VERSION 5.8 ;
BUSBITCHARS "[]" ;
DIVIDERCHAR "/" ;
UNITS
    DATABASE MICRONS 1000 ;
END UNITS

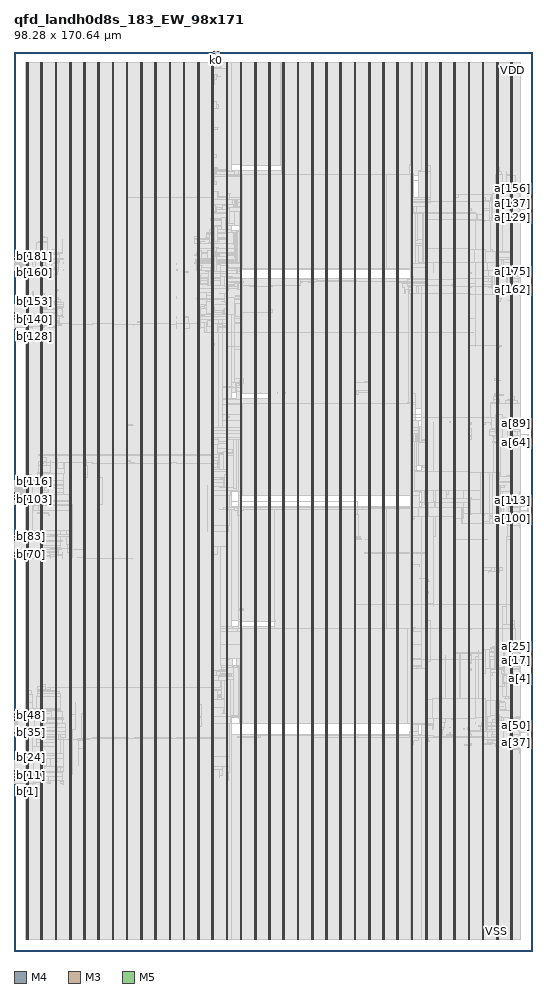
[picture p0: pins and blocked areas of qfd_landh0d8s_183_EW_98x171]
MACRO qfd_landh0d8s_183_EW_98x171
  FOREIGN qfd_landh0d8s_183_EW_98x171 0 0 ;
  CLASS BLOCK ;
  SIZE 98.28 BY 170.64 ;
  PIN a[0]
    DIRECTION INPUT ;
    USE SIGNAL ;
    PORT
      LAYER M4 ;
        RECT  98.196 52.56 98.28 52.584 ;
    END
  END a[0]
  PIN a[100]
    DIRECTION INPUT ;
    USE SIGNAL ;
    PORT
      LAYER M4 ;
        RECT  98.196 81.936 98.28 81.96 ;
    END
  END a[100]
  PIN a[101]
    DIRECTION INPUT ;
    USE SIGNAL ;
    PORT
      LAYER M4 ;
        RECT  98.196 82.08 98.28 82.104 ;
    END
  END a[101]
  PIN a[102]
    DIRECTION INPUT ;
    USE SIGNAL ;
    PORT
      LAYER M4 ;
        RECT  98.196 82.224 98.28 82.248 ;
    END
  END a[102]
  PIN a[103]
    DIRECTION INPUT ;
    USE SIGNAL ;
    PORT
      LAYER M4 ;
        RECT  98.196 82.368 98.28 82.392 ;
    END
  END a[103]
  PIN a[104]
    DIRECTION INPUT ;
    USE SIGNAL ;
    PORT
      LAYER M4 ;
        RECT  98.196 82.512 98.28 82.536 ;
    END
  END a[104]
  PIN a[105]
    DIRECTION INPUT ;
    USE SIGNAL ;
    PORT
      LAYER M4 ;
        RECT  98.196 82.656 98.28 82.68 ;
    END
  END a[105]
  PIN a[106]
    DIRECTION INPUT ;
    USE SIGNAL ;
    PORT
      LAYER M4 ;
        RECT  98.196 82.8 98.28 82.824 ;
    END
  END a[106]
  PIN a[107]
    DIRECTION INPUT ;
    USE SIGNAL ;
    PORT
      LAYER M4 ;
        RECT  98.196 82.944 98.28 82.968 ;
    END
  END a[107]
  PIN a[108]
    DIRECTION INPUT ;
    USE SIGNAL ;
    PORT
      LAYER M4 ;
        RECT  98.196 83.088 98.28 83.112 ;
    END
  END a[108]
  PIN a[109]
    DIRECTION INPUT ;
    USE SIGNAL ;
    PORT
      LAYER M4 ;
        RECT  98.196 83.232 98.28 83.256 ;
    END
  END a[109]
  PIN a[10]
    DIRECTION INPUT ;
    USE SIGNAL ;
    PORT
      LAYER M4 ;
        RECT  98.196 54 98.28 54.024 ;
    END
  END a[10]
  PIN a[110]
    DIRECTION INPUT ;
    USE SIGNAL ;
    PORT
      LAYER M4 ;
        RECT  98.196 83.376 98.28 83.4 ;
    END
  END a[110]
  PIN a[111]
    DIRECTION INPUT ;
    USE SIGNAL ;
    PORT
      LAYER M4 ;
        RECT  98.196 83.52 98.28 83.544 ;
    END
  END a[111]
  PIN a[112]
    DIRECTION INPUT ;
    USE SIGNAL ;
    PORT
      LAYER M4 ;
        RECT  98.196 83.664 98.28 83.688 ;
    END
  END a[112]
  PIN a[113]
    DIRECTION INPUT ;
    USE SIGNAL ;
    PORT
      LAYER M4 ;
        RECT  98.196 83.808 98.28 83.832 ;
    END
  END a[113]
  PIN a[114]
    DIRECTION INPUT ;
    USE SIGNAL ;
    PORT
      LAYER M4 ;
        RECT  98.196 83.952 98.28 83.976 ;
    END
  END a[114]
  PIN a[115]
    DIRECTION INPUT ;
    USE SIGNAL ;
    PORT
      LAYER M4 ;
        RECT  98.196 84.096 98.28 84.12 ;
    END
  END a[115]
  PIN a[116]
    DIRECTION INPUT ;
    USE SIGNAL ;
    PORT
      LAYER M4 ;
        RECT  98.196 84.24 98.28 84.264 ;
    END
  END a[116]
  PIN a[117]
    DIRECTION INPUT ;
    USE SIGNAL ;
    PORT
      LAYER M4 ;
        RECT  98.196 84.384 98.28 84.408 ;
    END
  END a[117]
  PIN a[118]
    DIRECTION INPUT ;
    USE SIGNAL ;
    PORT
      LAYER M4 ;
        RECT  98.196 84.528 98.28 84.552 ;
    END
  END a[118]
  PIN a[119]
    DIRECTION INPUT ;
    USE SIGNAL ;
    PORT
      LAYER M4 ;
        RECT  98.196 84.672 98.28 84.696 ;
    END
  END a[119]
  PIN a[11]
    DIRECTION INPUT ;
    USE SIGNAL ;
    PORT
      LAYER M4 ;
        RECT  98.196 54.144 98.28 54.168 ;
    END
  END a[11]
  PIN a[120]
    DIRECTION INPUT ;
    USE SIGNAL ;
    PORT
      LAYER M4 ;
        RECT  98.196 84.816 98.28 84.84 ;
    END
  END a[120]
  PIN a[121]
    DIRECTION INPUT ;
    USE SIGNAL ;
    PORT
      LAYER M4 ;
        RECT  98.196 84.96 98.28 84.984 ;
    END
  END a[121]
  PIN a[122]
    DIRECTION INPUT ;
    USE SIGNAL ;
    PORT
      LAYER M4 ;
        RECT  98.196 85.104 98.28 85.128 ;
    END
  END a[122]
  PIN a[123]
    DIRECTION INPUT ;
    USE SIGNAL ;
    PORT
      LAYER M4 ;
        RECT  98.196 85.248 98.28 85.272 ;
    END
  END a[123]
  PIN a[124]
    DIRECTION INPUT ;
    USE SIGNAL ;
    PORT
      LAYER M4 ;
        RECT  98.196 85.392 98.28 85.416 ;
    END
  END a[124]
  PIN a[125]
    DIRECTION INPUT ;
    USE SIGNAL ;
    PORT
      LAYER M4 ;
        RECT  98.196 85.536 98.28 85.56 ;
    END
  END a[125]
  PIN a[126]
    DIRECTION INPUT ;
    USE SIGNAL ;
    PORT
      LAYER M4 ;
        RECT  98.196 85.68 98.28 85.704 ;
    END
  END a[126]
  PIN a[127]
    DIRECTION INPUT ;
    USE SIGNAL ;
    PORT
      LAYER M4 ;
        RECT  98.196 85.824 98.28 85.848 ;
    END
  END a[127]
  PIN a[128]
    DIRECTION INPUT ;
    USE SIGNAL ;
    PORT
      LAYER M4 ;
        RECT  98.196 138.96 98.28 138.984 ;
    END
  END a[128]
  PIN a[129]
    DIRECTION INPUT ;
    USE SIGNAL ;
    PORT
      LAYER M4 ;
        RECT  98.196 139.104 98.28 139.128 ;
    END
  END a[129]
  PIN a[12]
    DIRECTION INPUT ;
    USE SIGNAL ;
    PORT
      LAYER M4 ;
        RECT  98.196 54.288 98.28 54.312 ;
    END
  END a[12]
  PIN a[130]
    DIRECTION INPUT ;
    USE SIGNAL ;
    PORT
      LAYER M4 ;
        RECT  98.196 139.248 98.28 139.272 ;
    END
  END a[130]
  PIN a[131]
    DIRECTION INPUT ;
    USE SIGNAL ;
    PORT
      LAYER M4 ;
        RECT  98.196 139.392 98.28 139.416 ;
    END
  END a[131]
  PIN a[132]
    DIRECTION INPUT ;
    USE SIGNAL ;
    PORT
      LAYER M4 ;
        RECT  98.196 139.536 98.28 139.56 ;
    END
  END a[132]
  PIN a[133]
    DIRECTION INPUT ;
    USE SIGNAL ;
    PORT
      LAYER M4 ;
        RECT  98.196 139.68 98.28 139.704 ;
    END
  END a[133]
  PIN a[134]
    DIRECTION INPUT ;
    USE SIGNAL ;
    PORT
      LAYER M4 ;
        RECT  98.196 139.824 98.28 139.848 ;
    END
  END a[134]
  PIN a[135]
    DIRECTION INPUT ;
    USE SIGNAL ;
    PORT
      LAYER M4 ;
        RECT  98.196 139.968 98.28 139.992 ;
    END
  END a[135]
  PIN a[136]
    DIRECTION INPUT ;
    USE SIGNAL ;
    PORT
      LAYER M4 ;
        RECT  98.196 140.112 98.28 140.136 ;
    END
  END a[136]
  PIN a[137]
    DIRECTION INPUT ;
    USE SIGNAL ;
    PORT
      LAYER M4 ;
        RECT  98.196 140.256 98.28 140.28 ;
    END
  END a[137]
  PIN a[138]
    DIRECTION INPUT ;
    USE SIGNAL ;
    PORT
      LAYER M4 ;
        RECT  98.196 140.4 98.28 140.424 ;
    END
  END a[138]
  PIN a[139]
    DIRECTION INPUT ;
    USE SIGNAL ;
    PORT
      LAYER M4 ;
        RECT  98.196 140.544 98.28 140.568 ;
    END
  END a[139]
  PIN a[13]
    DIRECTION INPUT ;
    USE SIGNAL ;
    PORT
      LAYER M4 ;
        RECT  98.196 54.432 98.28 54.456 ;
    END
  END a[13]
  PIN a[140]
    DIRECTION INPUT ;
    USE SIGNAL ;
    PORT
      LAYER M4 ;
        RECT  98.196 140.688 98.28 140.712 ;
    END
  END a[140]
  PIN a[141]
    DIRECTION INPUT ;
    USE SIGNAL ;
    PORT
      LAYER M4 ;
        RECT  98.196 140.832 98.28 140.856 ;
    END
  END a[141]
  PIN a[142]
    DIRECTION INPUT ;
    USE SIGNAL ;
    PORT
      LAYER M4 ;
        RECT  98.196 140.976 98.28 141 ;
    END
  END a[142]
  PIN a[143]
    DIRECTION INPUT ;
    USE SIGNAL ;
    PORT
      LAYER M4 ;
        RECT  98.196 141.12 98.28 141.144 ;
    END
  END a[143]
  PIN a[144]
    DIRECTION INPUT ;
    USE SIGNAL ;
    PORT
      LAYER M4 ;
        RECT  98.196 141.264 98.28 141.288 ;
    END
  END a[144]
  PIN a[145]
    DIRECTION INPUT ;
    USE SIGNAL ;
    PORT
      LAYER M4 ;
        RECT  98.196 141.408 98.28 141.432 ;
    END
  END a[145]
  PIN a[146]
    DIRECTION INPUT ;
    USE SIGNAL ;
    PORT
      LAYER M4 ;
        RECT  98.196 141.552 98.28 141.576 ;
    END
  END a[146]
  PIN a[147]
    DIRECTION INPUT ;
    USE SIGNAL ;
    PORT
      LAYER M4 ;
        RECT  98.196 141.696 98.28 141.72 ;
    END
  END a[147]
  PIN a[148]
    DIRECTION INPUT ;
    USE SIGNAL ;
    PORT
      LAYER M4 ;
        RECT  98.196 141.84 98.28 141.864 ;
    END
  END a[148]
  PIN a[149]
    DIRECTION INPUT ;
    USE SIGNAL ;
    PORT
      LAYER M4 ;
        RECT  98.196 141.984 98.28 142.008 ;
    END
  END a[149]
  PIN a[14]
    DIRECTION INPUT ;
    USE SIGNAL ;
    PORT
      LAYER M4 ;
        RECT  98.196 54.576 98.28 54.6 ;
    END
  END a[14]
  PIN a[150]
    DIRECTION INPUT ;
    USE SIGNAL ;
    PORT
      LAYER M4 ;
        RECT  98.196 142.128 98.28 142.152 ;
    END
  END a[150]
  PIN a[151]
    DIRECTION INPUT ;
    USE SIGNAL ;
    PORT
      LAYER M4 ;
        RECT  98.196 142.272 98.28 142.296 ;
    END
  END a[151]
  PIN a[152]
    DIRECTION INPUT ;
    USE SIGNAL ;
    PORT
      LAYER M4 ;
        RECT  98.196 142.416 98.28 142.44 ;
    END
  END a[152]
  PIN a[153]
    DIRECTION INPUT ;
    USE SIGNAL ;
    PORT
      LAYER M4 ;
        RECT  98.196 142.56 98.28 142.584 ;
    END
  END a[153]
  PIN a[154]
    DIRECTION INPUT ;
    USE SIGNAL ;
    PORT
      LAYER M4 ;
        RECT  98.196 142.704 98.28 142.728 ;
    END
  END a[154]
  PIN a[155]
    DIRECTION INPUT ;
    USE SIGNAL ;
    PORT
      LAYER M4 ;
        RECT  98.196 142.848 98.28 142.872 ;
    END
  END a[155]
  PIN a[156]
    DIRECTION INPUT ;
    USE SIGNAL ;
    PORT
      LAYER M4 ;
        RECT  98.196 142.992 98.28 143.016 ;
    END
  END a[156]
  PIN a[157]
    DIRECTION INPUT ;
    USE SIGNAL ;
    PORT
      LAYER M4 ;
        RECT  98.196 143.136 98.28 143.16 ;
    END
  END a[157]
  PIN a[158]
    DIRECTION INPUT ;
    USE SIGNAL ;
    PORT
      LAYER M4 ;
        RECT  98.196 143.28 98.28 143.304 ;
    END
  END a[158]
  PIN a[159]
    DIRECTION INPUT ;
    USE SIGNAL ;
    PORT
      LAYER M4 ;
        RECT  98.196 143.424 98.28 143.448 ;
    END
  END a[159]
  PIN a[15]
    DIRECTION INPUT ;
    USE SIGNAL ;
    PORT
      LAYER M4 ;
        RECT  98.196 54.72 98.28 54.744 ;
    END
  END a[15]
  PIN a[160]
    DIRECTION INPUT ;
    USE SIGNAL ;
    PORT
      LAYER M4 ;
        RECT  98.196 125.136 98.28 125.16 ;
    END
  END a[160]
  PIN a[161]
    DIRECTION INPUT ;
    USE SIGNAL ;
    PORT
      LAYER M4 ;
        RECT  98.196 125.28 98.28 125.304 ;
    END
  END a[161]
  PIN a[162]
    DIRECTION INPUT ;
    USE SIGNAL ;
    PORT
      LAYER M4 ;
        RECT  98.196 125.424 98.28 125.448 ;
    END
  END a[162]
  PIN a[163]
    DIRECTION INPUT ;
    USE SIGNAL ;
    PORT
      LAYER M4 ;
        RECT  98.196 125.568 98.28 125.592 ;
    END
  END a[163]
  PIN a[164]
    DIRECTION INPUT ;
    USE SIGNAL ;
    PORT
      LAYER M4 ;
        RECT  98.196 125.712 98.28 125.736 ;
    END
  END a[164]
  PIN a[165]
    DIRECTION INPUT ;
    USE SIGNAL ;
    PORT
      LAYER M4 ;
        RECT  98.196 125.856 98.28 125.88 ;
    END
  END a[165]
  PIN a[166]
    DIRECTION INPUT ;
    USE SIGNAL ;
    PORT
      LAYER M4 ;
        RECT  98.196 126 98.28 126.024 ;
    END
  END a[166]
  PIN a[167]
    DIRECTION INPUT ;
    USE SIGNAL ;
    PORT
      LAYER M4 ;
        RECT  98.196 126.144 98.28 126.168 ;
    END
  END a[167]
  PIN a[168]
    DIRECTION INPUT ;
    USE SIGNAL ;
    PORT
      LAYER M4 ;
        RECT  98.196 126.288 98.28 126.312 ;
    END
  END a[168]
  PIN a[169]
    DIRECTION INPUT ;
    USE SIGNAL ;
    PORT
      LAYER M4 ;
        RECT  98.196 126.432 98.28 126.456 ;
    END
  END a[169]
  PIN a[16]
    DIRECTION INPUT ;
    USE SIGNAL ;
    PORT
      LAYER M4 ;
        RECT  98.196 54.864 98.28 54.888 ;
    END
  END a[16]
  PIN a[170]
    DIRECTION INPUT ;
    USE SIGNAL ;
    PORT
      LAYER M4 ;
        RECT  98.196 126.576 98.28 126.6 ;
    END
  END a[170]
  PIN a[171]
    DIRECTION INPUT ;
    USE SIGNAL ;
    PORT
      LAYER M4 ;
        RECT  98.196 126.72 98.28 126.744 ;
    END
  END a[171]
  PIN a[172]
    DIRECTION INPUT ;
    USE SIGNAL ;
    PORT
      LAYER M4 ;
        RECT  98.196 126.864 98.28 126.888 ;
    END
  END a[172]
  PIN a[173]
    DIRECTION INPUT ;
    USE SIGNAL ;
    PORT
      LAYER M4 ;
        RECT  98.196 127.008 98.28 127.032 ;
    END
  END a[173]
  PIN a[174]
    DIRECTION INPUT ;
    USE SIGNAL ;
    PORT
      LAYER M4 ;
        RECT  98.196 127.152 98.28 127.176 ;
    END
  END a[174]
  PIN a[175]
    DIRECTION INPUT ;
    USE SIGNAL ;
    PORT
      LAYER M4 ;
        RECT  98.196 127.296 98.28 127.32 ;
    END
  END a[175]
  PIN a[176]
    DIRECTION INPUT ;
    USE SIGNAL ;
    PORT
      LAYER M4 ;
        RECT  98.196 127.44 98.28 127.464 ;
    END
  END a[176]
  PIN a[177]
    DIRECTION INPUT ;
    USE SIGNAL ;
    PORT
      LAYER M4 ;
        RECT  98.196 127.584 98.28 127.608 ;
    END
  END a[177]
  PIN a[178]
    DIRECTION INPUT ;
    USE SIGNAL ;
    PORT
      LAYER M4 ;
        RECT  98.196 127.728 98.28 127.752 ;
    END
  END a[178]
  PIN a[179]
    DIRECTION INPUT ;
    USE SIGNAL ;
    PORT
      LAYER M4 ;
        RECT  98.196 127.872 98.28 127.896 ;
    END
  END a[179]
  PIN a[17]
    DIRECTION INPUT ;
    USE SIGNAL ;
    PORT
      LAYER M4 ;
        RECT  98.196 55.008 98.28 55.032 ;
    END
  END a[17]
  PIN a[180]
    DIRECTION INPUT ;
    USE SIGNAL ;
    PORT
      LAYER M4 ;
        RECT  98.196 128.016 98.28 128.04 ;
    END
  END a[180]
  PIN a[181]
    DIRECTION INPUT ;
    USE SIGNAL ;
    PORT
      LAYER M4 ;
        RECT  98.196 128.16 98.28 128.184 ;
    END
  END a[181]
  PIN a[182]
    DIRECTION INPUT ;
    USE SIGNAL ;
    PORT
      LAYER M4 ;
        RECT  98.196 128.304 98.28 128.328 ;
    END
  END a[182]
  PIN a[18]
    DIRECTION INPUT ;
    USE SIGNAL ;
    PORT
      LAYER M4 ;
        RECT  98.196 55.152 98.28 55.176 ;
    END
  END a[18]
  PIN a[19]
    DIRECTION INPUT ;
    USE SIGNAL ;
    PORT
      LAYER M4 ;
        RECT  98.196 55.296 98.28 55.32 ;
    END
  END a[19]
  PIN a[1]
    DIRECTION INPUT ;
    USE SIGNAL ;
    PORT
      LAYER M4 ;
        RECT  98.196 52.704 98.28 52.728 ;
    END
  END a[1]
  PIN a[20]
    DIRECTION INPUT ;
    USE SIGNAL ;
    PORT
      LAYER M4 ;
        RECT  98.196 55.44 98.28 55.464 ;
    END
  END a[20]
  PIN a[21]
    DIRECTION INPUT ;
    USE SIGNAL ;
    PORT
      LAYER M4 ;
        RECT  98.196 55.584 98.28 55.608 ;
    END
  END a[21]
  PIN a[22]
    DIRECTION INPUT ;
    USE SIGNAL ;
    PORT
      LAYER M4 ;
        RECT  98.196 55.728 98.28 55.752 ;
    END
  END a[22]
  PIN a[23]
    DIRECTION INPUT ;
    USE SIGNAL ;
    PORT
      LAYER M4 ;
        RECT  98.196 55.872 98.28 55.896 ;
    END
  END a[23]
  PIN a[24]
    DIRECTION INPUT ;
    USE SIGNAL ;
    PORT
      LAYER M4 ;
        RECT  98.196 56.016 98.28 56.04 ;
    END
  END a[24]
  PIN a[25]
    DIRECTION INPUT ;
    USE SIGNAL ;
    PORT
      LAYER M4 ;
        RECT  98.196 56.16 98.28 56.184 ;
    END
  END a[25]
  PIN a[26]
    DIRECTION INPUT ;
    USE SIGNAL ;
    PORT
      LAYER M4 ;
        RECT  98.196 56.304 98.28 56.328 ;
    END
  END a[26]
  PIN a[27]
    DIRECTION INPUT ;
    USE SIGNAL ;
    PORT
      LAYER M4 ;
        RECT  98.196 56.448 98.28 56.472 ;
    END
  END a[27]
  PIN a[28]
    DIRECTION INPUT ;
    USE SIGNAL ;
    PORT
      LAYER M4 ;
        RECT  98.196 56.592 98.28 56.616 ;
    END
  END a[28]
  PIN a[29]
    DIRECTION INPUT ;
    USE SIGNAL ;
    PORT
      LAYER M4 ;
        RECT  98.196 56.736 98.28 56.76 ;
    END
  END a[29]
  PIN a[2]
    DIRECTION INPUT ;
    USE SIGNAL ;
    PORT
      LAYER M4 ;
        RECT  98.196 52.848 98.28 52.872 ;
    END
  END a[2]
  PIN a[30]
    DIRECTION INPUT ;
    USE SIGNAL ;
    PORT
      LAYER M4 ;
        RECT  98.196 56.88 98.28 56.904 ;
    END
  END a[30]
  PIN a[31]
    DIRECTION INPUT ;
    USE SIGNAL ;
    PORT
      LAYER M4 ;
        RECT  98.196 57.024 98.28 57.048 ;
    END
  END a[31]
  PIN a[32]
    DIRECTION INPUT ;
    USE SIGNAL ;
    PORT
      LAYER M4 ;
        RECT  98.196 38.736 98.28 38.76 ;
    END
  END a[32]
  PIN a[33]
    DIRECTION INPUT ;
    USE SIGNAL ;
    PORT
      LAYER M4 ;
        RECT  98.196 38.88 98.28 38.904 ;
    END
  END a[33]
  PIN a[34]
    DIRECTION INPUT ;
    USE SIGNAL ;
    PORT
      LAYER M4 ;
        RECT  98.196 39.024 98.28 39.048 ;
    END
  END a[34]
  PIN a[35]
    DIRECTION INPUT ;
    USE SIGNAL ;
    PORT
      LAYER M4 ;
        RECT  98.196 39.168 98.28 39.192 ;
    END
  END a[35]
  PIN a[36]
    DIRECTION INPUT ;
    USE SIGNAL ;
    PORT
      LAYER M4 ;
        RECT  98.196 39.312 98.28 39.336 ;
    END
  END a[36]
  PIN a[37]
    DIRECTION INPUT ;
    USE SIGNAL ;
    PORT
      LAYER M4 ;
        RECT  98.196 39.456 98.28 39.48 ;
    END
  END a[37]
  PIN a[38]
    DIRECTION INPUT ;
    USE SIGNAL ;
    PORT
      LAYER M4 ;
        RECT  98.196 39.6 98.28 39.624 ;
    END
  END a[38]
  PIN a[39]
    DIRECTION INPUT ;
    USE SIGNAL ;
    PORT
      LAYER M4 ;
        RECT  98.196 39.744 98.28 39.768 ;
    END
  END a[39]
  PIN a[3]
    DIRECTION INPUT ;
    USE SIGNAL ;
    PORT
      LAYER M4 ;
        RECT  98.196 52.992 98.28 53.016 ;
    END
  END a[3]
  PIN a[40]
    DIRECTION INPUT ;
    USE SIGNAL ;
    PORT
      LAYER M4 ;
        RECT  98.196 39.888 98.28 39.912 ;
    END
  END a[40]
  PIN a[41]
    DIRECTION INPUT ;
    USE SIGNAL ;
    PORT
      LAYER M4 ;
        RECT  98.196 40.032 98.28 40.056 ;
    END
  END a[41]
  PIN a[42]
    DIRECTION INPUT ;
    USE SIGNAL ;
    PORT
      LAYER M4 ;
        RECT  98.196 40.176 98.28 40.2 ;
    END
  END a[42]
  PIN a[43]
    DIRECTION INPUT ;
    USE SIGNAL ;
    PORT
      LAYER M4 ;
        RECT  98.196 40.32 98.28 40.344 ;
    END
  END a[43]
  PIN a[44]
    DIRECTION INPUT ;
    USE SIGNAL ;
    PORT
      LAYER M4 ;
        RECT  98.196 40.464 98.28 40.488 ;
    END
  END a[44]
  PIN a[45]
    DIRECTION INPUT ;
    USE SIGNAL ;
    PORT
      LAYER M4 ;
        RECT  98.196 40.608 98.28 40.632 ;
    END
  END a[45]
  PIN a[46]
    DIRECTION INPUT ;
    USE SIGNAL ;
    PORT
      LAYER M4 ;
        RECT  98.196 40.752 98.28 40.776 ;
    END
  END a[46]
  PIN a[47]
    DIRECTION INPUT ;
    USE SIGNAL ;
    PORT
      LAYER M4 ;
        RECT  98.196 40.896 98.28 40.92 ;
    END
  END a[47]
  PIN a[48]
    DIRECTION INPUT ;
    USE SIGNAL ;
    PORT
      LAYER M4 ;
        RECT  98.196 41.04 98.28 41.064 ;
    END
  END a[48]
  PIN a[49]
    DIRECTION INPUT ;
    USE SIGNAL ;
    PORT
      LAYER M4 ;
        RECT  98.196 41.184 98.28 41.208 ;
    END
  END a[49]
  PIN a[4]
    DIRECTION INPUT ;
    USE SIGNAL ;
    PORT
      LAYER M4 ;
        RECT  98.196 53.136 98.28 53.16 ;
    END
  END a[4]
  PIN a[50]
    DIRECTION INPUT ;
    USE SIGNAL ;
    PORT
      LAYER M4 ;
        RECT  98.196 41.328 98.28 41.352 ;
    END
  END a[50]
  PIN a[51]
    DIRECTION INPUT ;
    USE SIGNAL ;
    PORT
      LAYER M4 ;
        RECT  98.196 41.472 98.28 41.496 ;
    END
  END a[51]
  PIN a[52]
    DIRECTION INPUT ;
    USE SIGNAL ;
    PORT
      LAYER M4 ;
        RECT  98.196 41.616 98.28 41.64 ;
    END
  END a[52]
  PIN a[53]
    DIRECTION INPUT ;
    USE SIGNAL ;
    PORT
      LAYER M4 ;
        RECT  98.196 41.76 98.28 41.784 ;
    END
  END a[53]
  PIN a[54]
    DIRECTION INPUT ;
    USE SIGNAL ;
    PORT
      LAYER M4 ;
        RECT  98.196 41.904 98.28 41.928 ;
    END
  END a[54]
  PIN a[55]
    DIRECTION INPUT ;
    USE SIGNAL ;
    PORT
      LAYER M4 ;
        RECT  98.196 42.048 98.28 42.072 ;
    END
  END a[55]
  PIN a[56]
    DIRECTION INPUT ;
    USE SIGNAL ;
    PORT
      LAYER M4 ;
        RECT  98.196 42.192 98.28 42.216 ;
    END
  END a[56]
  PIN a[57]
    DIRECTION INPUT ;
    USE SIGNAL ;
    PORT
      LAYER M4 ;
        RECT  98.196 42.336 98.28 42.36 ;
    END
  END a[57]
  PIN a[58]
    DIRECTION INPUT ;
    USE SIGNAL ;
    PORT
      LAYER M4 ;
        RECT  98.196 42.48 98.28 42.504 ;
    END
  END a[58]
  PIN a[59]
    DIRECTION INPUT ;
    USE SIGNAL ;
    PORT
      LAYER M4 ;
        RECT  98.196 42.624 98.28 42.648 ;
    END
  END a[59]
  PIN a[5]
    DIRECTION INPUT ;
    USE SIGNAL ;
    PORT
      LAYER M4 ;
        RECT  98.196 53.28 98.28 53.304 ;
    END
  END a[5]
  PIN a[60]
    DIRECTION INPUT ;
    USE SIGNAL ;
    PORT
      LAYER M4 ;
        RECT  98.196 42.768 98.28 42.792 ;
    END
  END a[60]
  PIN a[61]
    DIRECTION INPUT ;
    USE SIGNAL ;
    PORT
      LAYER M4 ;
        RECT  98.196 42.912 98.28 42.936 ;
    END
  END a[61]
  PIN a[62]
    DIRECTION INPUT ;
    USE SIGNAL ;
    PORT
      LAYER M4 ;
        RECT  98.196 43.056 98.28 43.08 ;
    END
  END a[62]
  PIN a[63]
    DIRECTION INPUT ;
    USE SIGNAL ;
    PORT
      LAYER M4 ;
        RECT  98.196 43.2 98.28 43.224 ;
    END
  END a[63]
  PIN a[64]
    DIRECTION INPUT ;
    USE SIGNAL ;
    PORT
      LAYER M4 ;
        RECT  98.196 96.336 98.28 96.36 ;
    END
  END a[64]
  PIN a[65]
    DIRECTION INPUT ;
    USE SIGNAL ;
    PORT
      LAYER M4 ;
        RECT  98.196 96.48 98.28 96.504 ;
    END
  END a[65]
  PIN a[66]
    DIRECTION INPUT ;
    USE SIGNAL ;
    PORT
      LAYER M4 ;
        RECT  98.196 96.624 98.28 96.648 ;
    END
  END a[66]
  PIN a[67]
    DIRECTION INPUT ;
    USE SIGNAL ;
    PORT
      LAYER M4 ;
        RECT  98.196 96.768 98.28 96.792 ;
    END
  END a[67]
  PIN a[68]
    DIRECTION INPUT ;
    USE SIGNAL ;
    PORT
      LAYER M4 ;
        RECT  98.196 96.912 98.28 96.936 ;
    END
  END a[68]
  PIN a[69]
    DIRECTION INPUT ;
    USE SIGNAL ;
    PORT
      LAYER M4 ;
        RECT  98.196 97.056 98.28 97.08 ;
    END
  END a[69]
  PIN a[6]
    DIRECTION INPUT ;
    USE SIGNAL ;
    PORT
      LAYER M4 ;
        RECT  98.196 53.424 98.28 53.448 ;
    END
  END a[6]
  PIN a[70]
    DIRECTION INPUT ;
    USE SIGNAL ;
    PORT
      LAYER M4 ;
        RECT  98.196 97.2 98.28 97.224 ;
    END
  END a[70]
  PIN a[71]
    DIRECTION INPUT ;
    USE SIGNAL ;
    PORT
      LAYER M4 ;
        RECT  98.196 97.344 98.28 97.368 ;
    END
  END a[71]
  PIN a[72]
    DIRECTION INPUT ;
    USE SIGNAL ;
    PORT
      LAYER M4 ;
        RECT  98.196 97.488 98.28 97.512 ;
    END
  END a[72]
  PIN a[73]
    DIRECTION INPUT ;
    USE SIGNAL ;
    PORT
      LAYER M4 ;
        RECT  98.196 97.632 98.28 97.656 ;
    END
  END a[73]
  PIN a[74]
    DIRECTION INPUT ;
    USE SIGNAL ;
    PORT
      LAYER M4 ;
        RECT  98.196 97.776 98.28 97.8 ;
    END
  END a[74]
  PIN a[75]
    DIRECTION INPUT ;
    USE SIGNAL ;
    PORT
      LAYER M4 ;
        RECT  98.196 97.92 98.28 97.944 ;
    END
  END a[75]
  PIN a[76]
    DIRECTION INPUT ;
    USE SIGNAL ;
    PORT
      LAYER M4 ;
        RECT  98.196 98.064 98.28 98.088 ;
    END
  END a[76]
  PIN a[77]
    DIRECTION INPUT ;
    USE SIGNAL ;
    PORT
      LAYER M4 ;
        RECT  98.196 98.208 98.28 98.232 ;
    END
  END a[77]
  PIN a[78]
    DIRECTION INPUT ;
    USE SIGNAL ;
    PORT
      LAYER M4 ;
        RECT  98.196 98.352 98.28 98.376 ;
    END
  END a[78]
  PIN a[79]
    DIRECTION INPUT ;
    USE SIGNAL ;
    PORT
      LAYER M4 ;
        RECT  98.196 98.496 98.28 98.52 ;
    END
  END a[79]
  PIN a[7]
    DIRECTION INPUT ;
    USE SIGNAL ;
    PORT
      LAYER M4 ;
        RECT  98.196 53.568 98.28 53.592 ;
    END
  END a[7]
  PIN a[80]
    DIRECTION INPUT ;
    USE SIGNAL ;
    PORT
      LAYER M4 ;
        RECT  98.196 98.64 98.28 98.664 ;
    END
  END a[80]
  PIN a[81]
    DIRECTION INPUT ;
    USE SIGNAL ;
    PORT
      LAYER M4 ;
        RECT  98.196 98.784 98.28 98.808 ;
    END
  END a[81]
  PIN a[82]
    DIRECTION INPUT ;
    USE SIGNAL ;
    PORT
      LAYER M4 ;
        RECT  98.196 98.928 98.28 98.952 ;
    END
  END a[82]
  PIN a[83]
    DIRECTION INPUT ;
    USE SIGNAL ;
    PORT
      LAYER M4 ;
        RECT  98.196 99.072 98.28 99.096 ;
    END
  END a[83]
  PIN a[84]
    DIRECTION INPUT ;
    USE SIGNAL ;
    PORT
      LAYER M4 ;
        RECT  98.196 99.216 98.28 99.24 ;
    END
  END a[84]
  PIN a[85]
    DIRECTION INPUT ;
    USE SIGNAL ;
    PORT
      LAYER M4 ;
        RECT  98.196 99.36 98.28 99.384 ;
    END
  END a[85]
  PIN a[86]
    DIRECTION INPUT ;
    USE SIGNAL ;
    PORT
      LAYER M4 ;
        RECT  98.196 99.504 98.28 99.528 ;
    END
  END a[86]
  PIN a[87]
    DIRECTION INPUT ;
    USE SIGNAL ;
    PORT
      LAYER M4 ;
        RECT  98.196 99.648 98.28 99.672 ;
    END
  END a[87]
  PIN a[88]
    DIRECTION INPUT ;
    USE SIGNAL ;
    PORT
      LAYER M4 ;
        RECT  98.196 99.792 98.28 99.816 ;
    END
  END a[88]
  PIN a[89]
    DIRECTION INPUT ;
    USE SIGNAL ;
    PORT
      LAYER M4 ;
        RECT  98.196 99.936 98.28 99.96 ;
    END
  END a[89]
  PIN a[8]
    DIRECTION INPUT ;
    USE SIGNAL ;
    PORT
      LAYER M4 ;
        RECT  98.196 53.712 98.28 53.736 ;
    END
  END a[8]
  PIN a[90]
    DIRECTION INPUT ;
    USE SIGNAL ;
    PORT
      LAYER M4 ;
        RECT  98.196 100.08 98.28 100.104 ;
    END
  END a[90]
  PIN a[91]
    DIRECTION INPUT ;
    USE SIGNAL ;
    PORT
      LAYER M4 ;
        RECT  98.196 100.224 98.28 100.248 ;
    END
  END a[91]
  PIN a[92]
    DIRECTION INPUT ;
    USE SIGNAL ;
    PORT
      LAYER M4 ;
        RECT  98.196 100.368 98.28 100.392 ;
    END
  END a[92]
  PIN a[93]
    DIRECTION INPUT ;
    USE SIGNAL ;
    PORT
      LAYER M4 ;
        RECT  98.196 100.512 98.28 100.536 ;
    END
  END a[93]
  PIN a[94]
    DIRECTION INPUT ;
    USE SIGNAL ;
    PORT
      LAYER M4 ;
        RECT  98.196 100.656 98.28 100.68 ;
    END
  END a[94]
  PIN a[95]
    DIRECTION INPUT ;
    USE SIGNAL ;
    PORT
      LAYER M4 ;
        RECT  98.196 100.8 98.28 100.824 ;
    END
  END a[95]
  PIN a[96]
    DIRECTION INPUT ;
    USE SIGNAL ;
    PORT
      LAYER M4 ;
        RECT  98.196 81.36 98.28 81.384 ;
    END
  END a[96]
  PIN a[97]
    DIRECTION INPUT ;
    USE SIGNAL ;
    PORT
      LAYER M4 ;
        RECT  98.196 81.504 98.28 81.528 ;
    END
  END a[97]
  PIN a[98]
    DIRECTION INPUT ;
    USE SIGNAL ;
    PORT
      LAYER M4 ;
        RECT  98.196 81.648 98.28 81.672 ;
    END
  END a[98]
  PIN a[99]
    DIRECTION INPUT ;
    USE SIGNAL ;
    PORT
      LAYER M4 ;
        RECT  98.196 81.792 98.28 81.816 ;
    END
  END a[99]
  PIN a[9]
    DIRECTION INPUT ;
    USE SIGNAL ;
    PORT
      LAYER M4 ;
        RECT  98.196 53.856 98.28 53.88 ;
    END
  END a[9]
  PIN b[0]
    DIRECTION OUTPUT ;
    USE SIGNAL ;
    PORT
      LAYER M4 ;
        RECT  0 31.68 0.084 31.704 ;
    END
  END b[0]
  PIN b[100]
    DIRECTION OUTPUT ;
    USE SIGNAL ;
    PORT
      LAYER M4 ;
        RECT  0 85.248 0.084 85.272 ;
    END
  END b[100]
  PIN b[101]
    DIRECTION OUTPUT ;
    USE SIGNAL ;
    PORT
      LAYER M4 ;
        RECT  0 85.392 0.084 85.416 ;
    END
  END b[101]
  PIN b[102]
    DIRECTION OUTPUT ;
    USE SIGNAL ;
    PORT
      LAYER M4 ;
        RECT  0 85.536 0.084 85.56 ;
    END
  END b[102]
  PIN b[103]
    DIRECTION OUTPUT ;
    USE SIGNAL ;
    PORT
      LAYER M4 ;
        RECT  0 85.68 0.084 85.704 ;
    END
  END b[103]
  PIN b[104]
    DIRECTION OUTPUT ;
    USE SIGNAL ;
    PORT
      LAYER M4 ;
        RECT  0 85.824 0.084 85.848 ;
    END
  END b[104]
  PIN b[105]
    DIRECTION OUTPUT ;
    USE SIGNAL ;
    PORT
      LAYER M4 ;
        RECT  0 85.968 0.084 85.992 ;
    END
  END b[105]
  PIN b[106]
    DIRECTION OUTPUT ;
    USE SIGNAL ;
    PORT
      LAYER M4 ;
        RECT  0 86.112 0.084 86.136 ;
    END
  END b[106]
  PIN b[107]
    DIRECTION OUTPUT ;
    USE SIGNAL ;
    PORT
      LAYER M4 ;
        RECT  0 86.256 0.084 86.28 ;
    END
  END b[107]
  PIN b[108]
    DIRECTION OUTPUT ;
    USE SIGNAL ;
    PORT
      LAYER M4 ;
        RECT  0 86.4 0.084 86.424 ;
    END
  END b[108]
  PIN b[109]
    DIRECTION OUTPUT ;
    USE SIGNAL ;
    PORT
      LAYER M4 ;
        RECT  0 86.544 0.084 86.568 ;
    END
  END b[109]
  PIN b[10]
    DIRECTION OUTPUT ;
    USE SIGNAL ;
    PORT
      LAYER M4 ;
        RECT  0 33.12 0.084 33.144 ;
    END
  END b[10]
  PIN b[110]
    DIRECTION OUTPUT ;
    USE SIGNAL ;
    PORT
      LAYER M4 ;
        RECT  0 86.688 0.084 86.712 ;
    END
  END b[110]
  PIN b[111]
    DIRECTION OUTPUT ;
    USE SIGNAL ;
    PORT
      LAYER M4 ;
        RECT  0 86.832 0.084 86.856 ;
    END
  END b[111]
  PIN b[112]
    DIRECTION OUTPUT ;
    USE SIGNAL ;
    PORT
      LAYER M4 ;
        RECT  0 86.976 0.084 87 ;
    END
  END b[112]
  PIN b[113]
    DIRECTION OUTPUT ;
    USE SIGNAL ;
    PORT
      LAYER M4 ;
        RECT  0 87.12 0.084 87.144 ;
    END
  END b[113]
  PIN b[114]
    DIRECTION OUTPUT ;
    USE SIGNAL ;
    PORT
      LAYER M4 ;
        RECT  0 87.264 0.084 87.288 ;
    END
  END b[114]
  PIN b[115]
    DIRECTION OUTPUT ;
    USE SIGNAL ;
    PORT
      LAYER M4 ;
        RECT  0 87.408 0.084 87.432 ;
    END
  END b[115]
  PIN b[116]
    DIRECTION OUTPUT ;
    USE SIGNAL ;
    PORT
      LAYER M4 ;
        RECT  0 87.552 0.084 87.576 ;
    END
  END b[116]
  PIN b[117]
    DIRECTION OUTPUT ;
    USE SIGNAL ;
    PORT
      LAYER M4 ;
        RECT  0 87.696 0.084 87.72 ;
    END
  END b[117]
  PIN b[118]
    DIRECTION OUTPUT ;
    USE SIGNAL ;
    PORT
      LAYER M4 ;
        RECT  0 87.84 0.084 87.864 ;
    END
  END b[118]
  PIN b[119]
    DIRECTION OUTPUT ;
    USE SIGNAL ;
    PORT
      LAYER M4 ;
        RECT  0 87.984 0.084 88.008 ;
    END
  END b[119]
  PIN b[11]
    DIRECTION OUTPUT ;
    USE SIGNAL ;
    PORT
      LAYER M4 ;
        RECT  0 33.264 0.084 33.288 ;
    END
  END b[11]
  PIN b[120]
    DIRECTION OUTPUT ;
    USE SIGNAL ;
    PORT
      LAYER M4 ;
        RECT  0 88.128 0.084 88.152 ;
    END
  END b[120]
  PIN b[121]
    DIRECTION OUTPUT ;
    USE SIGNAL ;
    PORT
      LAYER M4 ;
        RECT  0 88.272 0.084 88.296 ;
    END
  END b[121]
  PIN b[122]
    DIRECTION OUTPUT ;
    USE SIGNAL ;
    PORT
      LAYER M4 ;
        RECT  0 88.416 0.084 88.44 ;
    END
  END b[122]
  PIN b[123]
    DIRECTION OUTPUT ;
    USE SIGNAL ;
    PORT
      LAYER M4 ;
        RECT  0 88.56 0.084 88.584 ;
    END
  END b[123]
  PIN b[124]
    DIRECTION OUTPUT ;
    USE SIGNAL ;
    PORT
      LAYER M4 ;
        RECT  0 88.704 0.084 88.728 ;
    END
  END b[124]
  PIN b[125]
    DIRECTION OUTPUT ;
    USE SIGNAL ;
    PORT
      LAYER M4 ;
        RECT  0 88.848 0.084 88.872 ;
    END
  END b[125]
  PIN b[126]
    DIRECTION OUTPUT ;
    USE SIGNAL ;
    PORT
      LAYER M4 ;
        RECT  0 88.992 0.084 89.016 ;
    END
  END b[126]
  PIN b[127]
    DIRECTION OUTPUT ;
    USE SIGNAL ;
    PORT
      LAYER M4 ;
        RECT  0 89.136 0.084 89.16 ;
    END
  END b[127]
  PIN b[128]
    DIRECTION OUTPUT ;
    USE SIGNAL ;
    PORT
      LAYER M4 ;
        RECT  0 118.08 0.084 118.104 ;
    END
  END b[128]
  PIN b[129]
    DIRECTION OUTPUT ;
    USE SIGNAL ;
    PORT
      LAYER M4 ;
        RECT  0 118.224 0.084 118.248 ;
    END
  END b[129]
  PIN b[12]
    DIRECTION OUTPUT ;
    USE SIGNAL ;
    PORT
      LAYER M4 ;
        RECT  0 33.408 0.084 33.432 ;
    END
  END b[12]
  PIN b[130]
    DIRECTION OUTPUT ;
    USE SIGNAL ;
    PORT
      LAYER M4 ;
        RECT  0 118.368 0.084 118.392 ;
    END
  END b[130]
  PIN b[131]
    DIRECTION OUTPUT ;
    USE SIGNAL ;
    PORT
      LAYER M4 ;
        RECT  0 118.512 0.084 118.536 ;
    END
  END b[131]
  PIN b[132]
    DIRECTION OUTPUT ;
    USE SIGNAL ;
    PORT
      LAYER M4 ;
        RECT  0 118.656 0.084 118.68 ;
    END
  END b[132]
  PIN b[133]
    DIRECTION OUTPUT ;
    USE SIGNAL ;
    PORT
      LAYER M4 ;
        RECT  0 118.8 0.084 118.824 ;
    END
  END b[133]
  PIN b[134]
    DIRECTION OUTPUT ;
    USE SIGNAL ;
    PORT
      LAYER M4 ;
        RECT  0 118.944 0.084 118.968 ;
    END
  END b[134]
  PIN b[135]
    DIRECTION OUTPUT ;
    USE SIGNAL ;
    PORT
      LAYER M4 ;
        RECT  0 119.088 0.084 119.112 ;
    END
  END b[135]
  PIN b[136]
    DIRECTION OUTPUT ;
    USE SIGNAL ;
    PORT
      LAYER M4 ;
        RECT  0 119.232 0.084 119.256 ;
    END
  END b[136]
  PIN b[137]
    DIRECTION OUTPUT ;
    USE SIGNAL ;
    PORT
      LAYER M4 ;
        RECT  0 119.376 0.084 119.4 ;
    END
  END b[137]
  PIN b[138]
    DIRECTION OUTPUT ;
    USE SIGNAL ;
    PORT
      LAYER M4 ;
        RECT  0 119.52 0.084 119.544 ;
    END
  END b[138]
  PIN b[139]
    DIRECTION OUTPUT ;
    USE SIGNAL ;
    PORT
      LAYER M4 ;
        RECT  0 119.664 0.084 119.688 ;
    END
  END b[139]
  PIN b[13]
    DIRECTION OUTPUT ;
    USE SIGNAL ;
    PORT
      LAYER M4 ;
        RECT  0 33.552 0.084 33.576 ;
    END
  END b[13]
  PIN b[140]
    DIRECTION OUTPUT ;
    USE SIGNAL ;
    PORT
      LAYER M4 ;
        RECT  0 119.808 0.084 119.832 ;
    END
  END b[140]
  PIN b[141]
    DIRECTION OUTPUT ;
    USE SIGNAL ;
    PORT
      LAYER M4 ;
        RECT  0 119.952 0.084 119.976 ;
    END
  END b[141]
  PIN b[142]
    DIRECTION OUTPUT ;
    USE SIGNAL ;
    PORT
      LAYER M4 ;
        RECT  0 120.096 0.084 120.12 ;
    END
  END b[142]
  PIN b[143]
    DIRECTION OUTPUT ;
    USE SIGNAL ;
    PORT
      LAYER M4 ;
        RECT  0 120.24 0.084 120.264 ;
    END
  END b[143]
  PIN b[144]
    DIRECTION OUTPUT ;
    USE SIGNAL ;
    PORT
      LAYER M4 ;
        RECT  0 120.384 0.084 120.408 ;
    END
  END b[144]
  PIN b[145]
    DIRECTION OUTPUT ;
    USE SIGNAL ;
    PORT
      LAYER M4 ;
        RECT  0 120.528 0.084 120.552 ;
    END
  END b[145]
  PIN b[146]
    DIRECTION OUTPUT ;
    USE SIGNAL ;
    PORT
      LAYER M4 ;
        RECT  0 120.672 0.084 120.696 ;
    END
  END b[146]
  PIN b[147]
    DIRECTION OUTPUT ;
    USE SIGNAL ;
    PORT
      LAYER M4 ;
        RECT  0 120.816 0.084 120.84 ;
    END
  END b[147]
  PIN b[148]
    DIRECTION OUTPUT ;
    USE SIGNAL ;
    PORT
      LAYER M4 ;
        RECT  0 120.96 0.084 120.984 ;
    END
  END b[148]
  PIN b[149]
    DIRECTION OUTPUT ;
    USE SIGNAL ;
    PORT
      LAYER M4 ;
        RECT  0 121.104 0.084 121.128 ;
    END
  END b[149]
  PIN b[14]
    DIRECTION OUTPUT ;
    USE SIGNAL ;
    PORT
      LAYER M4 ;
        RECT  0 33.696 0.084 33.72 ;
    END
  END b[14]
  PIN b[150]
    DIRECTION OUTPUT ;
    USE SIGNAL ;
    PORT
      LAYER M4 ;
        RECT  0 121.248 0.084 121.272 ;
    END
  END b[150]
  PIN b[151]
    DIRECTION OUTPUT ;
    USE SIGNAL ;
    PORT
      LAYER M4 ;
        RECT  0 121.392 0.084 121.416 ;
    END
  END b[151]
  PIN b[152]
    DIRECTION OUTPUT ;
    USE SIGNAL ;
    PORT
      LAYER M4 ;
        RECT  0 121.536 0.084 121.56 ;
    END
  END b[152]
  PIN b[153]
    DIRECTION OUTPUT ;
    USE SIGNAL ;
    PORT
      LAYER M4 ;
        RECT  0 121.68 0.084 121.704 ;
    END
  END b[153]
  PIN b[154]
    DIRECTION OUTPUT ;
    USE SIGNAL ;
    PORT
      LAYER M4 ;
        RECT  0 121.824 0.084 121.848 ;
    END
  END b[154]
  PIN b[155]
    DIRECTION OUTPUT ;
    USE SIGNAL ;
    PORT
      LAYER M4 ;
        RECT  0 121.968 0.084 121.992 ;
    END
  END b[155]
  PIN b[156]
    DIRECTION OUTPUT ;
    USE SIGNAL ;
    PORT
      LAYER M4 ;
        RECT  0 122.112 0.084 122.136 ;
    END
  END b[156]
  PIN b[157]
    DIRECTION OUTPUT ;
    USE SIGNAL ;
    PORT
      LAYER M4 ;
        RECT  0 122.256 0.084 122.28 ;
    END
  END b[157]
  PIN b[158]
    DIRECTION OUTPUT ;
    USE SIGNAL ;
    PORT
      LAYER M4 ;
        RECT  0 122.4 0.084 122.424 ;
    END
  END b[158]
  PIN b[159]
    DIRECTION OUTPUT ;
    USE SIGNAL ;
    PORT
      LAYER M4 ;
        RECT  0 122.544 0.084 122.568 ;
    END
  END b[159]
  PIN b[15]
    DIRECTION OUTPUT ;
    USE SIGNAL ;
    PORT
      LAYER M4 ;
        RECT  0 33.84 0.084 33.864 ;
    END
  END b[15]
  PIN b[160]
    DIRECTION OUTPUT ;
    USE SIGNAL ;
    PORT
      LAYER M4 ;
        RECT  0 128.592 0.084 128.616 ;
    END
  END b[160]
  PIN b[161]
    DIRECTION OUTPUT ;
    USE SIGNAL ;
    PORT
      LAYER M4 ;
        RECT  0 128.736 0.084 128.76 ;
    END
  END b[161]
  PIN b[162]
    DIRECTION OUTPUT ;
    USE SIGNAL ;
    PORT
      LAYER M4 ;
        RECT  0 128.88 0.084 128.904 ;
    END
  END b[162]
  PIN b[163]
    DIRECTION OUTPUT ;
    USE SIGNAL ;
    PORT
      LAYER M4 ;
        RECT  0 129.024 0.084 129.048 ;
    END
  END b[163]
  PIN b[164]
    DIRECTION OUTPUT ;
    USE SIGNAL ;
    PORT
      LAYER M4 ;
        RECT  0 129.168 0.084 129.192 ;
    END
  END b[164]
  PIN b[165]
    DIRECTION OUTPUT ;
    USE SIGNAL ;
    PORT
      LAYER M4 ;
        RECT  0 129.312 0.084 129.336 ;
    END
  END b[165]
  PIN b[166]
    DIRECTION OUTPUT ;
    USE SIGNAL ;
    PORT
      LAYER M4 ;
        RECT  0 129.456 0.084 129.48 ;
    END
  END b[166]
  PIN b[167]
    DIRECTION OUTPUT ;
    USE SIGNAL ;
    PORT
      LAYER M4 ;
        RECT  0 129.6 0.084 129.624 ;
    END
  END b[167]
  PIN b[168]
    DIRECTION OUTPUT ;
    USE SIGNAL ;
    PORT
      LAYER M4 ;
        RECT  0 129.744 0.084 129.768 ;
    END
  END b[168]
  PIN b[169]
    DIRECTION OUTPUT ;
    USE SIGNAL ;
    PORT
      LAYER M4 ;
        RECT  0 129.888 0.084 129.912 ;
    END
  END b[169]
  PIN b[16]
    DIRECTION OUTPUT ;
    USE SIGNAL ;
    PORT
      LAYER M4 ;
        RECT  0 33.984 0.084 34.008 ;
    END
  END b[16]
  PIN b[170]
    DIRECTION OUTPUT ;
    USE SIGNAL ;
    PORT
      LAYER M4 ;
        RECT  0 130.032 0.084 130.056 ;
    END
  END b[170]
  PIN b[171]
    DIRECTION OUTPUT ;
    USE SIGNAL ;
    PORT
      LAYER M4 ;
        RECT  0 130.176 0.084 130.2 ;
    END
  END b[171]
  PIN b[172]
    DIRECTION OUTPUT ;
    USE SIGNAL ;
    PORT
      LAYER M4 ;
        RECT  0 130.32 0.084 130.344 ;
    END
  END b[172]
  PIN b[173]
    DIRECTION OUTPUT ;
    USE SIGNAL ;
    PORT
      LAYER M4 ;
        RECT  0 130.464 0.084 130.488 ;
    END
  END b[173]
  PIN b[174]
    DIRECTION OUTPUT ;
    USE SIGNAL ;
    PORT
      LAYER M4 ;
        RECT  0 130.608 0.084 130.632 ;
    END
  END b[174]
  PIN b[175]
    DIRECTION OUTPUT ;
    USE SIGNAL ;
    PORT
      LAYER M4 ;
        RECT  0 130.752 0.084 130.776 ;
    END
  END b[175]
  PIN b[176]
    DIRECTION OUTPUT ;
    USE SIGNAL ;
    PORT
      LAYER M4 ;
        RECT  0 130.896 0.084 130.92 ;
    END
  END b[176]
  PIN b[177]
    DIRECTION OUTPUT ;
    USE SIGNAL ;
    PORT
      LAYER M4 ;
        RECT  0 131.04 0.084 131.064 ;
    END
  END b[177]
  PIN b[178]
    DIRECTION OUTPUT ;
    USE SIGNAL ;
    PORT
      LAYER M4 ;
        RECT  0 131.184 0.084 131.208 ;
    END
  END b[178]
  PIN b[179]
    DIRECTION OUTPUT ;
    USE SIGNAL ;
    PORT
      LAYER M4 ;
        RECT  0 131.328 0.084 131.352 ;
    END
  END b[179]
  PIN b[17]
    DIRECTION OUTPUT ;
    USE SIGNAL ;
    PORT
      LAYER M4 ;
        RECT  0 34.128 0.084 34.152 ;
    END
  END b[17]
  PIN b[180]
    DIRECTION OUTPUT ;
    USE SIGNAL ;
    PORT
      LAYER M4 ;
        RECT  0 131.472 0.084 131.496 ;
    END
  END b[180]
  PIN b[181]
    DIRECTION OUTPUT ;
    USE SIGNAL ;
    PORT
      LAYER M4 ;
        RECT  0 131.616 0.084 131.64 ;
    END
  END b[181]
  PIN b[182]
    DIRECTION OUTPUT ;
    USE SIGNAL ;
    PORT
      LAYER M4 ;
        RECT  0 131.76 0.084 131.784 ;
    END
  END b[182]
  PIN b[18]
    DIRECTION OUTPUT ;
    USE SIGNAL ;
    PORT
      LAYER M4 ;
        RECT  0 34.272 0.084 34.296 ;
    END
  END b[18]
  PIN b[19]
    DIRECTION OUTPUT ;
    USE SIGNAL ;
    PORT
      LAYER M4 ;
        RECT  0 34.416 0.084 34.44 ;
    END
  END b[19]
  PIN b[1]
    DIRECTION OUTPUT ;
    USE SIGNAL ;
    PORT
      LAYER M4 ;
        RECT  0 31.824 0.084 31.848 ;
    END
  END b[1]
  PIN b[20]
    DIRECTION OUTPUT ;
    USE SIGNAL ;
    PORT
      LAYER M4 ;
        RECT  0 34.56 0.084 34.584 ;
    END
  END b[20]
  PIN b[21]
    DIRECTION OUTPUT ;
    USE SIGNAL ;
    PORT
      LAYER M4 ;
        RECT  0 34.704 0.084 34.728 ;
    END
  END b[21]
  PIN b[22]
    DIRECTION OUTPUT ;
    USE SIGNAL ;
    PORT
      LAYER M4 ;
        RECT  0 34.848 0.084 34.872 ;
    END
  END b[22]
  PIN b[23]
    DIRECTION OUTPUT ;
    USE SIGNAL ;
    PORT
      LAYER M4 ;
        RECT  0 34.992 0.084 35.016 ;
    END
  END b[23]
  PIN b[24]
    DIRECTION OUTPUT ;
    USE SIGNAL ;
    PORT
      LAYER M4 ;
        RECT  0 35.136 0.084 35.16 ;
    END
  END b[24]
  PIN b[25]
    DIRECTION OUTPUT ;
    USE SIGNAL ;
    PORT
      LAYER M4 ;
        RECT  0 35.28 0.084 35.304 ;
    END
  END b[25]
  PIN b[26]
    DIRECTION OUTPUT ;
    USE SIGNAL ;
    PORT
      LAYER M4 ;
        RECT  0 35.424 0.084 35.448 ;
    END
  END b[26]
  PIN b[27]
    DIRECTION OUTPUT ;
    USE SIGNAL ;
    PORT
      LAYER M4 ;
        RECT  0 35.568 0.084 35.592 ;
    END
  END b[27]
  PIN b[28]
    DIRECTION OUTPUT ;
    USE SIGNAL ;
    PORT
      LAYER M4 ;
        RECT  0 35.712 0.084 35.736 ;
    END
  END b[28]
  PIN b[29]
    DIRECTION OUTPUT ;
    USE SIGNAL ;
    PORT
      LAYER M4 ;
        RECT  0 35.856 0.084 35.88 ;
    END
  END b[29]
  PIN b[2]
    DIRECTION OUTPUT ;
    USE SIGNAL ;
    PORT
      LAYER M4 ;
        RECT  0 31.968 0.084 31.992 ;
    END
  END b[2]
  PIN b[30]
    DIRECTION OUTPUT ;
    USE SIGNAL ;
    PORT
      LAYER M4 ;
        RECT  0 36 0.084 36.024 ;
    END
  END b[30]
  PIN b[31]
    DIRECTION OUTPUT ;
    USE SIGNAL ;
    PORT
      LAYER M4 ;
        RECT  0 36.144 0.084 36.168 ;
    END
  END b[31]
  PIN b[32]
    DIRECTION OUTPUT ;
    USE SIGNAL ;
    PORT
      LAYER M4 ;
        RECT  0 40.896 0.084 40.92 ;
    END
  END b[32]
  PIN b[33]
    DIRECTION OUTPUT ;
    USE SIGNAL ;
    PORT
      LAYER M4 ;
        RECT  0 41.04 0.084 41.064 ;
    END
  END b[33]
  PIN b[34]
    DIRECTION OUTPUT ;
    USE SIGNAL ;
    PORT
      LAYER M4 ;
        RECT  0 41.184 0.084 41.208 ;
    END
  END b[34]
  PIN b[35]
    DIRECTION OUTPUT ;
    USE SIGNAL ;
    PORT
      LAYER M4 ;
        RECT  0 41.328 0.084 41.352 ;
    END
  END b[35]
  PIN b[36]
    DIRECTION OUTPUT ;
    USE SIGNAL ;
    PORT
      LAYER M4 ;
        RECT  0 41.472 0.084 41.496 ;
    END
  END b[36]
  PIN b[37]
    DIRECTION OUTPUT ;
    USE SIGNAL ;
    PORT
      LAYER M4 ;
        RECT  0 41.616 0.084 41.64 ;
    END
  END b[37]
  PIN b[38]
    DIRECTION OUTPUT ;
    USE SIGNAL ;
    PORT
      LAYER M4 ;
        RECT  0 41.76 0.084 41.784 ;
    END
  END b[38]
  PIN b[39]
    DIRECTION OUTPUT ;
    USE SIGNAL ;
    PORT
      LAYER M4 ;
        RECT  0 41.904 0.084 41.928 ;
    END
  END b[39]
  PIN b[3]
    DIRECTION OUTPUT ;
    USE SIGNAL ;
    PORT
      LAYER M4 ;
        RECT  0 32.112 0.084 32.136 ;
    END
  END b[3]
  PIN b[40]
    DIRECTION OUTPUT ;
    USE SIGNAL ;
    PORT
      LAYER M4 ;
        RECT  0 42.048 0.084 42.072 ;
    END
  END b[40]
  PIN b[41]
    DIRECTION OUTPUT ;
    USE SIGNAL ;
    PORT
      LAYER M4 ;
        RECT  0 42.192 0.084 42.216 ;
    END
  END b[41]
  PIN b[42]
    DIRECTION OUTPUT ;
    USE SIGNAL ;
    PORT
      LAYER M4 ;
        RECT  0 42.336 0.084 42.36 ;
    END
  END b[42]
  PIN b[43]
    DIRECTION OUTPUT ;
    USE SIGNAL ;
    PORT
      LAYER M4 ;
        RECT  0 42.48 0.084 42.504 ;
    END
  END b[43]
  PIN b[44]
    DIRECTION OUTPUT ;
    USE SIGNAL ;
    PORT
      LAYER M4 ;
        RECT  0 42.624 0.084 42.648 ;
    END
  END b[44]
  PIN b[45]
    DIRECTION OUTPUT ;
    USE SIGNAL ;
    PORT
      LAYER M4 ;
        RECT  0 42.768 0.084 42.792 ;
    END
  END b[45]
  PIN b[46]
    DIRECTION OUTPUT ;
    USE SIGNAL ;
    PORT
      LAYER M4 ;
        RECT  0 42.912 0.084 42.936 ;
    END
  END b[46]
  PIN b[47]
    DIRECTION OUTPUT ;
    USE SIGNAL ;
    PORT
      LAYER M4 ;
        RECT  0 43.056 0.084 43.08 ;
    END
  END b[47]
  PIN b[48]
    DIRECTION OUTPUT ;
    USE SIGNAL ;
    PORT
      LAYER M4 ;
        RECT  0 43.2 0.084 43.224 ;
    END
  END b[48]
  PIN b[49]
    DIRECTION OUTPUT ;
    USE SIGNAL ;
    PORT
      LAYER M4 ;
        RECT  0 43.344 0.084 43.368 ;
    END
  END b[49]
  PIN b[4]
    DIRECTION OUTPUT ;
    USE SIGNAL ;
    PORT
      LAYER M4 ;
        RECT  0 32.256 0.084 32.28 ;
    END
  END b[4]
  PIN b[50]
    DIRECTION OUTPUT ;
    USE SIGNAL ;
    PORT
      LAYER M4 ;
        RECT  0 43.488 0.084 43.512 ;
    END
  END b[50]
  PIN b[51]
    DIRECTION OUTPUT ;
    USE SIGNAL ;
    PORT
      LAYER M4 ;
        RECT  0 43.632 0.084 43.656 ;
    END
  END b[51]
  PIN b[52]
    DIRECTION OUTPUT ;
    USE SIGNAL ;
    PORT
      LAYER M4 ;
        RECT  0 43.776 0.084 43.8 ;
    END
  END b[52]
  PIN b[53]
    DIRECTION OUTPUT ;
    USE SIGNAL ;
    PORT
      LAYER M4 ;
        RECT  0 43.92 0.084 43.944 ;
    END
  END b[53]
  PIN b[54]
    DIRECTION OUTPUT ;
    USE SIGNAL ;
    PORT
      LAYER M4 ;
        RECT  0 44.064 0.084 44.088 ;
    END
  END b[54]
  PIN b[55]
    DIRECTION OUTPUT ;
    USE SIGNAL ;
    PORT
      LAYER M4 ;
        RECT  0 44.208 0.084 44.232 ;
    END
  END b[55]
  PIN b[56]
    DIRECTION OUTPUT ;
    USE SIGNAL ;
    PORT
      LAYER M4 ;
        RECT  0 44.352 0.084 44.376 ;
    END
  END b[56]
  PIN b[57]
    DIRECTION OUTPUT ;
    USE SIGNAL ;
    PORT
      LAYER M4 ;
        RECT  0 44.496 0.084 44.52 ;
    END
  END b[57]
  PIN b[58]
    DIRECTION OUTPUT ;
    USE SIGNAL ;
    PORT
      LAYER M4 ;
        RECT  0 44.64 0.084 44.664 ;
    END
  END b[58]
  PIN b[59]
    DIRECTION OUTPUT ;
    USE SIGNAL ;
    PORT
      LAYER M4 ;
        RECT  0 44.784 0.084 44.808 ;
    END
  END b[59]
  PIN b[5]
    DIRECTION OUTPUT ;
    USE SIGNAL ;
    PORT
      LAYER M4 ;
        RECT  0 32.4 0.084 32.424 ;
    END
  END b[5]
  PIN b[60]
    DIRECTION OUTPUT ;
    USE SIGNAL ;
    PORT
      LAYER M4 ;
        RECT  0 44.928 0.084 44.952 ;
    END
  END b[60]
  PIN b[61]
    DIRECTION OUTPUT ;
    USE SIGNAL ;
    PORT
      LAYER M4 ;
        RECT  0 45.072 0.084 45.096 ;
    END
  END b[61]
  PIN b[62]
    DIRECTION OUTPUT ;
    USE SIGNAL ;
    PORT
      LAYER M4 ;
        RECT  0 45.216 0.084 45.24 ;
    END
  END b[62]
  PIN b[63]
    DIRECTION OUTPUT ;
    USE SIGNAL ;
    PORT
      LAYER M4 ;
        RECT  0 45.36 0.084 45.384 ;
    END
  END b[63]
  PIN b[64]
    DIRECTION OUTPUT ;
    USE SIGNAL ;
    PORT
      LAYER M4 ;
        RECT  0 74.304 0.084 74.328 ;
    END
  END b[64]
  PIN b[65]
    DIRECTION OUTPUT ;
    USE SIGNAL ;
    PORT
      LAYER M4 ;
        RECT  0 74.448 0.084 74.472 ;
    END
  END b[65]
  PIN b[66]
    DIRECTION OUTPUT ;
    USE SIGNAL ;
    PORT
      LAYER M4 ;
        RECT  0 74.592 0.084 74.616 ;
    END
  END b[66]
  PIN b[67]
    DIRECTION OUTPUT ;
    USE SIGNAL ;
    PORT
      LAYER M4 ;
        RECT  0 74.736 0.084 74.76 ;
    END
  END b[67]
  PIN b[68]
    DIRECTION OUTPUT ;
    USE SIGNAL ;
    PORT
      LAYER M4 ;
        RECT  0 74.88 0.084 74.904 ;
    END
  END b[68]
  PIN b[69]
    DIRECTION OUTPUT ;
    USE SIGNAL ;
    PORT
      LAYER M4 ;
        RECT  0 75.024 0.084 75.048 ;
    END
  END b[69]
  PIN b[6]
    DIRECTION OUTPUT ;
    USE SIGNAL ;
    PORT
      LAYER M4 ;
        RECT  0 32.544 0.084 32.568 ;
    END
  END b[6]
  PIN b[70]
    DIRECTION OUTPUT ;
    USE SIGNAL ;
    PORT
      LAYER M4 ;
        RECT  0 75.168 0.084 75.192 ;
    END
  END b[70]
  PIN b[71]
    DIRECTION OUTPUT ;
    USE SIGNAL ;
    PORT
      LAYER M4 ;
        RECT  0 75.312 0.084 75.336 ;
    END
  END b[71]
  PIN b[72]
    DIRECTION OUTPUT ;
    USE SIGNAL ;
    PORT
      LAYER M4 ;
        RECT  0 75.456 0.084 75.48 ;
    END
  END b[72]
  PIN b[73]
    DIRECTION OUTPUT ;
    USE SIGNAL ;
    PORT
      LAYER M4 ;
        RECT  0 75.6 0.084 75.624 ;
    END
  END b[73]
  PIN b[74]
    DIRECTION OUTPUT ;
    USE SIGNAL ;
    PORT
      LAYER M4 ;
        RECT  0 75.744 0.084 75.768 ;
    END
  END b[74]
  PIN b[75]
    DIRECTION OUTPUT ;
    USE SIGNAL ;
    PORT
      LAYER M4 ;
        RECT  0 75.888 0.084 75.912 ;
    END
  END b[75]
  PIN b[76]
    DIRECTION OUTPUT ;
    USE SIGNAL ;
    PORT
      LAYER M4 ;
        RECT  0 76.032 0.084 76.056 ;
    END
  END b[76]
  PIN b[77]
    DIRECTION OUTPUT ;
    USE SIGNAL ;
    PORT
      LAYER M4 ;
        RECT  0 76.176 0.084 76.2 ;
    END
  END b[77]
  PIN b[78]
    DIRECTION OUTPUT ;
    USE SIGNAL ;
    PORT
      LAYER M4 ;
        RECT  0 76.32 0.084 76.344 ;
    END
  END b[78]
  PIN b[79]
    DIRECTION OUTPUT ;
    USE SIGNAL ;
    PORT
      LAYER M4 ;
        RECT  0 76.464 0.084 76.488 ;
    END
  END b[79]
  PIN b[7]
    DIRECTION OUTPUT ;
    USE SIGNAL ;
    PORT
      LAYER M4 ;
        RECT  0 32.688 0.084 32.712 ;
    END
  END b[7]
  PIN b[80]
    DIRECTION OUTPUT ;
    USE SIGNAL ;
    PORT
      LAYER M4 ;
        RECT  0 76.608 0.084 76.632 ;
    END
  END b[80]
  PIN b[81]
    DIRECTION OUTPUT ;
    USE SIGNAL ;
    PORT
      LAYER M4 ;
        RECT  0 76.752 0.084 76.776 ;
    END
  END b[81]
  PIN b[82]
    DIRECTION OUTPUT ;
    USE SIGNAL ;
    PORT
      LAYER M4 ;
        RECT  0 76.896 0.084 76.92 ;
    END
  END b[82]
  PIN b[83]
    DIRECTION OUTPUT ;
    USE SIGNAL ;
    PORT
      LAYER M4 ;
        RECT  0 77.04 0.084 77.064 ;
    END
  END b[83]
  PIN b[84]
    DIRECTION OUTPUT ;
    USE SIGNAL ;
    PORT
      LAYER M4 ;
        RECT  0 77.184 0.084 77.208 ;
    END
  END b[84]
  PIN b[85]
    DIRECTION OUTPUT ;
    USE SIGNAL ;
    PORT
      LAYER M4 ;
        RECT  0 77.328 0.084 77.352 ;
    END
  END b[85]
  PIN b[86]
    DIRECTION OUTPUT ;
    USE SIGNAL ;
    PORT
      LAYER M4 ;
        RECT  0 77.472 0.084 77.496 ;
    END
  END b[86]
  PIN b[87]
    DIRECTION OUTPUT ;
    USE SIGNAL ;
    PORT
      LAYER M4 ;
        RECT  0 77.616 0.084 77.64 ;
    END
  END b[87]
  PIN b[88]
    DIRECTION OUTPUT ;
    USE SIGNAL ;
    PORT
      LAYER M4 ;
        RECT  0 77.76 0.084 77.784 ;
    END
  END b[88]
  PIN b[89]
    DIRECTION OUTPUT ;
    USE SIGNAL ;
    PORT
      LAYER M4 ;
        RECT  0 77.904 0.084 77.928 ;
    END
  END b[89]
  PIN b[8]
    DIRECTION OUTPUT ;
    USE SIGNAL ;
    PORT
      LAYER M4 ;
        RECT  0 32.832 0.084 32.856 ;
    END
  END b[8]
  PIN b[90]
    DIRECTION OUTPUT ;
    USE SIGNAL ;
    PORT
      LAYER M4 ;
        RECT  0 78.048 0.084 78.072 ;
    END
  END b[90]
  PIN b[91]
    DIRECTION OUTPUT ;
    USE SIGNAL ;
    PORT
      LAYER M4 ;
        RECT  0 78.192 0.084 78.216 ;
    END
  END b[91]
  PIN b[92]
    DIRECTION OUTPUT ;
    USE SIGNAL ;
    PORT
      LAYER M4 ;
        RECT  0 78.336 0.084 78.36 ;
    END
  END b[92]
  PIN b[93]
    DIRECTION OUTPUT ;
    USE SIGNAL ;
    PORT
      LAYER M4 ;
        RECT  0 78.48 0.084 78.504 ;
    END
  END b[93]
  PIN b[94]
    DIRECTION OUTPUT ;
    USE SIGNAL ;
    PORT
      LAYER M4 ;
        RECT  0 78.624 0.084 78.648 ;
    END
  END b[94]
  PIN b[95]
    DIRECTION OUTPUT ;
    USE SIGNAL ;
    PORT
      LAYER M4 ;
        RECT  0 78.768 0.084 78.792 ;
    END
  END b[95]
  PIN b[96]
    DIRECTION OUTPUT ;
    USE SIGNAL ;
    PORT
      LAYER M4 ;
        RECT  0 84.672 0.084 84.696 ;
    END
  END b[96]
  PIN b[97]
    DIRECTION OUTPUT ;
    USE SIGNAL ;
    PORT
      LAYER M4 ;
        RECT  0 84.816 0.084 84.84 ;
    END
  END b[97]
  PIN b[98]
    DIRECTION OUTPUT ;
    USE SIGNAL ;
    PORT
      LAYER M4 ;
        RECT  0 84.96 0.084 84.984 ;
    END
  END b[98]
  PIN b[99]
    DIRECTION OUTPUT ;
    USE SIGNAL ;
    PORT
      LAYER M4 ;
        RECT  0 85.104 0.084 85.128 ;
    END
  END b[99]
  PIN b[9]
    DIRECTION OUTPUT ;
    USE SIGNAL ;
    PORT
      LAYER M4 ;
        RECT  0 32.976 0.084 33 ;
    END
  END b[9]
  PIN ck
    DIRECTION INPUT ;
    USE SIGNAL ;
    PORT
      LAYER M3 ;
        RECT  37.908 170.603 37.926 170.64 ;
    END
  END ck
  PIN ck_s
    DIRECTION INPUT ;
    USE SIGNAL ;
    PORT
      LAYER M3 ;
        RECT  38.016 170.603 38.034 170.64 ;
    END
  END ck_s
  PIN en
    DIRECTION INPUT ;
    USE SIGNAL ;
    PORT
      LAYER M3 ;
        RECT  38.124 170.603 38.142 170.64 ;
    END
  END en
  PIN fault
    DIRECTION OUTPUT ;
    USE SIGNAL ;
    PORT
      LAYER M3 ;
        RECT  38.232 170.603 38.25 170.64 ;
    END
  END fault
  PIN k0
    DIRECTION INPUT ;
    USE SIGNAL ;
    PORT
      LAYER M3 ;
        RECT  38.34 170.603 38.358 170.64 ;
    END
  END k0
  PIN k1
    DIRECTION INPUT ;
    USE SIGNAL ;
    PORT
      LAYER M3 ;
        RECT  38.448 170.603 38.466 170.64 ;
    END
  END k1
  PIN k2
    DIRECTION INPUT ;
    USE SIGNAL ;
    PORT
      LAYER M3 ;
        RECT  38.556 170.603 38.574 170.64 ;
    END
  END k2
  PIN k3
    DIRECTION INPUT ;
    USE SIGNAL ;
    PORT
      LAYER M3 ;
        RECT  38.664 170.603 38.682 170.64 ;
    END
  END k3
  PIN rs
    DIRECTION INPUT ;
    USE SIGNAL ;
    PORT
      LAYER M3 ;
        RECT  38.772 170.603 38.79 170.64 ;
    END
  END rs
  PIN tie_hi
    DIRECTION OUTPUT ;
    USE SIGNAL ;
    PORT
      LAYER M3 ;
        RECT  38.88 170.603 38.898 170.64 ;
    END
  END tie_hi
  PIN tie_lo
    DIRECTION OUTPUT ;
    USE SIGNAL ;
    PORT
      LAYER M3 ;
        RECT  38.988 170.603 39.006 170.64 ;
    END
  END tie_lo
  PIN VDD
    DIRECTION INOUT ;
    USE POWER ;
    PORT
      LAYER M5 ;
        RECT  94.392 2.151 94.512 168.489 ;
        RECT  91.692 2.151 91.812 168.489 ;
        RECT  88.992 2.151 89.112 168.489 ;
        RECT  86.292 2.151 86.412 168.489 ;
        RECT  83.592 2.151 83.712 168.489 ;
        RECT  80.892 2.151 81.012 168.489 ;
        RECT  78.192 2.151 78.312 168.489 ;
        RECT  75.492 2.151 75.612 168.489 ;
        RECT  72.792 2.151 72.912 168.489 ;
        RECT  70.092 2.151 70.212 168.489 ;
        RECT  67.392 2.151 67.512 168.489 ;
        RECT  64.692 2.151 64.812 168.489 ;
        RECT  61.992 2.151 62.112 168.489 ;
        RECT  59.292 2.151 59.412 168.489 ;
        RECT  56.592 2.151 56.712 168.489 ;
        RECT  53.892 2.151 54.012 168.489 ;
        RECT  51.192 2.151 51.312 168.489 ;
        RECT  48.492 2.151 48.612 168.489 ;
        RECT  45.792 2.151 45.912 168.489 ;
        RECT  43.092 2.151 43.212 168.489 ;
        RECT  40.392 2.151 40.512 168.489 ;
        RECT  37.692 2.151 37.812 168.489 ;
        RECT  34.992 2.151 35.112 168.489 ;
        RECT  32.292 2.151 32.412 168.489 ;
        RECT  29.592 2.151 29.712 168.489 ;
        RECT  26.892 2.151 27.012 168.489 ;
        RECT  24.192 2.151 24.312 168.489 ;
        RECT  21.492 2.151 21.612 168.489 ;
        RECT  18.792 2.151 18.912 168.489 ;
        RECT  16.092 2.151 16.212 168.489 ;
        RECT  13.392 2.151 13.512 168.489 ;
        RECT  10.692 2.151 10.812 168.489 ;
        RECT  7.992 2.151 8.112 168.489 ;
        RECT  5.292 2.151 5.412 168.489 ;
        RECT  2.592 2.151 2.712 168.489 ;
    END
  END VDD
  PIN VSS
    DIRECTION INOUT ;
    USE GROUND ;
    PORT
      LAYER M5 ;
        RECT  94.2 2.137 94.32 168.503 ;
        RECT  91.5 2.137 91.62 168.503 ;
        RECT  88.8 2.137 88.92 168.503 ;
        RECT  86.1 2.137 86.22 168.503 ;
        RECT  83.4 2.137 83.52 168.503 ;
        RECT  80.7 2.137 80.82 168.503 ;
        RECT  78 2.137 78.12 168.503 ;
        RECT  75.3 2.137 75.42 168.503 ;
        RECT  72.6 2.137 72.72 168.503 ;
        RECT  69.9 2.137 70.02 168.503 ;
        RECT  67.2 2.137 67.32 168.503 ;
        RECT  64.5 2.137 64.62 168.503 ;
        RECT  61.8 2.137 61.92 168.503 ;
        RECT  59.1 2.137 59.22 168.503 ;
        RECT  56.4 2.137 56.52 168.503 ;
        RECT  53.7 2.137 53.82 168.503 ;
        RECT  51 2.137 51.12 168.503 ;
        RECT  48.3 2.137 48.42 168.503 ;
        RECT  45.6 2.137 45.72 168.503 ;
        RECT  42.9 2.137 43.02 168.503 ;
        RECT  40.2 2.137 40.32 168.503 ;
        RECT  37.5 2.137 37.62 168.503 ;
        RECT  34.8 2.137 34.92 168.503 ;
        RECT  32.1 2.137 32.22 168.503 ;
        RECT  29.4 2.137 29.52 168.503 ;
        RECT  26.7 2.137 26.82 168.503 ;
        RECT  24 2.137 24.12 168.503 ;
        RECT  21.3 2.137 21.42 168.503 ;
        RECT  18.6 2.137 18.72 168.503 ;
        RECT  15.9 2.137 16.02 168.503 ;
        RECT  13.2 2.137 13.32 168.503 ;
        RECT  10.5 2.137 10.62 168.503 ;
        RECT  7.8 2.137 7.92 168.503 ;
        RECT  5.1 2.137 5.22 168.503 ;
        RECT  2.4 2.137 2.52 168.503 ;
    END
  END VSS
  # OT_OBS_CLOSED layer=M5 d_um=1.536 added=163
  OBS
    LAYER RVTN ;
     RECT  2.16 2.16 96.12 2.295 ;
     RECT  2.16 2.565 96.12 2.835 ;
     RECT  2.16 3.105 96.12 3.375 ;
     RECT  2.16 3.645 96.12 3.915 ;
     RECT  2.16 4.185 96.12 4.455 ;
     RECT  2.16 4.725 96.12 4.995 ;
     RECT  2.16 5.265 96.12 5.535 ;
     RECT  2.16 5.805 96.12 6.075 ;
     RECT  2.16 6.345 96.12 6.615 ;
     RECT  2.16 6.885 96.12 7.155 ;
     RECT  2.16 7.425 96.12 7.695 ;
     RECT  2.16 7.965 96.12 8.235 ;
     RECT  2.16 8.505 96.12 8.775 ;
     RECT  2.16 9.045 96.12 9.315 ;
     RECT  2.16 9.585 96.12 9.855 ;
     RECT  2.16 10.125 96.12 10.395 ;
     RECT  2.16 10.665 96.12 10.935 ;
     RECT  2.16 11.205 96.12 11.475 ;
     RECT  2.16 11.745 96.12 12.015 ;
     RECT  2.16 12.285 96.12 12.555 ;
     RECT  2.16 12.825 96.12 13.095 ;
     RECT  2.16 13.365 96.12 13.635 ;
     RECT  2.16 13.905 96.12 14.175 ;
     RECT  2.16 14.445 96.12 14.715 ;
     RECT  2.16 14.985 96.12 15.255 ;
     RECT  2.16 15.525 96.12 15.795 ;
     RECT  2.16 16.065 96.12 16.335 ;
     RECT  2.16 16.605 96.12 16.875 ;
     RECT  2.16 17.145 96.12 17.415 ;
     RECT  2.16 17.685 96.12 17.955 ;
     RECT  2.16 18.225 96.12 18.495 ;
     RECT  2.16 18.765 96.12 19.035 ;
     RECT  2.16 19.305 96.12 19.575 ;
     RECT  2.16 19.845 96.12 20.115 ;
     RECT  2.16 20.385 96.12 20.655 ;
     RECT  2.16 20.925 96.12 21.195 ;
     RECT  2.16 21.465 96.12 21.735 ;
     RECT  2.16 22.005 96.12 22.275 ;
     RECT  2.16 22.545 96.12 22.815 ;
     RECT  2.16 23.085 96.12 23.355 ;
     RECT  2.16 23.625 96.12 23.895 ;
     RECT  2.16 24.165 96.12 24.435 ;
     RECT  2.16 24.705 96.12 24.975 ;
     RECT  2.16 25.245 96.12 25.515 ;
     RECT  2.16 25.785 96.12 26.055 ;
     RECT  2.16 26.325 96.12 26.595 ;
     RECT  2.16 26.865 96.12 27.135 ;
     RECT  2.16 27.405 96.12 27.675 ;
     RECT  2.16 27.945 96.12 28.215 ;
     RECT  2.16 28.485 96.12 28.755 ;
     RECT  2.16 29.025 96.12 29.295 ;
     RECT  2.16 29.565 96.12 29.835 ;
     RECT  2.16 30.105 96.12 30.375 ;
     RECT  2.16 30.645 96.12 30.915 ;
     RECT  2.16 31.185 96.12 31.455 ;
     RECT  2.16 31.725 96.12 31.995 ;
     RECT  2.16 32.265 96.12 32.535 ;
     RECT  2.16 32.805 96.12 33.075 ;
     RECT  2.16 33.345 96.12 33.615 ;
     RECT  2.16 33.885 96.12 34.155 ;
     RECT  2.16 34.425 96.12 34.695 ;
     RECT  2.16 34.965 96.12 35.235 ;
     RECT  2.16 35.505 96.12 35.775 ;
     RECT  2.16 36.045 96.12 36.315 ;
     RECT  2.16 36.585 96.12 36.855 ;
     RECT  2.16 37.125 96.12 37.395 ;
     RECT  2.16 37.665 96.12 37.935 ;
     RECT  2.16 38.205 96.12 38.475 ;
     RECT  2.16 38.745 96.12 39.015 ;
     RECT  2.16 39.285 96.12 39.555 ;
     RECT  2.16 39.825 96.12 40.095 ;
     RECT  2.16 40.365 96.12 40.635 ;
     RECT  2.16 40.905 96.12 41.04 ;
     RECT  2.16 41.04 41.148 41.175 ;
     RECT  77.22 41.04 96.12 41.175 ;
     RECT  2.16 41.445 41.148 41.715 ;
     RECT  77.22 41.445 96.12 41.715 ;
     RECT  2.16 41.985 41.148 42.255 ;
     RECT  77.22 41.985 96.12 42.255 ;
     RECT  2.16 42.525 41.148 42.795 ;
     RECT  77.22 42.525 96.12 42.795 ;
     RECT  2.16 43.065 41.148 43.335 ;
     RECT  77.22 43.065 96.12 43.335 ;
     RECT  2.16 43.605 41.148 43.875 ;
     RECT  77.22 43.605 96.12 43.875 ;
     RECT  2.16 44.145 41.148 44.415 ;
     RECT  77.22 44.145 96.12 44.415 ;
     RECT  2.16 44.685 41.148 44.955 ;
     RECT  77.22 44.685 96.12 44.955 ;
     RECT  2.16 45.225 41.148 45.495 ;
     RECT  77.22 45.225 96.12 45.495 ;
     RECT  2.16 45.765 41.148 46.035 ;
     RECT  77.22 45.765 96.12 46.035 ;
     RECT  2.16 46.305 41.148 46.575 ;
     RECT  77.22 46.305 96.12 46.575 ;
     RECT  2.16 46.845 41.148 47.115 ;
     RECT  77.22 46.845 96.12 47.115 ;
     RECT  2.16 47.385 41.148 47.655 ;
     RECT  77.22 47.385 96.12 47.655 ;
     RECT  2.16 47.925 41.148 48.195 ;
     RECT  77.22 47.925 96.12 48.195 ;
     RECT  2.16 48.465 41.148 48.735 ;
     RECT  77.22 48.465 96.12 48.735 ;
     RECT  2.16 49.005 41.148 49.275 ;
     RECT  77.22 49.005 96.12 49.275 ;
     RECT  2.16 49.545 41.148 49.815 ;
     RECT  77.22 49.545 96.12 49.815 ;
     RECT  2.16 50.085 41.148 50.355 ;
     RECT  77.22 50.085 96.12 50.355 ;
     RECT  2.16 50.625 41.148 50.895 ;
     RECT  77.22 50.625 96.12 50.895 ;
     RECT  2.16 51.165 41.148 51.435 ;
     RECT  77.22 51.165 96.12 51.435 ;
     RECT  2.16 51.705 41.148 51.975 ;
     RECT  77.22 51.705 96.12 51.975 ;
     RECT  2.16 52.245 41.148 52.515 ;
     RECT  77.22 52.245 96.12 52.515 ;
     RECT  2.16 52.785 41.148 53.055 ;
     RECT  77.22 52.785 96.12 53.055 ;
     RECT  2.16 53.325 41.148 53.595 ;
     RECT  77.22 53.325 96.12 53.595 ;
     RECT  2.16 53.865 41.148 54.135 ;
     RECT  77.22 53.865 96.12 54.135 ;
     RECT  2.16 54.405 41.148 54.675 ;
     RECT  77.22 54.405 96.12 54.675 ;
     RECT  2.16 54.945 41.148 55.215 ;
     RECT  77.22 54.945 96.12 55.215 ;
     RECT  2.16 55.485 41.148 55.755 ;
     RECT  77.22 55.485 96.12 55.755 ;
     RECT  2.16 56.025 41.148 56.295 ;
     RECT  77.22 56.025 96.12 56.295 ;
     RECT  2.16 56.565 41.148 56.835 ;
     RECT  77.22 56.565 96.12 56.835 ;
     RECT  2.16 57.105 41.148 57.375 ;
     RECT  77.22 57.105 96.12 57.375 ;
     RECT  2.16 57.645 41.148 57.915 ;
     RECT  77.22 57.645 96.12 57.915 ;
     RECT  2.16 58.185 41.148 58.455 ;
     RECT  77.22 58.185 96.12 58.455 ;
     RECT  2.16 58.725 41.148 58.995 ;
     RECT  77.22 58.725 96.12 58.995 ;
     RECT  2.16 59.265 41.148 59.535 ;
     RECT  77.22 59.265 96.12 59.535 ;
     RECT  2.16 59.805 41.148 60.075 ;
     RECT  77.22 59.805 96.12 60.075 ;
     RECT  2.16 60.345 41.148 60.615 ;
     RECT  77.22 60.345 96.12 60.615 ;
     RECT  2.16 60.885 41.148 61.155 ;
     RECT  77.22 60.885 96.12 61.155 ;
     RECT  2.16 61.425 41.148 61.695 ;
     RECT  77.22 61.425 96.12 61.695 ;
     RECT  2.16 61.965 41.148 62.235 ;
     RECT  77.22 61.965 96.12 62.235 ;
     RECT  2.16 62.505 41.148 62.64 ;
     RECT  77.22 62.505 96.12 62.64 ;
     RECT  2.16 62.64 96.12 62.775 ;
     RECT  2.16 63.045 96.12 63.315 ;
     RECT  2.16 63.585 96.12 63.855 ;
     RECT  2.16 64.125 96.12 64.395 ;
     RECT  2.16 64.665 96.12 64.935 ;
     RECT  2.16 65.205 96.12 65.475 ;
     RECT  2.16 65.745 96.12 66.015 ;
     RECT  2.16 66.285 96.12 66.555 ;
     RECT  2.16 66.825 96.12 67.095 ;
     RECT  2.16 67.365 96.12 67.635 ;
     RECT  2.16 67.905 96.12 68.175 ;
     RECT  2.16 68.445 96.12 68.715 ;
     RECT  2.16 68.985 96.12 69.255 ;
     RECT  2.16 69.525 96.12 69.795 ;
     RECT  2.16 70.065 96.12 70.335 ;
     RECT  2.16 70.605 96.12 70.875 ;
     RECT  2.16 71.145 96.12 71.415 ;
     RECT  2.16 71.685 96.12 71.955 ;
     RECT  2.16 72.225 96.12 72.495 ;
     RECT  2.16 72.765 96.12 73.035 ;
     RECT  2.16 73.305 96.12 73.575 ;
     RECT  2.16 73.845 96.12 74.115 ;
     RECT  2.16 74.385 96.12 74.655 ;
     RECT  2.16 74.925 96.12 75.195 ;
     RECT  2.16 75.465 96.12 75.735 ;
     RECT  2.16 76.005 96.12 76.275 ;
     RECT  2.16 76.545 96.12 76.815 ;
     RECT  2.16 77.085 96.12 77.355 ;
     RECT  2.16 77.625 96.12 77.895 ;
     RECT  2.16 78.165 96.12 78.435 ;
     RECT  2.16 78.705 96.12 78.975 ;
     RECT  2.16 79.245 96.12 79.515 ;
     RECT  2.16 79.785 96.12 80.055 ;
     RECT  2.16 80.325 96.12 80.595 ;
     RECT  2.16 80.865 96.12 81.135 ;
     RECT  2.16 81.405 96.12 81.675 ;
     RECT  2.16 81.945 96.12 82.215 ;
     RECT  2.16 82.485 96.12 82.755 ;
     RECT  2.16 83.025 96.12 83.295 ;
     RECT  2.16 83.565 96.12 83.835 ;
     RECT  2.16 84.105 96.12 84.24 ;
     RECT  2.16 84.24 41.148 84.375 ;
     RECT  77.22 84.24 96.12 84.375 ;
     RECT  2.16 84.645 41.148 84.915 ;
     RECT  77.22 84.645 96.12 84.915 ;
     RECT  2.16 85.185 41.148 85.455 ;
     RECT  77.22 85.185 96.12 85.455 ;
     RECT  2.16 85.725 41.148 85.995 ;
     RECT  77.22 85.725 96.12 85.995 ;
     RECT  2.16 86.265 41.148 86.535 ;
     RECT  77.22 86.265 96.12 86.535 ;
     RECT  2.16 86.805 41.148 87.075 ;
     RECT  77.22 86.805 96.12 87.075 ;
     RECT  2.16 87.345 41.148 87.615 ;
     RECT  77.22 87.345 96.12 87.615 ;
     RECT  2.16 87.885 41.148 88.155 ;
     RECT  77.22 87.885 96.12 88.155 ;
     RECT  2.16 88.425 41.148 88.695 ;
     RECT  77.22 88.425 96.12 88.695 ;
     RECT  2.16 88.965 41.148 89.235 ;
     RECT  77.22 88.965 96.12 89.235 ;
     RECT  2.16 89.505 41.148 89.775 ;
     RECT  77.22 89.505 96.12 89.775 ;
     RECT  2.16 90.045 41.148 90.315 ;
     RECT  77.22 90.045 96.12 90.315 ;
     RECT  2.16 90.585 41.148 90.855 ;
     RECT  77.22 90.585 96.12 90.855 ;
     RECT  2.16 91.125 41.148 91.395 ;
     RECT  77.22 91.125 96.12 91.395 ;
     RECT  2.16 91.665 41.148 91.935 ;
     RECT  77.22 91.665 96.12 91.935 ;
     RECT  2.16 92.205 41.148 92.475 ;
     RECT  77.22 92.205 96.12 92.475 ;
     RECT  2.16 92.745 41.148 93.015 ;
     RECT  77.22 92.745 96.12 93.015 ;
     RECT  2.16 93.285 41.148 93.555 ;
     RECT  77.22 93.285 96.12 93.555 ;
     RECT  2.16 93.825 41.148 94.095 ;
     RECT  77.22 93.825 96.12 94.095 ;
     RECT  2.16 94.365 41.148 94.635 ;
     RECT  77.22 94.365 96.12 94.635 ;
     RECT  2.16 94.905 41.148 95.175 ;
     RECT  77.22 94.905 96.12 95.175 ;
     RECT  2.16 95.445 41.148 95.715 ;
     RECT  77.22 95.445 96.12 95.715 ;
     RECT  2.16 95.985 41.148 96.255 ;
     RECT  77.22 95.985 96.12 96.255 ;
     RECT  2.16 96.525 41.148 96.795 ;
     RECT  77.22 96.525 96.12 96.795 ;
     RECT  2.16 97.065 41.148 97.335 ;
     RECT  77.22 97.065 96.12 97.335 ;
     RECT  2.16 97.605 41.148 97.875 ;
     RECT  77.22 97.605 96.12 97.875 ;
     RECT  2.16 98.145 41.148 98.415 ;
     RECT  77.22 98.145 96.12 98.415 ;
     RECT  2.16 98.685 41.148 98.955 ;
     RECT  77.22 98.685 96.12 98.955 ;
     RECT  2.16 99.225 41.148 99.495 ;
     RECT  77.22 99.225 96.12 99.495 ;
     RECT  2.16 99.765 41.148 100.035 ;
     RECT  77.22 99.765 96.12 100.035 ;
     RECT  2.16 100.305 41.148 100.575 ;
     RECT  77.22 100.305 96.12 100.575 ;
     RECT  2.16 100.845 41.148 101.115 ;
     RECT  77.22 100.845 96.12 101.115 ;
     RECT  2.16 101.385 41.148 101.655 ;
     RECT  77.22 101.385 96.12 101.655 ;
     RECT  2.16 101.925 41.148 102.195 ;
     RECT  77.22 101.925 96.12 102.195 ;
     RECT  2.16 102.465 41.148 102.735 ;
     RECT  77.22 102.465 96.12 102.735 ;
     RECT  2.16 103.005 41.148 103.275 ;
     RECT  77.22 103.005 96.12 103.275 ;
     RECT  2.16 103.545 41.148 103.815 ;
     RECT  77.22 103.545 96.12 103.815 ;
     RECT  2.16 104.085 41.148 104.355 ;
     RECT  77.22 104.085 96.12 104.355 ;
     RECT  2.16 104.625 41.148 104.895 ;
     RECT  77.22 104.625 96.12 104.895 ;
     RECT  2.16 105.165 41.148 105.435 ;
     RECT  77.22 105.165 96.12 105.435 ;
     RECT  2.16 105.705 41.148 105.84 ;
     RECT  77.22 105.705 96.12 105.84 ;
     RECT  2.16 105.84 96.12 105.975 ;
     RECT  2.16 106.245 96.12 106.515 ;
     RECT  2.16 106.785 96.12 107.055 ;
     RECT  2.16 107.325 96.12 107.595 ;
     RECT  2.16 107.865 96.12 108.135 ;
     RECT  2.16 108.405 96.12 108.675 ;
     RECT  2.16 108.945 96.12 109.215 ;
     RECT  2.16 109.485 96.12 109.755 ;
     RECT  2.16 110.025 96.12 110.295 ;
     RECT  2.16 110.565 96.12 110.835 ;
     RECT  2.16 111.105 96.12 111.375 ;
     RECT  2.16 111.645 96.12 111.915 ;
     RECT  2.16 112.185 96.12 112.455 ;
     RECT  2.16 112.725 96.12 112.995 ;
     RECT  2.16 113.265 96.12 113.535 ;
     RECT  2.16 113.805 96.12 114.075 ;
     RECT  2.16 114.345 96.12 114.615 ;
     RECT  2.16 114.885 96.12 115.155 ;
     RECT  2.16 115.425 96.12 115.695 ;
     RECT  2.16 115.965 96.12 116.235 ;
     RECT  2.16 116.505 96.12 116.775 ;
     RECT  2.16 117.045 96.12 117.315 ;
     RECT  2.16 117.585 96.12 117.855 ;
     RECT  2.16 118.125 96.12 118.395 ;
     RECT  2.16 118.665 96.12 118.935 ;
     RECT  2.16 119.205 96.12 119.475 ;
     RECT  2.16 119.745 96.12 120.015 ;
     RECT  2.16 120.285 96.12 120.555 ;
     RECT  2.16 120.825 96.12 121.095 ;
     RECT  2.16 121.365 96.12 121.635 ;
     RECT  2.16 121.905 96.12 122.175 ;
     RECT  2.16 122.445 96.12 122.715 ;
     RECT  2.16 122.985 96.12 123.255 ;
     RECT  2.16 123.525 96.12 123.795 ;
     RECT  2.16 124.065 96.12 124.335 ;
     RECT  2.16 124.605 96.12 124.875 ;
     RECT  2.16 125.145 96.12 125.415 ;
     RECT  2.16 125.685 96.12 125.955 ;
     RECT  2.16 126.225 96.12 126.495 ;
     RECT  2.16 126.765 96.12 127.035 ;
     RECT  2.16 127.305 96.12 127.44 ;
     RECT  2.16 127.44 41.148 127.575 ;
     RECT  77.22 127.44 96.12 127.575 ;
     RECT  2.16 127.845 41.148 128.115 ;
     RECT  77.22 127.845 96.12 128.115 ;
     RECT  2.16 128.385 41.148 128.655 ;
     RECT  77.22 128.385 96.12 128.655 ;
     RECT  2.16 128.925 41.148 129.195 ;
     RECT  77.22 128.925 96.12 129.195 ;
     RECT  2.16 129.465 41.148 129.735 ;
     RECT  77.22 129.465 96.12 129.735 ;
     RECT  2.16 130.005 41.148 130.275 ;
     RECT  77.22 130.005 96.12 130.275 ;
     RECT  2.16 130.545 41.148 130.815 ;
     RECT  77.22 130.545 96.12 130.815 ;
     RECT  2.16 131.085 41.148 131.355 ;
     RECT  77.22 131.085 96.12 131.355 ;
     RECT  2.16 131.625 41.148 131.895 ;
     RECT  77.22 131.625 96.12 131.895 ;
     RECT  2.16 132.165 41.148 132.435 ;
     RECT  77.22 132.165 96.12 132.435 ;
     RECT  2.16 132.705 41.148 132.975 ;
     RECT  77.22 132.705 96.12 132.975 ;
     RECT  2.16 133.245 41.148 133.515 ;
     RECT  77.22 133.245 96.12 133.515 ;
     RECT  2.16 133.785 41.148 134.055 ;
     RECT  77.22 133.785 96.12 134.055 ;
     RECT  2.16 134.325 41.148 134.595 ;
     RECT  77.22 134.325 96.12 134.595 ;
     RECT  2.16 134.865 41.148 135.135 ;
     RECT  77.22 134.865 96.12 135.135 ;
     RECT  2.16 135.405 41.148 135.675 ;
     RECT  77.22 135.405 96.12 135.675 ;
     RECT  2.16 135.945 41.148 136.215 ;
     RECT  77.22 135.945 96.12 136.215 ;
     RECT  2.16 136.485 41.148 136.755 ;
     RECT  77.22 136.485 96.12 136.755 ;
     RECT  2.16 137.025 41.148 137.295 ;
     RECT  77.22 137.025 96.12 137.295 ;
     RECT  2.16 137.565 41.148 137.835 ;
     RECT  77.22 137.565 96.12 137.835 ;
     RECT  2.16 138.105 41.148 138.375 ;
     RECT  77.22 138.105 96.12 138.375 ;
     RECT  2.16 138.645 41.148 138.915 ;
     RECT  77.22 138.645 96.12 138.915 ;
     RECT  2.16 139.185 41.148 139.455 ;
     RECT  77.22 139.185 96.12 139.455 ;
     RECT  2.16 139.725 41.148 139.995 ;
     RECT  77.22 139.725 96.12 139.995 ;
     RECT  2.16 140.265 41.148 140.535 ;
     RECT  77.22 140.265 96.12 140.535 ;
     RECT  2.16 140.805 41.148 141.075 ;
     RECT  77.22 140.805 96.12 141.075 ;
     RECT  2.16 141.345 41.148 141.615 ;
     RECT  77.22 141.345 96.12 141.615 ;
     RECT  2.16 141.885 41.148 142.155 ;
     RECT  77.22 141.885 96.12 142.155 ;
     RECT  2.16 142.425 41.148 142.695 ;
     RECT  77.22 142.425 96.12 142.695 ;
     RECT  2.16 142.965 41.148 143.235 ;
     RECT  77.22 142.965 96.12 143.235 ;
     RECT  2.16 143.505 41.148 143.775 ;
     RECT  77.22 143.505 96.12 143.775 ;
     RECT  2.16 144.045 41.148 144.315 ;
     RECT  77.22 144.045 96.12 144.315 ;
     RECT  2.16 144.585 41.148 144.855 ;
     RECT  77.22 144.585 96.12 144.855 ;
     RECT  2.16 145.125 41.148 145.395 ;
     RECT  77.22 145.125 96.12 145.395 ;
     RECT  2.16 145.665 41.148 145.935 ;
     RECT  77.22 145.665 96.12 145.935 ;
     RECT  2.16 146.205 41.148 146.475 ;
     RECT  77.22 146.205 96.12 146.475 ;
     RECT  2.16 146.745 41.148 147.015 ;
     RECT  77.22 146.745 96.12 147.015 ;
     RECT  2.16 147.285 41.148 147.555 ;
     RECT  77.22 147.285 96.12 147.555 ;
     RECT  2.16 147.825 41.148 148.095 ;
     RECT  77.22 147.825 96.12 148.095 ;
     RECT  2.16 148.365 41.148 148.635 ;
     RECT  77.22 148.365 96.12 148.635 ;
     RECT  2.16 148.905 41.148 149.04 ;
     RECT  77.22 148.905 96.12 149.04 ;
     RECT  2.16 149.04 96.12 149.175 ;
     RECT  2.16 149.445 96.12 149.715 ;
     RECT  2.16 149.985 96.12 150.255 ;
     RECT  2.16 150.525 96.12 150.795 ;
     RECT  2.16 151.065 96.12 151.335 ;
     RECT  2.16 151.605 96.12 151.875 ;
     RECT  2.16 152.145 96.12 152.415 ;
     RECT  2.16 152.685 96.12 152.955 ;
     RECT  2.16 153.225 96.12 153.495 ;
     RECT  2.16 153.765 96.12 154.035 ;
     RECT  2.16 154.305 96.12 154.575 ;
     RECT  2.16 154.845 96.12 155.115 ;
     RECT  2.16 155.385 96.12 155.655 ;
     RECT  2.16 155.925 96.12 156.195 ;
     RECT  2.16 156.465 96.12 156.735 ;
     RECT  2.16 157.005 96.12 157.275 ;
     RECT  2.16 157.545 96.12 157.815 ;
     RECT  2.16 158.085 96.12 158.355 ;
     RECT  2.16 158.625 96.12 158.895 ;
     RECT  2.16 159.165 96.12 159.435 ;
     RECT  2.16 159.705 96.12 159.975 ;
     RECT  2.16 160.245 96.12 160.515 ;
     RECT  2.16 160.785 96.12 161.055 ;
     RECT  2.16 161.325 96.12 161.595 ;
     RECT  2.16 161.865 96.12 162.135 ;
     RECT  2.16 162.405 96.12 162.675 ;
     RECT  2.16 162.945 96.12 163.215 ;
     RECT  2.16 163.485 96.12 163.755 ;
     RECT  2.16 164.025 96.12 164.295 ;
     RECT  2.16 164.565 96.12 164.835 ;
     RECT  2.16 165.105 96.12 165.375 ;
     RECT  2.16 165.645 96.12 165.915 ;
     RECT  2.16 166.185 96.12 166.455 ;
     RECT  2.16 166.725 96.12 166.995 ;
     RECT  2.16 167.265 96.12 167.535 ;
     RECT  2.16 167.805 96.12 168.075 ;
     RECT  2.16 168.345 96.12 168.48 ;
    LAYER RVTP ;
     RECT  2.16 2.295 96.12 2.565 ;
     RECT  2.16 2.835 96.12 3.105 ;
     RECT  2.16 3.375 96.12 3.645 ;
     RECT  2.16 3.915 96.12 4.185 ;
     RECT  2.16 4.455 96.12 4.725 ;
     RECT  2.16 4.995 96.12 5.265 ;
     RECT  2.16 5.535 96.12 5.805 ;
     RECT  2.16 6.075 96.12 6.345 ;
     RECT  2.16 6.615 96.12 6.885 ;
     RECT  2.16 7.155 96.12 7.425 ;
     RECT  2.16 7.695 96.12 7.965 ;
     RECT  2.16 8.235 96.12 8.505 ;
     RECT  2.16 8.775 96.12 9.045 ;
     RECT  2.16 9.315 96.12 9.585 ;
     RECT  2.16 9.855 96.12 10.125 ;
     RECT  2.16 10.395 96.12 10.665 ;
     RECT  2.16 10.935 96.12 11.205 ;
     RECT  2.16 11.475 96.12 11.745 ;
     RECT  2.16 12.015 96.12 12.285 ;
     RECT  2.16 12.555 96.12 12.825 ;
     RECT  2.16 13.095 96.12 13.365 ;
     RECT  2.16 13.635 96.12 13.905 ;
     RECT  2.16 14.175 96.12 14.445 ;
     RECT  2.16 14.715 96.12 14.985 ;
     RECT  2.16 15.255 96.12 15.525 ;
     RECT  2.16 15.795 96.12 16.065 ;
     RECT  2.16 16.335 96.12 16.605 ;
     RECT  2.16 16.875 96.12 17.145 ;
     RECT  2.16 17.415 96.12 17.685 ;
     RECT  2.16 17.955 96.12 18.225 ;
     RECT  2.16 18.495 96.12 18.765 ;
     RECT  2.16 19.035 96.12 19.305 ;
     RECT  2.16 19.575 96.12 19.845 ;
     RECT  2.16 20.115 96.12 20.385 ;
     RECT  2.16 20.655 96.12 20.925 ;
     RECT  2.16 21.195 96.12 21.465 ;
     RECT  2.16 21.735 96.12 22.005 ;
     RECT  2.16 22.275 96.12 22.545 ;
     RECT  2.16 22.815 96.12 23.085 ;
     RECT  2.16 23.355 96.12 23.625 ;
     RECT  2.16 23.895 96.12 24.165 ;
     RECT  2.16 24.435 96.12 24.705 ;
     RECT  2.16 24.975 96.12 25.245 ;
     RECT  2.16 25.515 96.12 25.785 ;
     RECT  2.16 26.055 96.12 26.325 ;
     RECT  2.16 26.595 96.12 26.865 ;
     RECT  2.16 27.135 96.12 27.405 ;
     RECT  2.16 27.675 96.12 27.945 ;
     RECT  2.16 28.215 96.12 28.485 ;
     RECT  2.16 28.755 96.12 29.025 ;
     RECT  2.16 29.295 96.12 29.565 ;
     RECT  2.16 29.835 96.12 30.105 ;
     RECT  2.16 30.375 96.12 30.645 ;
     RECT  2.16 30.915 96.12 31.185 ;
     RECT  2.16 31.455 96.12 31.725 ;
     RECT  2.16 31.995 96.12 32.265 ;
     RECT  2.16 32.535 96.12 32.805 ;
     RECT  2.16 33.075 96.12 33.345 ;
     RECT  2.16 33.615 96.12 33.885 ;
     RECT  2.16 34.155 96.12 34.425 ;
     RECT  2.16 34.695 96.12 34.965 ;
     RECT  2.16 35.235 96.12 35.505 ;
     RECT  2.16 35.775 96.12 36.045 ;
     RECT  2.16 36.315 96.12 36.585 ;
     RECT  2.16 36.855 96.12 37.125 ;
     RECT  2.16 37.395 96.12 37.665 ;
     RECT  2.16 37.935 96.12 38.205 ;
     RECT  2.16 38.475 96.12 38.745 ;
     RECT  2.16 39.015 96.12 39.285 ;
     RECT  2.16 39.555 96.12 39.825 ;
     RECT  2.16 40.095 96.12 40.365 ;
     RECT  2.16 40.635 96.12 40.905 ;
     RECT  2.16 41.175 41.148 41.445 ;
     RECT  77.22 41.175 96.12 41.445 ;
     RECT  2.16 41.715 41.148 41.985 ;
     RECT  77.22 41.715 96.12 41.985 ;
     RECT  2.16 42.255 41.148 42.525 ;
     RECT  77.22 42.255 96.12 42.525 ;
     RECT  2.16 42.795 41.148 43.065 ;
     RECT  77.22 42.795 96.12 43.065 ;
     RECT  2.16 43.335 41.148 43.605 ;
     RECT  77.22 43.335 96.12 43.605 ;
     RECT  2.16 43.875 41.148 44.145 ;
     RECT  77.22 43.875 96.12 44.145 ;
     RECT  2.16 44.415 41.148 44.685 ;
     RECT  77.22 44.415 96.12 44.685 ;
     RECT  2.16 44.955 41.148 45.225 ;
     RECT  77.22 44.955 96.12 45.225 ;
     RECT  2.16 45.495 41.148 45.765 ;
     RECT  77.22 45.495 96.12 45.765 ;
     RECT  2.16 46.035 41.148 46.305 ;
     RECT  77.22 46.035 96.12 46.305 ;
     RECT  2.16 46.575 41.148 46.845 ;
     RECT  77.22 46.575 96.12 46.845 ;
     RECT  2.16 47.115 41.148 47.385 ;
     RECT  77.22 47.115 96.12 47.385 ;
     RECT  2.16 47.655 41.148 47.925 ;
     RECT  77.22 47.655 96.12 47.925 ;
     RECT  2.16 48.195 41.148 48.465 ;
     RECT  77.22 48.195 96.12 48.465 ;
     RECT  2.16 48.735 41.148 49.005 ;
     RECT  77.22 48.735 96.12 49.005 ;
     RECT  2.16 49.275 41.148 49.545 ;
     RECT  77.22 49.275 96.12 49.545 ;
     RECT  2.16 49.815 41.148 50.085 ;
     RECT  77.22 49.815 96.12 50.085 ;
     RECT  2.16 50.355 41.148 50.625 ;
     RECT  77.22 50.355 96.12 50.625 ;
     RECT  2.16 50.895 41.148 51.165 ;
     RECT  77.22 50.895 96.12 51.165 ;
     RECT  2.16 51.435 41.148 51.705 ;
     RECT  77.22 51.435 96.12 51.705 ;
     RECT  2.16 51.975 41.148 52.245 ;
     RECT  77.22 51.975 96.12 52.245 ;
     RECT  2.16 52.515 41.148 52.785 ;
     RECT  77.22 52.515 96.12 52.785 ;
     RECT  2.16 53.055 41.148 53.325 ;
     RECT  77.22 53.055 96.12 53.325 ;
     RECT  2.16 53.595 41.148 53.865 ;
     RECT  77.22 53.595 96.12 53.865 ;
     RECT  2.16 54.135 41.148 54.405 ;
     RECT  77.22 54.135 96.12 54.405 ;
     RECT  2.16 54.675 41.148 54.945 ;
     RECT  77.22 54.675 96.12 54.945 ;
     RECT  2.16 55.215 41.148 55.485 ;
     RECT  77.22 55.215 96.12 55.485 ;
     RECT  2.16 55.755 41.148 56.025 ;
     RECT  77.22 55.755 96.12 56.025 ;
     RECT  2.16 56.295 41.148 56.565 ;
     RECT  77.22 56.295 96.12 56.565 ;
     RECT  2.16 56.835 41.148 57.105 ;
     RECT  77.22 56.835 96.12 57.105 ;
     RECT  2.16 57.375 41.148 57.645 ;
     RECT  77.22 57.375 96.12 57.645 ;
     RECT  2.16 57.915 41.148 58.185 ;
     RECT  77.22 57.915 96.12 58.185 ;
     RECT  2.16 58.455 41.148 58.725 ;
     RECT  77.22 58.455 96.12 58.725 ;
     RECT  2.16 58.995 41.148 59.265 ;
     RECT  77.22 58.995 96.12 59.265 ;
     RECT  2.16 59.535 41.148 59.805 ;
     RECT  77.22 59.535 96.12 59.805 ;
     RECT  2.16 60.075 41.148 60.345 ;
     RECT  77.22 60.075 96.12 60.345 ;
     RECT  2.16 60.615 41.148 60.885 ;
     RECT  77.22 60.615 96.12 60.885 ;
     RECT  2.16 61.155 41.148 61.425 ;
     RECT  77.22 61.155 96.12 61.425 ;
     RECT  2.16 61.695 41.148 61.965 ;
     RECT  77.22 61.695 96.12 61.965 ;
     RECT  2.16 62.235 41.148 62.505 ;
     RECT  77.22 62.235 96.12 62.505 ;
     RECT  2.16 62.775 96.12 63.045 ;
     RECT  2.16 63.315 96.12 63.585 ;
     RECT  2.16 63.855 96.12 64.125 ;
     RECT  2.16 64.395 96.12 64.665 ;
     RECT  2.16 64.935 96.12 65.205 ;
     RECT  2.16 65.475 96.12 65.745 ;
     RECT  2.16 66.015 96.12 66.285 ;
     RECT  2.16 66.555 96.12 66.825 ;
     RECT  2.16 67.095 96.12 67.365 ;
     RECT  2.16 67.635 96.12 67.905 ;
     RECT  2.16 68.175 96.12 68.445 ;
     RECT  2.16 68.715 96.12 68.985 ;
     RECT  2.16 69.255 96.12 69.525 ;
     RECT  2.16 69.795 96.12 70.065 ;
     RECT  2.16 70.335 96.12 70.605 ;
     RECT  2.16 70.875 96.12 71.145 ;
     RECT  2.16 71.415 96.12 71.685 ;
     RECT  2.16 71.955 96.12 72.225 ;
     RECT  2.16 72.495 96.12 72.765 ;
     RECT  2.16 73.035 96.12 73.305 ;
     RECT  2.16 73.575 96.12 73.845 ;
     RECT  2.16 74.115 96.12 74.385 ;
     RECT  2.16 74.655 96.12 74.925 ;
     RECT  2.16 75.195 96.12 75.465 ;
     RECT  2.16 75.735 96.12 76.005 ;
     RECT  2.16 76.275 96.12 76.545 ;
     RECT  2.16 76.815 96.12 77.085 ;
     RECT  2.16 77.355 96.12 77.625 ;
     RECT  2.16 77.895 96.12 78.165 ;
     RECT  2.16 78.435 96.12 78.705 ;
     RECT  2.16 78.975 96.12 79.245 ;
     RECT  2.16 79.515 96.12 79.785 ;
     RECT  2.16 80.055 96.12 80.325 ;
     RECT  2.16 80.595 96.12 80.865 ;
     RECT  2.16 81.135 96.12 81.405 ;
     RECT  2.16 81.675 96.12 81.945 ;
     RECT  2.16 82.215 96.12 82.485 ;
     RECT  2.16 82.755 96.12 83.025 ;
     RECT  2.16 83.295 96.12 83.565 ;
     RECT  2.16 83.835 96.12 84.105 ;
     RECT  2.16 84.375 41.148 84.645 ;
     RECT  77.22 84.375 96.12 84.645 ;
     RECT  2.16 84.915 41.148 85.185 ;
     RECT  77.22 84.915 96.12 85.185 ;
     RECT  2.16 85.455 41.148 85.725 ;
     RECT  77.22 85.455 96.12 85.725 ;
     RECT  2.16 85.995 41.148 86.265 ;
     RECT  77.22 85.995 96.12 86.265 ;
     RECT  2.16 86.535 41.148 86.805 ;
     RECT  77.22 86.535 96.12 86.805 ;
     RECT  2.16 87.075 41.148 87.345 ;
     RECT  77.22 87.075 96.12 87.345 ;
     RECT  2.16 87.615 41.148 87.885 ;
     RECT  77.22 87.615 96.12 87.885 ;
     RECT  2.16 88.155 41.148 88.425 ;
     RECT  77.22 88.155 96.12 88.425 ;
     RECT  2.16 88.695 41.148 88.965 ;
     RECT  77.22 88.695 96.12 88.965 ;
     RECT  2.16 89.235 41.148 89.505 ;
     RECT  77.22 89.235 96.12 89.505 ;
     RECT  2.16 89.775 41.148 90.045 ;
     RECT  77.22 89.775 96.12 90.045 ;
     RECT  2.16 90.315 41.148 90.585 ;
     RECT  77.22 90.315 96.12 90.585 ;
     RECT  2.16 90.855 41.148 91.125 ;
     RECT  77.22 90.855 96.12 91.125 ;
     RECT  2.16 91.395 41.148 91.665 ;
     RECT  77.22 91.395 96.12 91.665 ;
     RECT  2.16 91.935 41.148 92.205 ;
     RECT  77.22 91.935 96.12 92.205 ;
     RECT  2.16 92.475 41.148 92.745 ;
     RECT  77.22 92.475 96.12 92.745 ;
     RECT  2.16 93.015 41.148 93.285 ;
     RECT  77.22 93.015 96.12 93.285 ;
     RECT  2.16 93.555 41.148 93.825 ;
     RECT  77.22 93.555 96.12 93.825 ;
     RECT  2.16 94.095 41.148 94.365 ;
     RECT  77.22 94.095 96.12 94.365 ;
     RECT  2.16 94.635 41.148 94.905 ;
     RECT  77.22 94.635 96.12 94.905 ;
     RECT  2.16 95.175 41.148 95.445 ;
     RECT  77.22 95.175 96.12 95.445 ;
     RECT  2.16 95.715 41.148 95.985 ;
     RECT  77.22 95.715 96.12 95.985 ;
     RECT  2.16 96.255 41.148 96.525 ;
     RECT  77.22 96.255 96.12 96.525 ;
     RECT  2.16 96.795 41.148 97.065 ;
     RECT  77.22 96.795 96.12 97.065 ;
     RECT  2.16 97.335 41.148 97.605 ;
     RECT  77.22 97.335 96.12 97.605 ;
     RECT  2.16 97.875 41.148 98.145 ;
     RECT  77.22 97.875 96.12 98.145 ;
     RECT  2.16 98.415 41.148 98.685 ;
     RECT  77.22 98.415 96.12 98.685 ;
     RECT  2.16 98.955 41.148 99.225 ;
     RECT  77.22 98.955 96.12 99.225 ;
     RECT  2.16 99.495 41.148 99.765 ;
     RECT  77.22 99.495 96.12 99.765 ;
     RECT  2.16 100.035 41.148 100.305 ;
     RECT  77.22 100.035 96.12 100.305 ;
     RECT  2.16 100.575 41.148 100.845 ;
     RECT  77.22 100.575 96.12 100.845 ;
     RECT  2.16 101.115 41.148 101.385 ;
     RECT  77.22 101.115 96.12 101.385 ;
     RECT  2.16 101.655 41.148 101.925 ;
     RECT  77.22 101.655 96.12 101.925 ;
     RECT  2.16 102.195 41.148 102.465 ;
     RECT  77.22 102.195 96.12 102.465 ;
     RECT  2.16 102.735 41.148 103.005 ;
     RECT  77.22 102.735 96.12 103.005 ;
     RECT  2.16 103.275 41.148 103.545 ;
     RECT  77.22 103.275 96.12 103.545 ;
     RECT  2.16 103.815 41.148 104.085 ;
     RECT  77.22 103.815 96.12 104.085 ;
     RECT  2.16 104.355 41.148 104.625 ;
     RECT  77.22 104.355 96.12 104.625 ;
     RECT  2.16 104.895 41.148 105.165 ;
     RECT  77.22 104.895 96.12 105.165 ;
     RECT  2.16 105.435 41.148 105.705 ;
     RECT  77.22 105.435 96.12 105.705 ;
     RECT  2.16 105.975 96.12 106.245 ;
     RECT  2.16 106.515 96.12 106.785 ;
     RECT  2.16 107.055 96.12 107.325 ;
     RECT  2.16 107.595 96.12 107.865 ;
     RECT  2.16 108.135 96.12 108.405 ;
     RECT  2.16 108.675 96.12 108.945 ;
     RECT  2.16 109.215 96.12 109.485 ;
     RECT  2.16 109.755 96.12 110.025 ;
     RECT  2.16 110.295 96.12 110.565 ;
     RECT  2.16 110.835 96.12 111.105 ;
     RECT  2.16 111.375 96.12 111.645 ;
     RECT  2.16 111.915 96.12 112.185 ;
     RECT  2.16 112.455 96.12 112.725 ;
     RECT  2.16 112.995 96.12 113.265 ;
     RECT  2.16 113.535 96.12 113.805 ;
     RECT  2.16 114.075 96.12 114.345 ;
     RECT  2.16 114.615 96.12 114.885 ;
     RECT  2.16 115.155 96.12 115.425 ;
     RECT  2.16 115.695 96.12 115.965 ;
     RECT  2.16 116.235 96.12 116.505 ;
     RECT  2.16 116.775 96.12 117.045 ;
     RECT  2.16 117.315 96.12 117.585 ;
     RECT  2.16 117.855 96.12 118.125 ;
     RECT  2.16 118.395 96.12 118.665 ;
     RECT  2.16 118.935 96.12 119.205 ;
     RECT  2.16 119.475 96.12 119.745 ;
     RECT  2.16 120.015 96.12 120.285 ;
     RECT  2.16 120.555 96.12 120.825 ;
     RECT  2.16 121.095 96.12 121.365 ;
     RECT  2.16 121.635 96.12 121.905 ;
     RECT  2.16 122.175 96.12 122.445 ;
     RECT  2.16 122.715 96.12 122.985 ;
     RECT  2.16 123.255 96.12 123.525 ;
     RECT  2.16 123.795 96.12 124.065 ;
     RECT  2.16 124.335 96.12 124.605 ;
     RECT  2.16 124.875 96.12 125.145 ;
     RECT  2.16 125.415 96.12 125.685 ;
     RECT  2.16 125.955 96.12 126.225 ;
     RECT  2.16 126.495 96.12 126.765 ;
     RECT  2.16 127.035 96.12 127.305 ;
     RECT  2.16 127.575 41.148 127.845 ;
     RECT  77.22 127.575 96.12 127.845 ;
     RECT  2.16 128.115 41.148 128.385 ;
     RECT  77.22 128.115 96.12 128.385 ;
     RECT  2.16 128.655 41.148 128.925 ;
     RECT  77.22 128.655 96.12 128.925 ;
     RECT  2.16 129.195 41.148 129.465 ;
     RECT  77.22 129.195 96.12 129.465 ;
     RECT  2.16 129.735 41.148 130.005 ;
     RECT  77.22 129.735 96.12 130.005 ;
     RECT  2.16 130.275 41.148 130.545 ;
     RECT  77.22 130.275 96.12 130.545 ;
     RECT  2.16 130.815 41.148 131.085 ;
     RECT  77.22 130.815 96.12 131.085 ;
     RECT  2.16 131.355 41.148 131.625 ;
     RECT  77.22 131.355 96.12 131.625 ;
     RECT  2.16 131.895 41.148 132.165 ;
     RECT  77.22 131.895 96.12 132.165 ;
     RECT  2.16 132.435 41.148 132.705 ;
     RECT  77.22 132.435 96.12 132.705 ;
     RECT  2.16 132.975 41.148 133.245 ;
     RECT  77.22 132.975 96.12 133.245 ;
     RECT  2.16 133.515 41.148 133.785 ;
     RECT  77.22 133.515 96.12 133.785 ;
     RECT  2.16 134.055 41.148 134.325 ;
     RECT  77.22 134.055 96.12 134.325 ;
     RECT  2.16 134.595 41.148 134.865 ;
     RECT  77.22 134.595 96.12 134.865 ;
     RECT  2.16 135.135 41.148 135.405 ;
     RECT  77.22 135.135 96.12 135.405 ;
     RECT  2.16 135.675 41.148 135.945 ;
     RECT  77.22 135.675 96.12 135.945 ;
     RECT  2.16 136.215 41.148 136.485 ;
     RECT  77.22 136.215 96.12 136.485 ;
     RECT  2.16 136.755 41.148 137.025 ;
     RECT  77.22 136.755 96.12 137.025 ;
     RECT  2.16 137.295 41.148 137.565 ;
     RECT  77.22 137.295 96.12 137.565 ;
     RECT  2.16 137.835 41.148 138.105 ;
     RECT  77.22 137.835 96.12 138.105 ;
     RECT  2.16 138.375 41.148 138.645 ;
     RECT  77.22 138.375 96.12 138.645 ;
     RECT  2.16 138.915 41.148 139.185 ;
     RECT  77.22 138.915 96.12 139.185 ;
     RECT  2.16 139.455 41.148 139.725 ;
     RECT  77.22 139.455 96.12 139.725 ;
     RECT  2.16 139.995 41.148 140.265 ;
     RECT  77.22 139.995 96.12 140.265 ;
     RECT  2.16 140.535 41.148 140.805 ;
     RECT  77.22 140.535 96.12 140.805 ;
     RECT  2.16 141.075 41.148 141.345 ;
     RECT  77.22 141.075 96.12 141.345 ;
     RECT  2.16 141.615 41.148 141.885 ;
     RECT  77.22 141.615 96.12 141.885 ;
     RECT  2.16 142.155 41.148 142.425 ;
     RECT  77.22 142.155 96.12 142.425 ;
     RECT  2.16 142.695 41.148 142.965 ;
     RECT  77.22 142.695 96.12 142.965 ;
     RECT  2.16 143.235 41.148 143.505 ;
     RECT  77.22 143.235 96.12 143.505 ;
     RECT  2.16 143.775 41.148 144.045 ;
     RECT  77.22 143.775 96.12 144.045 ;
     RECT  2.16 144.315 41.148 144.585 ;
     RECT  77.22 144.315 96.12 144.585 ;
     RECT  2.16 144.855 41.148 145.125 ;
     RECT  77.22 144.855 96.12 145.125 ;
     RECT  2.16 145.395 41.148 145.665 ;
     RECT  77.22 145.395 96.12 145.665 ;
     RECT  2.16 145.935 41.148 146.205 ;
     RECT  77.22 145.935 96.12 146.205 ;
     RECT  2.16 146.475 41.148 146.745 ;
     RECT  77.22 146.475 96.12 146.745 ;
     RECT  2.16 147.015 41.148 147.285 ;
     RECT  77.22 147.015 96.12 147.285 ;
     RECT  2.16 147.555 41.148 147.825 ;
     RECT  77.22 147.555 96.12 147.825 ;
     RECT  2.16 148.095 41.148 148.365 ;
     RECT  77.22 148.095 96.12 148.365 ;
     RECT  2.16 148.635 41.148 148.905 ;
     RECT  77.22 148.635 96.12 148.905 ;
     RECT  2.16 149.175 96.12 149.445 ;
     RECT  2.16 149.715 96.12 149.985 ;
     RECT  2.16 150.255 96.12 150.525 ;
     RECT  2.16 150.795 96.12 151.065 ;
     RECT  2.16 151.335 96.12 151.605 ;
     RECT  2.16 151.875 96.12 152.145 ;
     RECT  2.16 152.415 96.12 152.685 ;
     RECT  2.16 152.955 96.12 153.225 ;
     RECT  2.16 153.495 96.12 153.765 ;
     RECT  2.16 154.035 96.12 154.305 ;
     RECT  2.16 154.575 96.12 154.845 ;
     RECT  2.16 155.115 96.12 155.385 ;
     RECT  2.16 155.655 96.12 155.925 ;
     RECT  2.16 156.195 96.12 156.465 ;
     RECT  2.16 156.735 96.12 157.005 ;
     RECT  2.16 157.275 96.12 157.545 ;
     RECT  2.16 157.815 96.12 158.085 ;
     RECT  2.16 158.355 96.12 158.625 ;
     RECT  2.16 158.895 96.12 159.165 ;
     RECT  2.16 159.435 96.12 159.705 ;
     RECT  2.16 159.975 96.12 160.245 ;
     RECT  2.16 160.515 96.12 160.785 ;
     RECT  2.16 161.055 96.12 161.325 ;
     RECT  2.16 161.595 96.12 161.865 ;
     RECT  2.16 162.135 96.12 162.405 ;
     RECT  2.16 162.675 96.12 162.945 ;
     RECT  2.16 163.215 96.12 163.485 ;
     RECT  2.16 163.755 96.12 164.025 ;
     RECT  2.16 164.295 96.12 164.565 ;
     RECT  2.16 164.835 96.12 165.105 ;
     RECT  2.16 165.375 96.12 165.645 ;
     RECT  2.16 165.915 96.12 166.185 ;
     RECT  2.16 166.455 96.12 166.725 ;
     RECT  2.16 166.995 96.12 167.265 ;
     RECT  2.16 167.535 96.12 167.805 ;
     RECT  2.16 168.075 96.12 168.345 ;
    LAYER M1 ;
     RECT  2.16 2.151 96.12 41.049 ;
     RECT  43.2 43.2 75.192 60.504 ;
     RECT  2.16 41.049 41.148 62.631 ;
     RECT  77.22 41.049 96.12 62.631 ;
     RECT  2.16 62.631 96.12 84.249 ;
     RECT  43.2 86.4 75.192 103.704 ;
     RECT  2.16 84.249 41.148 105.831 ;
     RECT  77.22 84.249 96.12 105.831 ;
     RECT  2.16 105.831 96.12 127.449 ;
     RECT  43.2 129.6 75.192 146.904 ;
     RECT  2.16 127.449 41.148 149.031 ;
     RECT  77.22 127.449 96.12 149.031 ;
     RECT  2.16 149.031 96.12 168.489 ;
    LAYER M2 ;
     RECT  0.103 31.806 0.535 34.146 ;
     RECT  0.103 43.308 0.535 44.946 ;
     RECT  0.103 120.636 1.147 122.274 ;
     RECT  0.103 118.206 2.155 118.224 ;
     RECT  0.535 31.806 2.16 34.524 ;
     RECT  0.103 35.316 2.16 35.334 ;
     RECT  0.535 40.716 2.16 40.734 ;
     RECT  0.535 42.606 2.16 44.946 ;
     RECT  0.103 74.466 2.16 75.564 ;
     RECT  0.103 76.896 2.16 77.454 ;
     RECT  0.103 78.516 2.16 78.534 ;
     RECT  0.535 85.806 2.16 85.824 ;
     RECT  0.103 86.616 2.16 88.794 ;
     RECT  2.155 118.206 2.16 118.314 ;
     RECT  1.147 120.366 2.16 122.274 ;
     RECT  0.535 128.898 2.16 128.916 ;
     RECT  0.103 129.816 2.16 131.274 ;
     RECT  37.831 170.586 37.903 170.604 ;
     RECT  37.903 170.514 38.003 170.604 ;
     RECT  38.003 170.586 38.471 170.604 ;
     RECT  2.16 2.151 41.148 168.489 ;
     RECT  41.148 44.226 41.315 54.504 ;
     RECT  41.148 135.072 41.315 142.416 ;
     RECT  41.148 130.284 41.351 130.806 ;
     RECT  41.148 145.026 41.351 145.044 ;
     RECT  41.148 60.516 41.387 61.614 ;
     RECT  41.148 96.876 41.387 100.224 ;
     RECT  41.148 101.016 41.495 101.034 ;
     RECT  41.387 96.921 41.567 100.224 ;
     RECT  41.315 44.226 41.639 54.054 ;
     RECT  41.148 87.156 41.639 95.904 ;
     RECT  41.639 46.242 41.711 49.266 ;
     RECT  41.639 87.156 41.747 92.844 ;
     RECT  41.148 131.562 41.855 132.228 ;
     RECT  41.148 128.934 41.891 129.294 ;
     RECT  41.315 137.646 41.891 142.416 ;
     RECT  41.148 103.896 41.899 104.688 ;
     RECT  41.148 55.386 41.927 56.664 ;
     RECT  41.351 130.788 41.927 130.806 ;
     RECT  41.567 97.686 41.963 100.224 ;
     RECT  41.855 132.21 41.963 132.228 ;
     RECT  41.899 103.788 41.971 104.688 ;
     RECT  41.891 137.646 42.071 142.254 ;
     RECT  41.148 105.831 42.079 127.449 ;
     RECT  42.071 137.646 42.107 139.374 ;
     RECT  41.639 50.058 42.143 54.054 ;
     RECT  41.567 96.921 42.143 96.939 ;
     RECT  41.963 97.686 42.179 100.026 ;
     RECT  42.107 137.646 42.179 138.834 ;
     RECT  42.071 140.436 42.179 142.254 ;
     RECT  41.711 46.242 42.215 46.872 ;
     RECT  42.143 50.058 42.215 53.514 ;
     RECT  41.747 88.902 42.215 92.844 ;
     RECT  41.315 135.072 42.215 136.584 ;
     RECT  41.639 44.226 42.251 44.946 ;
     RECT  42.215 135.378 42.251 135.396 ;
     RECT  41.711 47.736 42.287 49.266 ;
     RECT  42.179 97.686 42.395 97.704 ;
     RECT  42.179 98.766 42.431 100.026 ;
     RECT  42.079 105.831 42.439 127.494 ;
     RECT  42.215 51.786 42.467 53.514 ;
     RECT  41.639 93.636 42.467 95.904 ;
     RECT  42.179 141.084 42.467 142.254 ;
     RECT  42.439 105.831 42.511 128.178 ;
     RECT  41.148 147.096 42.511 148.014 ;
     RECT  42.511 105.786 42.547 128.178 ;
     RECT  41.148 62.631 42.583 84.249 ;
     RECT  41.891 129.24 42.583 129.294 ;
     RECT  42.547 105.642 42.655 128.178 ;
     RECT  42.655 105.642 42.683 128.259 ;
     RECT  42.683 128.241 42.899 128.259 ;
     RECT  41.148 43.146 42.979 43.164 ;
     RECT  41.927 55.386 43.015 56.214 ;
     RECT  42.979 42.768 43.079 43.164 ;
     RECT  41.148 149.031 43.087 168.489 ;
     RECT  43.079 42.84 43.151 43.164 ;
     RECT  43.087 148.761 43.187 168.489 ;
     RECT  43.151 43.146 43.2 43.164 ;
     RECT  42.251 44.658 43.2 44.946 ;
     RECT  42.215 46.548 43.2 46.566 ;
     RECT  42.287 47.736 43.2 48.384 ;
     RECT  42.287 49.248 43.2 49.266 ;
     RECT  42.215 50.058 43.2 50.076 ;
     RECT  42.467 52.056 43.2 53.514 ;
     RECT  43.015 54.684 43.2 56.214 ;
     RECT  41.387 60.552 43.2 61.614 ;
     RECT  41.747 87.156 43.2 87.876 ;
     RECT  42.215 89.406 43.2 89.424 ;
     RECT  42.215 90.288 43.2 91.926 ;
     RECT  42.215 92.826 43.2 92.844 ;
     RECT  42.467 93.636 43.2 93.924 ;
     RECT  42.467 94.716 43.2 95.904 ;
     RECT  42.431 99.396 43.2 100.026 ;
     RECT  41.971 103.752 43.2 104.688 ;
     RECT  42.583 129.24 43.2 129.384 ;
     RECT  42.295 130.446 43.2 130.536 ;
     RECT  41.148 133.29 43.2 134.01 ;
     RECT  42.215 136.188 43.2 136.584 ;
     RECT  42.179 138.186 43.2 138.366 ;
     RECT  42.467 141.156 43.2 142.254 ;
     RECT  42.511 147.06 43.2 148.014 ;
     RECT  42.683 105.642 43.367 127.494 ;
     RECT  43.2 86.4 48.559 104.688 ;
     RECT  43.367 105.642 48.559 127.449 ;
     RECT  43.2 43.146 49.315 61.614 ;
     RECT  42.583 62.442 49.315 84.249 ;
     RECT  43.187 148.95 50.503 168.489 ;
     RECT  43.2 129.24 50.791 148.014 ;
     RECT  50.503 148.914 50.791 168.489 ;
     RECT  41.148 85.23 65.147 85.248 ;
     RECT  49.315 43.146 70.699 84.249 ;
     RECT  48.559 86.4 74.731 127.449 ;
     RECT  74.731 86.4 75.091 127.566 ;
     RECT  70.699 43.146 75.127 84.294 ;
     RECT  75.127 42.768 75.192 84.294 ;
     RECT  75.091 86.076 75.192 127.566 ;
     RECT  50.791 129.24 75.192 168.489 ;
     RECT  41.148 2.151 75.235 41.049 ;
     RECT  75.192 60.552 75.235 84.294 ;
     RECT  75.192 129.24 75.235 129.834 ;
     RECT  75.235 2.151 75.271 41.13 ;
     RECT  75.235 60.552 75.271 84.33 ;
     RECT  75.192 58.698 75.335 58.716 ;
     RECT  75.192 86.076 75.335 87.264 ;
     RECT  75.192 91.098 75.335 91.188 ;
     RECT  75.192 142.506 75.335 142.524 ;
     RECT  75.271 2.151 75.371 41.202 ;
     RECT  75.271 60.552 75.371 84.942 ;
     RECT  75.192 130.788 75.371 131.769 ;
     RECT  75.192 146.106 75.371 168.489 ;
     RECT  75.192 42.768 75.443 43.164 ;
     RECT  75.371 60.552 75.443 84.438 ;
     RECT  75.335 91.098 75.443 91.116 ;
     RECT  75.192 132.786 75.515 133.848 ;
     RECT  75.192 44.856 75.551 45.144 ;
     RECT  75.443 60.552 75.551 84.366 ;
     RECT  75.335 86.346 75.587 87.264 ;
     RECT  75.587 86.85 75.695 87.264 ;
     RECT  75.192 88.326 75.803 88.794 ;
     RECT  75.192 139.932 75.803 141.336 ;
     RECT  75.235 128.826 75.991 129.834 ;
     RECT  75.371 130.788 75.991 131.454 ;
     RECT  75.192 96.534 76.099 98.91 ;
     RECT  76.099 55.494 76.171 55.512 ;
     RECT  76.099 85.194 76.171 85.212 ;
     RECT  75.192 135.072 76.351 137.25 ;
     RECT  75.192 48.816 76.387 49.464 ;
     RECT  75.192 52.83 76.387 54.63 ;
     RECT  75.192 94.032 76.387 94.05 ;
     RECT  76.099 96.534 76.387 99.45 ;
     RECT  75.515 133.758 76.387 133.848 ;
     RECT  76.351 134.946 76.387 137.25 ;
     RECT  75.192 139.158 76.387 139.176 ;
     RECT  76.387 92.79 76.423 95.364 ;
     RECT  76.387 96.192 76.423 99.45 ;
     RECT  75.443 43.146 76.639 43.164 ;
     RECT  76.171 55.494 76.639 56.088 ;
     RECT  76.387 142.866 76.639 142.884 ;
     RECT  76.639 55.494 76.675 56.124 ;
     RECT  76.387 134.676 76.675 139.176 ;
     RECT  75.803 139.932 76.675 141.264 ;
     RECT  76.387 48.816 76.891 54.63 ;
     RECT  76.423 92.79 76.927 99.45 ;
     RECT  76.891 48.276 76.963 54.63 ;
     RECT  76.675 55.494 76.963 56.484 ;
     RECT  76.387 133.596 76.963 133.848 ;
     RECT  76.675 134.676 76.963 141.264 ;
     RECT  75.371 2.151 77.22 41.049 ;
     RECT  76.639 43.146 77.22 43.29 ;
     RECT  75.551 45.126 77.22 45.144 ;
     RECT  75.192 46.656 77.22 46.944 ;
     RECT  76.963 48.276 77.22 56.484 ;
     RECT  75.551 60.552 77.22 84.249 ;
     RECT  76.171 85.194 77.22 85.284 ;
     RECT  75.695 86.85 77.22 87.174 ;
     RECT  75.803 88.326 77.22 88.344 ;
     RECT  76.639 89.856 77.22 89.874 ;
     RECT  76.351 91.17 77.22 91.188 ;
     RECT  76.927 92.016 77.22 99.45 ;
     RECT  76.639 100.512 77.22 100.53 ;
     RECT  76.171 101.736 77.22 101.754 ;
     RECT  75.192 102.906 77.22 127.566 ;
     RECT  75.991 128.826 77.22 131.454 ;
     RECT  75.515 132.786 77.22 132.804 ;
     RECT  76.963 133.596 77.22 141.264 ;
     RECT  76.639 142.326 77.22 142.884 ;
     RECT  76.711 144.252 77.22 144.27 ;
     RECT  75.371 146.106 77.22 146.124 ;
     RECT  75.371 147.06 77.22 168.489 ;
     RECT  77.22 2.151 96.12 168.489 ;
     RECT  96.12 52.56 96.935 52.578 ;
     RECT  96.12 96.498 97.439 97.056 ;
     RECT  96.12 100.548 97.439 100.836 ;
     RECT  96.12 39.798 97.475 40.626 ;
     RECT  96.12 41.418 97.475 42.246 ;
     RECT  96.12 54.108 97.475 54.666 ;
     RECT  96.12 81.918 97.475 83.556 ;
     RECT  96.12 84.348 97.475 84.366 ;
     RECT  97.439 96.768 97.475 97.056 ;
     RECT  96.12 97.848 97.475 97.866 ;
     RECT  96.12 99.738 97.475 99.756 ;
     RECT  97.439 100.818 97.475 100.836 ;
     RECT  96.12 139.698 97.475 139.716 ;
     RECT  96.12 140.508 97.475 140.526 ;
     RECT  96.12 141.588 97.475 141.876 ;
     RECT  96.12 142.938 97.475 142.956 ;
     RECT  98.167 99.666 98.267 99.684 ;
     RECT  98.167 140.706 98.267 140.724 ;
    LAYER M3 ;
     RECT  2.415 2.143 2.505 2.413 ;
     RECT  5.115 2.143 5.205 2.413 ;
     RECT  7.815 2.143 7.905 2.413 ;
     RECT  10.515 2.143 10.605 2.413 ;
     RECT  13.215 2.143 13.305 2.413 ;
     RECT  15.915 2.143 16.005 2.413 ;
     RECT  18.615 2.143 18.705 2.413 ;
     RECT  21.315 2.143 21.405 2.413 ;
     RECT  24.015 2.143 24.105 2.413 ;
     RECT  26.715 2.143 26.805 2.413 ;
     RECT  29.415 2.143 29.505 2.413 ;
     RECT  32.115 2.143 32.205 2.413 ;
     RECT  34.815 2.143 34.905 2.413 ;
     RECT  37.515 2.143 37.605 2.413 ;
     RECT  40.215 2.143 40.305 2.413 ;
     RECT  42.915 2.143 43.005 2.413 ;
     RECT  45.615 2.143 45.705 2.413 ;
     RECT  48.315 2.143 48.405 2.413 ;
     RECT  51.015 2.143 51.105 2.413 ;
     RECT  53.715 2.143 53.805 2.413 ;
     RECT  56.415 2.143 56.505 2.413 ;
     RECT  59.115 2.143 59.205 2.413 ;
     RECT  61.815 2.143 61.905 2.413 ;
     RECT  64.515 2.143 64.605 2.413 ;
     RECT  67.215 2.143 67.305 2.413 ;
     RECT  69.915 2.143 70.005 2.413 ;
     RECT  72.615 2.143 72.705 2.413 ;
     RECT  75.315 2.143 75.405 2.413 ;
     RECT  78.015 2.143 78.105 2.413 ;
     RECT  80.715 2.143 80.805 2.413 ;
     RECT  83.415 2.143 83.505 2.413 ;
     RECT  86.115 2.143 86.205 2.413 ;
     RECT  88.815 2.143 88.905 2.413 ;
     RECT  91.515 2.143 91.605 2.413 ;
     RECT  94.215 2.143 94.305 2.413 ;
     RECT  3.528 31.531 3.546 31.685 ;
     RECT  0.108 31.675 0.126 31.723 ;
     RECT  9.288 31.621 9.306 31.729 ;
     RECT  3.744 31.723 3.762 31.765 ;
     RECT  6.912 31.693 6.93 31.765 ;
     RECT  3.744 31.765 4.158 31.829 ;
     RECT  5.115 2.413 5.397 31.891 ;
     RECT  6.264 31.765 6.93 31.891 ;
     RECT  5.115 31.891 6.93 31.919 ;
     RECT  2.415 2.413 2.697 32.059 ;
     RECT  8.856 31.729 9.306 32.071 ;
     RECT  3.996 31.829 4.158 32.093 ;
     RECT  2.415 32.059 2.79 32.099 ;
     RECT  5.115 31.919 5.85 32.099 ;
     RECT  40.215 2.413 40.497 32.269 ;
     RECT  8.856 32.071 9.342 32.297 ;
     RECT  5.115 32.099 5.562 32.299 ;
     RECT  7.815 2.413 8.097 32.305 ;
     RECT  8.856 32.297 9.234 32.305 ;
     RECT  6.624 31.919 6.93 32.341 ;
     RECT  7.815 32.305 9.234 32.341 ;
     RECT  0.108 31.723 0.198 32.827 ;
     RECT  3.6 32.611 3.618 32.827 ;
     RECT  4.464 32.299 5.562 32.827 ;
     RECT  3.6 32.827 5.562 32.881 ;
     RECT  2.415 32.099 2.697 32.971 ;
     RECT  3.6 32.881 5.742 32.971 ;
     RECT  0.108 32.827 0.342 33.005 ;
     RECT  2.415 32.971 5.742 33.007 ;
     RECT  6.624 32.341 9.234 33.007 ;
     RECT  2.415 33.007 9.234 33.071 ;
     RECT  39.024 32.809 39.042 33.313 ;
     RECT  10.515 2.413 10.797 33.421 ;
     RECT  4.212 33.071 9.234 33.809 ;
     RECT  40.215 32.269 40.626 33.889 ;
     RECT  2.415 33.071 3.438 33.925 ;
     RECT  7.815 33.809 9.234 33.961 ;
     RECT  7.815 33.961 9.414 33.965 ;
     RECT  2.415 33.925 3.474 34.087 ;
     RECT  4.212 33.809 7.074 34.087 ;
     RECT  0.108 33.005 0.126 34.151 ;
     RECT  37.515 2.413 37.797 34.501 ;
     RECT  39.024 33.313 39.438 34.501 ;
     RECT  0.54 34.501 0.558 34.589 ;
     RECT  7.815 33.965 8.097 34.795 ;
     RECT  8.82 33.965 9.414 34.795 ;
     RECT  2.415 34.087 7.074 34.843 ;
     RECT  2.268 34.843 7.074 34.889 ;
     RECT  2.268 34.889 6.102 34.961 ;
     RECT  37.515 34.501 39.438 34.969 ;
     RECT  40.215 33.889 40.842 34.969 ;
     RECT  6.912 34.889 7.074 35.041 ;
     RECT  7.815 34.795 9.414 35.041 ;
     RECT  6.912 35.041 9.414 35.069 ;
     RECT  0.108 35.131 0.126 35.339 ;
     RECT  2.304 34.961 6.102 35.645 ;
     RECT  3.42 35.645 6.102 35.741 ;
     RECT  2.304 35.645 2.697 36.269 ;
     RECT  3.456 35.741 6.102 36.481 ;
     RECT  6.948 35.069 9.414 36.481 ;
     RECT  37.515 34.969 40.842 36.823 ;
     RECT  3.456 36.481 9.414 37.391 ;
     RECT  95.904 37.531 95.922 37.579 ;
     RECT  94.215 2.413 94.497 38.203 ;
     RECT  95.76 37.579 95.922 38.203 ;
     RECT  94.215 38.203 95.922 38.429 ;
     RECT  12.24 35.131 12.258 38.479 ;
     RECT  13.215 2.413 13.497 38.479 ;
     RECT  94.215 38.429 95.778 38.573 ;
     RECT  91.515 2.413 91.797 38.683 ;
     RECT  92.52 38.641 92.538 38.713 ;
     RECT  3.456 37.391 8.097 38.777 ;
     RECT  92.52 38.713 92.898 38.785 ;
     RECT  91.332 38.683 91.797 38.821 ;
     RECT  92.52 38.785 92.934 38.821 ;
     RECT  86.115 2.413 86.397 38.947 ;
     RECT  85.464 38.947 86.397 39.019 ;
     RECT  3.456 38.777 3.546 39.047 ;
     RECT  75.315 2.413 75.597 39.091 ;
     RECT  91.332 38.821 93.114 39.091 ;
     RECT  94.215 38.573 95.742 39.091 ;
     RECT  91.332 39.091 95.742 39.119 ;
     RECT  90.216 39.091 90.234 39.181 ;
     RECT  85.464 39.019 86.67 39.209 ;
     RECT  91.332 39.119 92.754 39.209 ;
     RECT  90.072 39.181 90.558 39.259 ;
     RECT  86.115 39.209 86.67 39.317 ;
     RECT  89.82 39.259 90.558 39.451 ;
     RECT  4.284 38.777 8.097 39.623 ;
     RECT  75.315 39.091 75.654 39.631 ;
     RECT  78.015 2.413 78.297 39.721 ;
     RECT  83.415 2.413 83.697 39.757 ;
     RECT  93.492 39.119 95.742 39.821 ;
     RECT  78.015 39.721 78.75 39.857 ;
     RECT  83.415 39.757 83.754 39.857 ;
     RECT  75.132 39.631 75.654 39.865 ;
     RECT  78.015 39.857 78.678 39.893 ;
     RECT  75.132 39.865 76.014 39.901 ;
     RECT  12.24 38.479 13.497 39.991 ;
     RECT  89.82 39.451 90.666 39.991 ;
     RECT  91.515 39.209 92.754 39.991 ;
     RECT  4.284 39.623 4.302 40.027 ;
     RECT  88.815 2.413 89.097 40.027 ;
     RECT  89.82 39.991 92.754 40.027 ;
     RECT  88.815 40.027 92.754 40.171 ;
     RECT  93.492 39.821 94.77 40.171 ;
     RECT  12.06 39.991 13.497 40.205 ;
     RECT  14.22 40.123 14.238 40.267 ;
     RECT  21.315 2.413 21.597 40.267 ;
     RECT  29.415 2.413 29.697 40.267 ;
     RECT  12.06 40.205 12.078 40.289 ;
     RECT  14.22 40.267 14.85 40.301 ;
     RECT  14.832 40.301 14.85 40.397 ;
     RECT  21.315 40.267 21.69 40.397 ;
     RECT  22.824 40.267 22.842 40.397 ;
     RECT  29.415 40.267 29.79 40.397 ;
     RECT  30.78 40.267 30.798 40.397 ;
     RECT  4.248 40.027 4.302 40.441 ;
     RECT  5.115 39.623 8.097 40.441 ;
     RECT  88.815 40.171 94.77 40.469 ;
     RECT  8.82 37.391 9.414 40.531 ;
     RECT  45.615 2.413 45.897 40.555 ;
     RECT  56.415 2.413 56.697 40.555 ;
     RECT  59.115 2.413 59.397 40.555 ;
     RECT  45.615 40.555 46.422 40.567 ;
     RECT  86.115 39.317 86.397 40.567 ;
     RECT  90.612 40.469 94.77 40.567 ;
     RECT  95.724 39.821 95.742 40.567 ;
     RECT  83.415 39.857 83.697 40.639 ;
     RECT  86.115 40.567 86.67 40.639 ;
     RECT  3.456 39.047 3.51 40.651 ;
     RECT  4.248 40.441 8.097 40.651 ;
     RECT  64.515 2.413 64.797 40.711 ;
     RECT  75.132 39.901 76.698 40.711 ;
     RECT  85.392 40.639 86.67 40.711 ;
     RECT  90.612 40.567 95.742 40.711 ;
     RECT  3.456 40.651 8.097 40.739 ;
     RECT  85.392 40.711 86.742 40.739 ;
     RECT  42.915 2.413 43.197 40.787 ;
     RECT  48.315 2.413 48.597 40.787 ;
     RECT  51.015 2.413 51.297 40.787 ;
     RECT  53.715 2.413 53.997 40.787 ;
     RECT  58.752 40.555 59.397 40.787 ;
     RECT  61.815 2.413 62.097 40.787 ;
     RECT  67.215 2.413 67.497 40.787 ;
     RECT  69.915 2.413 70.197 40.787 ;
     RECT  72.615 2.413 72.897 40.787 ;
     RECT  64.515 40.711 65.286 40.801 ;
     RECT  82.728 40.639 83.697 40.801 ;
     RECT  45.615 40.567 46.746 40.829 ;
     RECT  58.752 40.787 59.205 40.829 ;
     RECT  45.615 40.829 46.422 40.877 ;
     RECT  56.415 40.555 57.222 40.877 ;
     RECT  64.515 40.801 65.358 40.877 ;
     RECT  78.015 39.893 78.642 40.901 ;
     RECT  82.656 40.801 83.697 40.909 ;
     RECT  0.54 40.711 0.558 40.925 ;
     RECT  86.115 40.739 86.742 40.973 ;
     RECT  90.612 40.711 95.922 40.973 ;
     RECT  64.515 40.877 65.07 41.021 ;
     RECT  3.492 40.739 8.097 41.035 ;
     RECT  8.82 40.531 9.702 41.035 ;
     RECT  42.915 40.787 43.146 41.057 ;
     RECT  45.615 40.877 45.705 41.057 ;
     RECT  48.315 40.787 48.405 41.057 ;
     RECT  51.015 40.787 51.105 41.057 ;
     RECT  53.715 40.787 53.805 41.057 ;
     RECT  56.415 40.877 56.505 41.057 ;
     RECT  59.115 40.829 59.205 41.057 ;
     RECT  61.815 40.787 61.905 41.057 ;
     RECT  64.515 41.021 64.605 41.057 ;
     RECT  67.215 40.787 67.305 41.057 ;
     RECT  69.915 40.787 70.005 41.057 ;
     RECT  72.615 40.787 72.705 41.057 ;
     RECT  82.08 40.909 83.697 41.099 ;
     RECT  80.715 2.413 80.997 41.143 ;
     RECT  82.656 41.099 82.674 41.369 ;
     RECT  75.024 40.711 76.698 41.645 ;
     RECT  3.492 41.035 9.702 41.707 ;
     RECT  86.115 40.973 86.634 41.741 ;
     RECT  88.815 40.469 89.838 41.755 ;
     RECT  90.648 40.973 95.922 41.755 ;
     RECT  88.815 41.755 95.922 41.792 ;
     RECT  88.815 41.792 89.838 41.995 ;
     RECT  80.715 41.143 81.234 42.025 ;
     RECT  86.115 41.741 86.397 42.025 ;
     RECT  10.515 33.421 11.106 42.061 ;
     RECT  79.344 42.061 79.362 42.151 ;
     RECT  85.32 42.061 85.338 42.179 ;
     RECT  97.452 39.595 97.47 42.251 ;
     RECT  2.415 36.269 2.697 42.331 ;
     RECT  3.42 41.707 9.702 42.331 ;
     RECT  80.715 42.025 81.486 42.331 ;
     RECT  0.144 41.035 0.162 42.365 ;
     RECT  82.656 42.331 82.674 42.449 ;
     RECT  86.076 42.025 86.397 42.449 ;
     RECT  88.38 41.995 89.838 42.565 ;
     RECT  34.815 2.413 35.097 42.601 ;
     RECT  88.092 42.565 89.838 42.601 ;
     RECT  90.612 41.792 95.922 42.601 ;
     RECT  0.54 42.601 0.558 42.653 ;
     RECT  88.092 42.601 95.922 42.719 ;
     RECT  78.015 40.901 78.297 42.727 ;
     RECT  79.344 42.151 79.47 42.727 ;
     RECT  88.704 42.719 95.922 42.755 ;
     RECT  43.056 41.057 43.146 42.763 ;
     RECT  75.132 41.645 76.698 42.997 ;
     RECT  78.015 42.727 79.47 42.997 ;
     RECT  2.415 42.331 9.702 43.097 ;
     RECT  37.515 36.823 40.95 43.141 ;
     RECT  42.984 42.763 43.146 43.2 ;
     RECT  75.132 42.997 79.47 43.2 ;
     RECT  88.704 42.755 89.838 43.259 ;
     RECT  87.444 43.141 87.462 43.295 ;
     RECT  90.612 42.755 95.922 43.295 ;
     RECT  80.715 42.331 81.558 43.303 ;
     RECT  0.108 43.195 0.126 43.387 ;
     RECT  0.108 43.387 0.162 43.517 ;
     RECT  83.415 41.099 83.697 43.843 ;
     RECT  90.648 43.295 95.922 43.871 ;
     RECT  2.415 43.097 9.198 43.879 ;
     RECT  91.224 43.871 95.922 44.105 ;
     RECT  2.415 43.879 9.306 44.149 ;
     RECT  42.984 43.2 79.47 44.155 ;
     RECT  2.415 44.149 9.342 44.203 ;
     RECT  34.815 42.601 35.622 44.221 ;
     RECT  42.624 44.155 79.47 44.221 ;
     RECT  2.304 44.203 9.342 44.249 ;
     RECT  91.224 44.105 95.778 44.249 ;
     RECT  2.415 44.249 9.342 44.339 ;
     RECT  87.48 44.059 87.498 44.347 ;
     RECT  95.22 44.249 95.778 44.375 ;
     RECT  37.515 43.141 41.022 44.383 ;
     RECT  42.228 44.221 79.47 44.383 ;
     RECT  88.815 43.259 89.838 44.443 ;
     RECT  34.776 44.221 35.622 44.447 ;
     RECT  95.22 44.375 95.238 44.447 ;
     RECT  84.456 44.395 84.474 44.683 ;
     RECT  0.108 43.517 0.126 44.779 ;
     RECT  10.515 42.061 11.682 44.789 ;
     RECT  0.108 44.779 0.342 44.957 ;
     RECT  12.816 40.205 13.497 45.059 ;
     RECT  88.815 44.443 90.342 45.245 ;
     RECT  7.815 44.339 9.162 45.329 ;
     RECT  2.415 44.339 7.074 45.355 ;
     RECT  2.304 45.355 7.074 45.419 ;
     RECT  89.82 45.245 90.342 45.533 ;
     RECT  91.224 44.249 94.497 45.563 ;
     RECT  2.415 45.419 7.074 45.571 ;
     RECT  7.815 45.329 8.874 45.571 ;
     RECT  87.48 44.347 88.074 45.571 ;
     RECT  88.815 45.245 89.097 45.571 ;
     RECT  91.224 45.563 93.294 45.725 ;
     RECT  86.115 42.449 86.397 45.739 ;
     RECT  2.415 45.571 8.874 45.833 ;
     RECT  86.115 45.739 86.67 45.869 ;
     RECT  2.415 45.833 8.838 45.959 ;
     RECT  82.908 43.843 83.697 45.979 ;
     RECT  37.515 44.383 79.47 46.109 ;
     RECT  76.572 46.109 79.47 46.205 ;
     RECT  80.715 43.303 81.81 46.219 ;
     RECT  82.656 45.979 83.697 46.219 ;
     RECT  80.715 46.219 83.697 46.265 ;
     RECT  76.644 46.205 79.47 46.349 ;
     RECT  80.715 46.265 81.81 46.363 ;
     RECT  87.48 45.571 89.097 46.397 ;
     RECT  80.604 46.363 81.81 46.535 ;
     RECT  80.676 46.535 81.81 46.541 ;
     RECT  34.815 44.447 35.622 46.679 ;
     RECT  86.115 45.869 86.397 46.747 ;
     RECT  86.115 46.747 86.49 46.877 ;
     RECT  80.715 46.541 81.81 46.949 ;
     RECT  91.224 45.725 93.258 47.039 ;
     RECT  11.664 44.789 11.682 47.111 ;
     RECT  81.756 46.949 81.81 47.117 ;
     RECT  91.224 47.039 93.042 47.165 ;
     RECT  2.415 45.959 3.51 47.183 ;
     RECT  76.644 46.349 78.93 47.213 ;
     RECT  76.644 47.213 78.39 47.219 ;
     RECT  91.515 47.165 93.042 47.309 ;
     RECT  91.515 47.309 92.322 47.417 ;
     RECT  91.515 47.417 91.854 47.453 ;
     RECT  82.908 46.265 83.697 47.645 ;
     RECT  37.515 46.109 75.762 47.723 ;
     RECT  94.215 45.563 94.497 47.803 ;
     RECT  93.276 47.803 93.294 47.821 ;
     RECT  94.176 47.803 94.497 47.821 ;
     RECT  79.344 47.323 79.362 47.891 ;
     RECT  38.52 47.723 75.762 48.029 ;
     RECT  93.276 47.821 94.497 48.163 ;
     RECT  4.248 45.959 8.838 48.191 ;
     RECT  92.7 48.163 94.497 48.317 ;
     RECT  76.644 47.219 78.297 48.413 ;
     RECT  38.52 48.029 75.582 48.425 ;
     RECT  2.415 47.183 3.438 48.569 ;
     RECT  38.556 48.425 75.582 48.701 ;
     RECT  42.192 48.701 75.582 48.811 ;
     RECT  4.5 48.191 8.838 48.839 ;
     RECT  42.192 48.811 75.834 48.901 ;
     RECT  76.896 48.413 78.297 49.001 ;
     RECT  34.815 46.679 35.097 49.009 ;
     RECT  4.5 48.839 8.622 49.109 ;
     RECT  2.415 48.569 3.366 49.307 ;
     RECT  37.515 47.723 37.797 49.315 ;
     RECT  38.556 48.701 41.166 49.315 ;
     RECT  42.192 48.901 75.87 49.351 ;
     RECT  42.192 49.351 76.41 49.373 ;
     RECT  4.5 49.109 8.097 49.379 ;
     RECT  37.515 49.315 41.166 49.513 ;
     RECT  34.776 49.009 35.097 49.577 ;
     RECT  4.5 49.379 6.858 49.649 ;
     RECT  42.624 49.373 76.41 49.757 ;
     RECT  6.84 49.649 6.858 49.919 ;
     RECT  37.515 49.513 41.634 50.009 ;
     RECT  4.5 49.649 6.03 50.189 ;
     RECT  5.115 50.189 6.03 50.549 ;
     RECT  38.52 50.009 41.634 50.593 ;
     RECT  42.624 49.757 75.192 50.593 ;
     RECT  92.7 48.317 93.402 50.791 ;
     RECT  92.7 50.791 93.474 50.819 ;
     RECT  38.52 50.593 75.192 51.245 ;
     RECT  94.215 48.317 94.497 51.643 ;
     RECT  95.904 51.601 95.922 51.677 ;
     RECT  93.456 50.819 93.474 51.871 ;
     RECT  94.215 51.643 94.59 51.871 ;
     RECT  95.76 51.745 95.85 51.871 ;
     RECT  38.808 51.245 75.192 51.971 ;
     RECT  76.392 49.757 76.41 52.169 ;
     RECT  37.515 50.009 37.797 52.249 ;
     RECT  38.808 51.971 40.986 52.249 ;
     RECT  90.324 45.533 90.342 52.249 ;
     RECT  95.724 51.871 95.85 52.285 ;
     RECT  37.515 52.249 40.986 52.301 ;
     RECT  93.456 51.871 94.59 52.315 ;
     RECT  92.7 50.819 92.718 52.321 ;
     RECT  93.456 52.315 94.662 52.321 ;
     RECT  39.024 52.301 40.986 52.349 ;
     RECT  77.22 49.001 78.297 52.349 ;
     RECT  92.7 52.321 94.662 52.411 ;
     RECT  95.508 52.285 95.85 52.411 ;
     RECT  77.4 52.349 78.297 52.475 ;
     RECT  92.7 52.411 95.922 52.591 ;
     RECT  39.06 52.349 40.986 52.699 ;
     RECT  88.815 46.397 89.097 52.699 ;
     RECT  96.912 52.555 96.93 52.733 ;
     RECT  88.815 52.699 89.37 52.745 ;
     RECT  42.048 51.971 75.192 52.825 ;
     RECT  90.324 52.249 90.666 52.861 ;
     RECT  91.515 47.453 91.797 52.861 ;
     RECT  76.392 52.891 76.41 53.015 ;
     RECT  39.06 52.699 41.022 53.083 ;
     RECT  38.7 53.083 41.022 53.123 ;
     RECT  86.115 46.877 86.397 53.257 ;
     RECT  77.436 52.475 78.297 53.275 ;
     RECT  42.048 52.825 75.51 53.329 ;
     RECT  86.115 53.257 86.67 53.329 ;
     RECT  90.324 52.861 91.797 53.329 ;
     RECT  92.52 52.591 95.922 53.329 ;
     RECT  38.916 53.123 41.022 53.393 ;
     RECT  90.324 53.329 95.922 53.515 ;
     RECT  76.68 53.275 78.297 53.555 ;
     RECT  86.115 53.329 86.742 53.591 ;
     RECT  39.348 53.393 41.022 53.755 ;
     RECT  42.048 53.329 75.582 53.755 ;
     RECT  39.348 53.755 75.582 53.789 ;
     RECT  42.12 53.789 75.582 53.869 ;
     RECT  76.68 53.555 77.274 53.869 ;
     RECT  90.252 53.515 95.922 53.899 ;
     RECT  42.12 53.869 77.274 54.059 ;
     RECT  90.036 53.899 95.922 54.077 ;
     RECT  39.348 53.789 41.382 54.211 ;
     RECT  90.036 54.077 95.778 54.331 ;
     RECT  86.115 53.591 86.397 54.481 ;
     RECT  89.892 54.331 95.778 54.599 ;
     RECT  86.115 54.481 86.706 54.635 ;
     RECT  97.452 53.707 97.47 54.671 ;
     RECT  88.815 52.745 89.097 54.841 ;
     RECT  89.892 54.599 91.854 54.841 ;
     RECT  78.015 53.555 78.297 54.949 ;
     RECT  92.7 54.599 95.778 55.291 ;
     RECT  39.24 54.211 41.382 55.489 ;
     RECT  42.192 54.059 77.274 55.489 ;
     RECT  87.48 46.397 88.074 55.823 ;
     RECT  88.815 54.841 91.854 55.831 ;
     RECT  92.7 55.291 95.85 55.831 ;
     RECT  81.756 47.117 81.774 55.949 ;
     RECT  86.115 54.635 86.67 56.029 ;
     RECT  86.115 56.029 86.742 56.129 ;
     RECT  86.115 56.129 86.67 56.363 ;
     RECT  83.415 47.645 83.697 56.461 ;
     RECT  84.456 44.683 84.654 56.461 ;
     RECT  83.415 56.461 84.654 56.489 ;
     RECT  83.415 56.489 84.402 56.525 ;
     RECT  88.815 55.831 95.85 56.561 ;
     RECT  98.1 56.443 98.118 56.573 ;
     RECT  91.224 56.561 95.85 56.587 ;
     RECT  88.815 56.561 90.27 56.759 ;
     RECT  88.815 56.759 89.19 56.813 ;
     RECT  88.056 55.823 88.074 56.939 ;
     RECT  91.224 56.587 95.922 57.019 ;
     RECT  90.108 56.759 90.27 57.197 ;
     RECT  90.18 57.197 90.27 57.209 ;
     RECT  91.224 57.019 96.426 57.245 ;
     RECT  90.252 57.209 90.27 57.307 ;
     RECT  91.224 57.245 91.797 57.307 ;
     RECT  92.7 57.245 96.426 57.533 ;
     RECT  90.252 57.307 91.797 57.569 ;
     RECT  90.648 57.569 91.797 57.641 ;
     RECT  92.7 57.533 95.922 57.869 ;
     RECT  92.7 57.869 95.778 57.875 ;
     RECT  39.24 55.489 77.274 58.109 ;
     RECT  39.24 58.109 77.238 60.504 ;
     RECT  70.704 60.504 70.794 60.647 ;
     RECT  70.704 60.647 70.722 60.764 ;
     RECT  86.115 56.363 86.397 61.051 ;
     RECT  39.24 60.504 43.146 61.079 ;
     RECT  92.7 57.875 95.058 61.079 ;
     RECT  42.372 61.079 43.146 61.151 ;
     RECT  74.664 60.504 77.238 61.181 ;
     RECT  86.115 61.051 86.67 61.181 ;
     RECT  42.516 61.151 43.146 61.187 ;
     RECT  91.224 57.641 91.797 61.187 ;
     RECT  75.204 61.181 77.238 61.223 ;
     RECT  75.204 61.223 76.194 61.421 ;
     RECT  39.24 61.079 41.346 61.457 ;
     RECT  77.22 61.223 77.238 61.457 ;
     RECT  41.328 61.457 41.346 61.619 ;
     RECT  92.7 61.079 94.878 61.889 ;
     RECT  42.588 61.187 43.146 62.465 ;
     RECT  49.32 61.861 49.338 62.509 ;
     RECT  49.32 62.509 49.446 62.545 ;
     RECT  78.015 54.949 78.93 62.609 ;
     RECT  50.868 62.437 50.886 62.623 ;
     RECT  49.32 62.545 49.662 62.699 ;
     RECT  94.215 61.889 94.878 62.699 ;
     RECT  50.868 62.623 51.105 62.879 ;
     RECT  42.624 62.465 43.146 62.893 ;
     RECT  45.615 62.623 45.705 62.893 ;
     RECT  48.315 62.623 48.405 62.893 ;
     RECT  51.015 62.879 51.105 62.893 ;
     RECT  53.715 62.623 53.805 62.893 ;
     RECT  56.415 62.623 56.505 62.893 ;
     RECT  59.115 62.623 59.205 62.893 ;
     RECT  61.815 62.623 61.905 62.893 ;
     RECT  64.515 62.623 64.605 62.893 ;
     RECT  67.215 62.623 67.305 62.893 ;
     RECT  69.915 62.623 70.005 62.893 ;
     RECT  72.615 62.623 72.705 62.893 ;
     RECT  75.204 61.421 75.474 62.893 ;
     RECT  75.204 62.893 75.597 62.969 ;
     RECT  42.624 62.893 43.197 64.561 ;
     RECT  42.624 64.561 43.542 64.859 ;
     RECT  42.624 64.859 43.254 64.877 ;
     RECT  42.624 64.877 43.218 64.973 ;
     RECT  92.7 61.889 93.402 65.273 ;
     RECT  80.715 46.949 80.997 65.707 ;
     RECT  80.532 65.707 80.997 65.747 ;
     RECT  78.015 62.609 78.297 65.803 ;
     RECT  79.488 65.245 79.506 65.803 ;
     RECT  78.015 65.803 79.506 65.849 ;
     RECT  78.015 65.849 78.297 67.819 ;
     RECT  78.015 67.819 78.606 68.099 ;
     RECT  78.015 68.099 78.297 70.123 ;
     RECT  78.015 70.123 78.678 70.529 ;
     RECT  78.015 70.529 78.297 70.645 ;
     RECT  77.328 70.645 78.297 70.685 ;
     RECT  91.515 61.187 91.797 71.761 ;
     RECT  91.515 71.761 92.034 71.837 ;
     RECT  90.036 71.761 90.054 71.947 ;
     RECT  90.036 71.947 90.558 72.301 ;
     RECT  90.036 72.301 90.63 72.571 ;
     RECT  90 72.571 90.63 72.701 ;
     RECT  76.896 72.955 76.914 73.229 ;
     RECT  76.608 73.273 76.626 73.325 ;
     RECT  0.108 74.299 0.126 74.443 ;
     RECT  13.215 45.059 13.497 74.461 ;
     RECT  3.996 74.461 4.158 74.551 ;
     RECT  10.515 44.789 10.797 74.551 ;
     RECT  0.108 74.443 0.342 74.621 ;
     RECT  3.528 74.551 4.158 74.621 ;
     RECT  13.215 74.461 13.59 74.621 ;
     RECT  5.115 50.549 5.397 74.695 ;
     RECT  5.115 74.695 5.562 74.821 ;
     RECT  6.876 74.425 6.894 74.875 ;
     RECT  6.876 74.875 6.966 74.893 ;
     RECT  7.815 49.379 8.097 74.893 ;
     RECT  9.144 74.461 9.162 74.893 ;
     RECT  6.732 74.893 6.966 75.067 ;
     RECT  37.515 52.301 37.797 75.091 ;
     RECT  7.815 74.893 9.162 75.155 ;
     RECT  6.66 75.067 7.038 75.163 ;
     RECT  7.815 75.155 8.37 75.163 ;
     RECT  2.415 49.307 2.697 75.259 ;
     RECT  78.015 70.685 78.297 75.433 ;
     RECT  75.315 62.969 75.597 75.451 ;
     RECT  2.415 75.259 2.79 75.469 ;
     RECT  77.292 75.433 78.297 75.485 ;
     RECT  0.108 74.621 0.162 75.499 ;
     RECT  9.144 75.155 9.162 75.533 ;
     RECT  0.108 75.499 0.198 75.569 ;
     RECT  75.315 75.451 75.762 75.569 ;
     RECT  2.415 75.469 3.006 75.595 ;
     RECT  5.115 74.821 5.778 75.631 ;
     RECT  6.66 75.163 8.37 75.631 ;
     RECT  10.515 74.551 11.106 75.631 ;
     RECT  2.304 75.595 3.006 75.659 ;
     RECT  3.744 74.621 4.158 75.739 ;
     RECT  5.115 75.631 8.37 75.739 ;
     RECT  0.144 75.569 0.198 75.773 ;
     RECT  2.304 75.659 2.754 75.811 ;
     RECT  0.144 75.773 0.162 76.013 ;
     RECT  2.268 75.811 2.754 76.061 ;
     RECT  3.528 75.739 8.37 76.081 ;
     RECT  3.528 76.081 8.946 76.199 ;
     RECT  2.304 76.061 2.754 76.513 ;
     RECT  3.528 76.199 8.91 76.513 ;
     RECT  37.515 75.091 38.502 76.621 ;
     RECT  39.24 61.457 40.497 76.621 ;
     RECT  2.304 76.513 8.91 76.795 ;
     RECT  2.016 76.795 8.91 76.925 ;
     RECT  10.224 75.631 11.106 77.161 ;
     RECT  0.108 76.603 0.126 77.459 ;
     RECT  2.415 76.925 8.91 77.701 ;
     RECT  2.415 77.701 9.162 77.755 ;
     RECT  2.304 77.755 9.162 77.819 ;
     RECT  84.96 77.935 84.978 77.947 ;
     RECT  86.115 61.181 86.397 77.947 ;
     RECT  84.96 77.947 85.086 77.981 ;
     RECT  67.215 62.893 67.497 78.043 ;
     RECT  93.384 65.273 93.402 78.043 ;
     RECT  94.215 62.699 94.497 78.043 ;
     RECT  86.115 77.947 86.67 78.077 ;
     RECT  66.708 78.043 67.497 78.089 ;
     RECT  85.068 77.981 85.086 78.089 ;
     RECT  65.556 78.061 65.574 78.091 ;
     RECT  0.144 77.947 0.162 78.331 ;
     RECT  64.515 62.893 64.797 78.367 ;
     RECT  65.556 78.091 65.754 78.367 ;
     RECT  93.384 78.043 94.497 78.503 ;
     RECT  64.515 78.367 65.754 78.511 ;
     RECT  79.488 65.849 79.506 78.511 ;
     RECT  0.108 78.331 0.162 78.539 ;
     RECT  2.415 77.819 8.874 78.629 ;
     RECT  64.515 78.511 65.79 78.629 ;
     RECT  3.492 78.629 8.874 78.637 ;
     RECT  9.936 77.161 11.106 78.637 ;
     RECT  0.144 78.539 0.162 78.653 ;
     RECT  2.415 78.629 2.754 78.763 ;
     RECT  2.304 78.763 2.754 78.809 ;
     RECT  3.492 78.637 11.106 78.971 ;
     RECT  2.415 78.809 2.754 79.511 ;
     RECT  37.515 76.621 40.497 79.519 ;
     RECT  3.492 78.971 8.874 79.753 ;
     RECT  9.936 78.971 11.106 79.753 ;
     RECT  95.904 80.221 95.922 80.329 ;
     RECT  37.515 79.519 40.734 80.635 ;
     RECT  93.564 78.503 94.497 80.761 ;
     RECT  95.76 80.329 95.922 80.761 ;
     RECT  93.564 80.761 95.922 81.031 ;
     RECT  93.528 81.031 95.922 81.149 ;
     RECT  92.592 81.019 92.61 81.205 ;
     RECT  92.592 81.205 92.754 81.403 ;
     RECT  93.528 81.149 95.778 81.403 ;
     RECT  91.515 71.837 91.797 81.499 ;
     RECT  92.592 81.403 95.778 81.499 ;
     RECT  75.315 75.569 75.597 81.751 ;
     RECT  90.648 81.643 90.666 81.841 ;
     RECT  90.648 81.841 90.774 81.877 ;
     RECT  75.315 81.751 75.798 82.021 ;
     RECT  90.576 81.877 90.774 82.021 ;
     RECT  83.415 56.525 83.697 82.075 ;
     RECT  90.072 82.021 90.774 82.291 ;
     RECT  91.515 81.499 95.778 82.291 ;
     RECT  83.415 82.075 84.402 82.381 ;
     RECT  85.212 81.949 85.23 82.381 ;
     RECT  75.315 82.021 75.978 82.408 ;
     RECT  83.415 82.381 85.23 82.445 ;
     RECT  88.815 56.813 89.097 82.561 ;
     RECT  42.624 64.973 43.197 82.651 ;
     RECT  90.072 82.291 95.778 82.651 ;
     RECT  64.515 78.629 65.286 82.679 ;
     RECT  42.588 82.651 43.197 82.687 ;
     RECT  78.015 75.485 78.297 82.687 ;
     RECT  86.115 78.077 86.397 82.723 ;
     RECT  75.132 82.408 75.978 82.831 ;
     RECT  86.115 82.723 86.706 82.859 ;
     RECT  85.176 82.445 85.23 82.939 ;
     RECT  78.015 82.687 78.642 83.021 ;
     RECT  88.815 82.561 89.19 83.227 ;
     RECT  90.072 82.651 95.922 83.227 ;
     RECT  85.176 82.939 85.338 83.255 ;
     RECT  88.815 83.227 95.922 83.261 ;
     RECT  3.492 79.753 11.106 83.525 ;
     RECT  42.444 82.687 43.197 83.563 ;
     RECT  85.212 83.255 85.338 83.563 ;
     RECT  86.115 82.859 86.397 83.563 ;
     RECT  64.515 82.679 65.142 83.641 ;
     RECT  64.515 83.641 65.25 83.755 ;
     RECT  67.215 78.089 67.497 83.755 ;
     RECT  88.815 83.261 89.442 83.759 ;
     RECT  64.404 83.755 65.25 83.795 ;
     RECT  66.492 83.755 67.497 83.795 ;
     RECT  85.212 83.563 86.397 83.795 ;
     RECT  72.615 62.893 72.897 83.803 ;
     RECT  78.015 83.021 78.297 83.803 ;
     RECT  83.415 82.445 83.697 83.803 ;
     RECT  83.232 83.803 83.697 83.851 ;
     RECT  86.115 83.795 86.397 83.851 ;
     RECT  53.715 62.893 53.997 83.899 ;
     RECT  61.815 62.893 62.097 83.899 ;
     RECT  64.515 83.795 65.25 83.899 ;
     RECT  42.444 83.563 43.542 83.903 ;
     RECT  48.315 62.893 48.597 83.911 ;
     RECT  69.915 62.893 70.197 83.911 ;
     RECT  75.096 82.831 75.978 83.911 ;
     RECT  76.716 83.731 76.806 83.911 ;
     RECT  66.708 83.795 67.497 83.933 ;
     RECT  78.015 83.803 78.678 83.933 ;
     RECT  87.768 83.641 87.786 83.939 ;
     RECT  45.615 62.893 45.897 83.987 ;
     RECT  51.015 62.893 51.297 83.987 ;
     RECT  56.415 62.893 56.697 83.987 ;
     RECT  59.115 62.893 59.397 83.987 ;
     RECT  67.215 83.933 67.497 83.987 ;
     RECT  72.615 83.803 73.098 83.992 ;
     RECT  72.36 83.992 73.098 84.001 ;
     RECT  75.096 83.911 76.806 84.001 ;
     RECT  48.315 83.911 49.554 84.029 ;
     RECT  69.915 83.911 70.902 84.029 ;
     RECT  72.36 84.001 73.17 84.029 ;
     RECT  82.656 83.851 83.697 84.029 ;
     RECT  53.715 83.899 54.09 84.043 ;
     RECT  54.828 83.899 54.846 84.043 ;
     RECT  90.288 83.261 95.922 84.065 ;
     RECT  48.315 84.029 49.23 84.077 ;
     RECT  53.715 84.043 54.846 84.077 ;
     RECT  61.815 83.899 62.802 84.077 ;
     RECT  69.915 84.029 70.83 84.077 ;
     RECT  72.615 84.029 73.17 84.077 ;
     RECT  85.212 83.795 85.23 84.091 ;
     RECT  48.315 84.077 49.05 84.125 ;
     RECT  75.096 84.001 77.274 84.125 ;
     RECT  82.656 84.029 82.674 84.125 ;
     RECT  85.176 84.091 85.23 84.137 ;
     RECT  46.764 84.043 46.782 84.173 ;
     RECT  53.715 84.077 54.198 84.173 ;
     RECT  64.515 83.899 65.97 84.173 ;
     RECT  72.615 84.077 72.99 84.173 ;
     RECT  79.488 78.511 79.902 84.173 ;
     RECT  90.288 84.065 90.306 84.209 ;
     RECT  45.615 83.987 45.705 84.257 ;
     RECT  48.315 84.125 48.405 84.257 ;
     RECT  51.015 83.987 51.105 84.257 ;
     RECT  53.715 84.173 53.805 84.257 ;
     RECT  56.415 83.987 56.505 84.257 ;
     RECT  59.115 83.987 59.205 84.257 ;
     RECT  61.815 84.077 61.905 84.257 ;
     RECT  64.515 84.173 65.142 84.257 ;
     RECT  67.215 83.987 67.305 84.257 ;
     RECT  69.915 84.077 70.722 84.257 ;
     RECT  72.615 84.173 72.705 84.257 ;
     RECT  70.704 84.257 70.722 84.299 ;
     RECT  42.624 83.903 43.542 84.365 ;
     RECT  86.115 83.851 86.67 84.365 ;
     RECT  91.044 84.065 95.922 84.365 ;
     RECT  97.452 81.787 97.47 84.371 ;
     RECT  3.492 83.525 3.654 84.541 ;
     RECT  4.608 83.525 11.106 84.541 ;
     RECT  78.015 83.933 78.57 84.569 ;
     RECT  3.492 84.541 11.106 84.641 ;
     RECT  15.915 2.413 16.197 84.649 ;
     RECT  78.015 84.569 78.297 84.721 ;
     RECT  2.415 79.511 2.697 84.811 ;
     RECT  2.304 84.811 2.697 84.848 ;
     RECT  79.668 84.173 79.902 85.081 ;
     RECT  91.044 84.365 95.85 85.099 ;
     RECT  87.228 84.721 87.246 85.109 ;
     RECT  86.115 84.365 86.397 85.117 ;
     RECT  3.492 84.641 10.818 85.144 ;
     RECT  82.584 85.081 82.602 85.181 ;
     RECT  79.488 85.081 79.902 85.217 ;
     RECT  2.415 84.848 2.697 85.225 ;
     RECT  3.42 85.144 10.818 85.225 ;
     RECT  65.124 84.257 65.142 85.253 ;
     RECT  90.648 85.099 95.85 85.261 ;
     RECT  0.144 85.147 0.162 85.277 ;
     RECT  90.648 85.261 95.922 85.325 ;
     RECT  2.415 85.225 10.818 85.379 ;
     RECT  86.115 85.117 87.102 85.379 ;
     RECT  90.648 85.325 95.814 85.435 ;
     RECT  88.815 83.759 89.334 85.627 ;
     RECT  0.54 85.801 0.558 85.853 ;
     RECT  90.468 85.435 95.814 85.919 ;
     RECT  86.115 85.379 86.67 85.927 ;
     RECT  90.468 85.919 90.63 85.955 ;
     RECT  86.112 85.927 86.67 85.991 ;
     RECT  88.56 85.627 89.334 85.999 ;
     RECT  88.416 85.999 89.334 86.045 ;
     RECT  86.112 85.991 86.454 86.099 ;
     RECT  88.815 86.045 89.334 86.155 ;
     RECT  88.815 86.155 89.694 86.161 ;
     RECT  88.815 86.161 89.838 86.237 ;
     RECT  91.404 85.919 95.814 86.237 ;
     RECT  95.76 86.237 95.814 86.299 ;
     RECT  37.515 80.635 40.878 86.341 ;
     RECT  91.404 86.237 95.022 86.381 ;
     RECT  42.624 84.365 43.11 86.4 ;
     RECT  75.096 84.125 76.806 86.4 ;
     RECT  2.415 85.379 10.797 86.459 ;
     RECT  95.76 86.299 95.994 86.459 ;
     RECT  90.612 85.955 90.63 86.603 ;
     RECT  81.972 86.071 81.99 86.611 ;
     RECT  92.628 86.381 95.022 86.621 ;
     RECT  2.415 86.459 9.45 86.837 ;
     RECT  4.392 86.837 9.45 86.909 ;
     RECT  95.76 86.459 95.922 87.008 ;
     RECT  95.76 87.008 95.778 87.035 ;
     RECT  2.415 86.837 3.654 87.115 ;
     RECT  42.624 86.4 76.806 87.151 ;
     RECT  91.404 86.381 91.797 87.151 ;
     RECT  90.9 87.151 91.797 87.211 ;
     RECT  92.628 86.621 94.497 87.211 ;
     RECT  37.515 86.341 40.986 87.241 ;
     RECT  0.108 86.395 0.126 87.307 ;
     RECT  37.515 87.241 41.634 87.349 ;
     RECT  42.588 87.151 76.806 87.349 ;
     RECT  79.524 85.217 79.902 87.355 ;
     RECT  0.108 87.307 0.162 87.437 ;
     RECT  83.415 84.029 83.697 87.595 ;
     RECT  2.304 87.115 3.654 87.691 ;
     RECT  4.392 86.909 9.414 87.691 ;
     RECT  85.212 84.137 85.23 87.917 ;
     RECT  37.515 87.349 76.806 88.061 ;
     RECT  0.108 87.437 0.126 88.171 ;
     RECT  36.756 79.483 36.774 88.223 ;
     RECT  0.108 88.171 0.198 88.301 ;
     RECT  2.304 87.691 9.414 88.349 ;
     RECT  4.392 88.349 9.414 88.493 ;
     RECT  79.488 87.355 79.902 88.619 ;
     RECT  90.9 87.211 94.497 88.771 ;
     RECT  0.108 88.301 0.126 88.799 ;
     RECT  37.515 88.061 41.742 88.897 ;
     RECT  42.624 88.061 76.806 88.897 ;
     RECT  77.796 84.721 78.297 88.939 ;
     RECT  86.115 86.099 86.454 88.939 ;
     RECT  10.515 86.459 10.797 88.969 ;
     RECT  90.648 88.771 94.497 88.973 ;
     RECT  2.304 88.349 3.654 89.069 ;
     RECT  86.115 88.939 86.67 89.069 ;
     RECT  2.304 89.069 3.618 89.168 ;
     RECT  4.392 88.493 6.174 89.231 ;
     RECT  10.515 88.969 10.818 89.231 ;
     RECT  4.464 89.231 6.174 89.239 ;
     RECT  6.912 88.493 9.414 89.239 ;
     RECT  88.815 86.237 89.334 89.239 ;
     RECT  88.704 89.239 89.334 89.311 ;
     RECT  37.515 88.897 76.806 89.405 ;
     RECT  88.704 89.311 89.478 89.597 ;
     RECT  77.796 88.939 78.678 89.693 ;
     RECT  88.815 89.597 89.478 89.741 ;
     RECT  37.515 89.405 76.734 89.789 ;
     RECT  13.215 74.621 13.497 89.815 ;
     RECT  15.915 84.649 16.794 89.843 ;
     RECT  42.192 89.789 76.734 89.879 ;
     RECT  42.192 89.879 76.662 89.888 ;
     RECT  86.115 89.069 86.454 89.947 ;
     RECT  90.9 88.973 94.497 89.969 ;
     RECT  2.415 89.168 3.618 90.041 ;
     RECT  90.9 89.969 92.214 90.043 ;
     RECT  42.192 89.888 76.194 90.077 ;
     RECT  86.115 89.947 86.49 90.077 ;
     RECT  93.348 89.969 94.497 90.077 ;
     RECT  42.192 90.077 76.122 90.173 ;
     RECT  93.348 90.077 93.474 90.239 ;
     RECT  81.972 86.611 82.314 90.317 ;
     RECT  2.415 90.041 3.402 90.347 ;
     RECT  86.115 90.077 86.454 90.365 ;
     RECT  86.115 90.365 86.397 90.481 ;
     RECT  90.576 90.043 92.214 90.545 ;
     RECT  4.464 89.239 9.414 90.589 ;
     RECT  4.464 90.589 9.486 90.617 ;
     RECT  4.464 90.617 7.002 90.653 ;
     RECT  78.015 89.693 78.678 90.715 ;
     RECT  77.904 90.715 78.678 90.779 ;
     RECT  37.515 89.789 41.346 90.823 ;
     RECT  42.192 90.173 75.87 90.823 ;
     RECT  37.515 90.823 75.87 90.845 ;
     RECT  82.296 90.317 82.314 90.845 ;
     RECT  78.015 90.779 78.678 90.893 ;
     RECT  86.004 90.481 86.397 90.893 ;
     RECT  34.815 49.577 35.097 90.895 ;
     RECT  34.776 90.895 35.097 91.049 ;
     RECT  42.624 90.845 75.87 91.165 ;
     RECT  7.815 90.617 9.486 91.499 ;
     RECT  37.515 90.845 41.634 91.661 ;
     RECT  78.015 90.893 78.297 91.705 ;
     RECT  42.624 91.165 76.374 91.805 ;
     RECT  76.356 91.805 76.374 91.901 ;
     RECT  38.52 91.661 41.634 91.939 ;
     RECT  13.215 89.815 13.95 91.967 ;
     RECT  34.815 91.049 35.097 91.975 ;
     RECT  4.572 90.653 7.002 92.003 ;
     RECT  77.544 91.705 78.297 92.011 ;
     RECT  4.572 92.003 6.174 92.039 ;
     RECT  38.52 91.939 41.706 92.245 ;
     RECT  42.624 91.805 75.192 92.245 ;
     RECT  38.52 92.245 75.192 92.381 ;
     RECT  29.415 40.397 29.697 92.443 ;
     RECT  18.615 2.413 18.897 92.551 ;
     RECT  21.315 40.397 21.597 92.551 ;
     RECT  22.824 92.539 22.842 92.551 ;
     RECT  14.832 92.443 14.85 92.573 ;
     RECT  29.415 92.443 29.79 92.573 ;
     RECT  30.78 92.443 30.798 92.573 ;
     RECT  9.468 91.499 9.486 92.579 ;
     RECT  22.824 92.551 22.914 92.579 ;
     RECT  18.615 92.551 18.954 92.669 ;
     RECT  22.896 92.579 22.914 92.669 ;
     RECT  76.932 92.011 78.297 92.731 ;
     RECT  4.716 92.039 6.174 92.741 ;
     RECT  38.52 92.381 41.706 92.861 ;
     RECT  76.392 92.731 78.297 92.861 ;
     RECT  21.315 92.551 22.086 92.909 ;
     RECT  6.984 92.003 7.002 92.939 ;
     RECT  37.515 91.661 37.797 93.091 ;
     RECT  38.52 92.861 41.634 93.091 ;
     RECT  13.215 91.967 13.698 93.281 ;
     RECT  7.815 91.499 8.19 93.389 ;
     RECT  34.776 91.975 35.097 93.389 ;
     RECT  5.115 92.741 6.174 93.479 ;
     RECT  6.156 93.479 6.174 93.515 ;
     RECT  37.515 93.091 41.634 93.515 ;
     RECT  42.624 92.381 75.192 93.901 ;
     RECT  42.588 93.901 75.192 94.027 ;
     RECT  76.392 92.861 76.41 94.027 ;
     RECT  42.588 94.027 76.41 94.109 ;
     RECT  77.616 92.861 78.297 94.171 ;
     RECT  38.52 93.515 41.634 94.261 ;
     RECT  42.588 94.109 75.192 94.261 ;
     RECT  38.52 94.261 75.192 94.493 ;
     RECT  77.58 94.171 78.297 94.595 ;
     RECT  38.52 94.493 41.346 95.323 ;
     RECT  42.084 94.493 75.192 95.323 ;
     RECT  76.392 94.109 76.41 95.323 ;
     RECT  77.616 94.595 78.297 95.515 ;
     RECT  95.904 95.605 95.922 95.707 ;
     RECT  94.215 90.077 94.497 96.061 ;
     RECT  95.76 95.707 95.922 96.061 ;
     RECT  94.215 96.061 95.922 96.187 ;
     RECT  77.58 95.515 78.297 96.283 ;
     RECT  90.9 90.545 92.214 96.331 ;
     RECT  93.6 96.187 95.922 96.331 ;
     RECT  90.648 96.331 92.214 96.379 ;
     RECT  76.392 95.323 76.446 96.449 ;
     RECT  93.492 96.331 95.922 96.449 ;
     RECT  97.452 96.331 97.47 96.475 ;
     RECT  97.416 96.475 97.47 96.521 ;
     RECT  38.52 95.323 75.192 96.529 ;
     RECT  90.648 96.379 92.574 96.557 ;
     RECT  38.52 96.529 75.51 96.565 ;
     RECT  38.52 96.565 75.582 96.571 ;
     RECT  90.9 96.557 92.574 96.571 ;
     RECT  93.636 96.449 95.922 96.629 ;
     RECT  77.4 96.283 78.297 96.755 ;
     RECT  77.436 96.755 78.297 96.989 ;
     RECT  86.115 90.893 86.397 97.069 ;
     RECT  90.9 96.571 92.862 97.231 ;
     RECT  93.636 96.629 95.778 97.231 ;
     RECT  37.515 93.515 37.797 97.375 ;
     RECT  38.52 96.571 75.834 97.375 ;
     RECT  90.9 97.231 95.778 97.501 ;
     RECT  90.648 97.501 95.85 97.565 ;
     RECT  86.115 97.069 86.67 97.609 ;
     RECT  86.115 97.609 86.706 97.645 ;
     RECT  90.648 97.565 95.742 97.645 ;
     RECT  90.108 97.645 95.742 97.673 ;
     RECT  86.115 97.645 86.778 97.799 ;
     RECT  97.452 96.521 97.47 97.871 ;
     RECT  37.515 97.375 75.834 98.185 ;
     RECT  76.644 96.667 76.662 98.185 ;
     RECT  90.108 97.673 95.526 98.581 ;
     RECT  37.515 98.185 76.662 98.617 ;
     RECT  37.512 98.617 76.662 98.669 ;
     RECT  90.108 98.581 95.778 98.915 ;
     RECT  86.115 97.799 86.67 99.059 ;
     RECT  37.515 98.669 76.662 99.185 ;
     RECT  90.54 98.915 95.778 99.451 ;
     RECT  90.54 99.451 95.922 99.571 ;
     RECT  97.452 99.355 97.47 99.643 ;
     RECT  22.572 99.643 22.59 99.661 ;
     RECT  97.452 99.643 98.19 99.661 ;
     RECT  22.356 99.661 22.59 99.689 ;
     RECT  97.452 99.661 98.262 99.689 ;
     RECT  98.244 99.689 98.262 99.725 ;
     RECT  90.54 99.571 95.958 99.733 ;
     RECT  88.815 89.741 89.097 99.769 ;
     RECT  22.356 99.689 22.374 99.773 ;
     RECT  86.115 99.059 86.397 99.841 ;
     RECT  79.488 88.619 79.578 99.959 ;
     RECT  86.115 99.841 86.67 100.003 ;
     RECT  83.415 87.595 83.754 100.111 ;
     RECT  86.115 100.003 86.742 100.139 ;
     RECT  90.324 99.733 95.958 100.219 ;
     RECT  79.56 99.959 79.578 100.229 ;
     RECT  83.415 100.111 83.79 100.229 ;
     RECT  82.656 100.201 82.674 100.301 ;
     RECT  83.415 100.229 83.754 100.499 ;
     RECT  97.452 99.689 97.47 100.507 ;
     RECT  39.528 99.185 76.662 100.535 ;
     RECT  97.416 100.507 97.47 100.571 ;
     RECT  88.815 99.769 89.478 100.651 ;
     RECT  90.252 100.219 95.958 100.651 ;
     RECT  88.815 100.651 95.958 100.769 ;
     RECT  97.452 100.571 97.47 100.841 ;
     RECT  88.815 100.769 89.514 101.039 ;
     RECT  39.528 100.535 76.158 101.731 ;
     RECT  39.528 101.731 76.194 103.704 ;
     RECT  90.396 100.769 95.958 103.775 ;
     RECT  90.396 103.775 95.382 103.847 ;
     RECT  90.396 103.847 92.142 103.883 ;
     RECT  90.396 103.883 91.998 103.919 ;
     RECT  74.664 103.704 76.194 103.964 ;
     RECT  93.276 103.847 95.382 104.387 ;
     RECT  93.276 104.387 94.842 104.423 ;
     RECT  93.312 104.423 94.842 104.459 ;
     RECT  39.528 103.704 43.146 104.549 ;
     RECT  93.636 104.459 94.842 104.549 ;
     RECT  90.972 103.919 91.998 104.585 ;
     RECT  39.528 104.549 41.31 104.693 ;
     RECT  94.215 104.549 94.842 105.161 ;
     RECT  90.972 104.585 91.89 105.197 ;
     RECT  92.736 105.307 92.754 105.359 ;
     RECT  91.188 105.197 91.89 105.629 ;
     RECT  51.336 105.169 51.354 105.637 ;
     RECT  48.564 105.133 48.582 105.709 ;
     RECT  75.204 103.964 76.194 105.737 ;
     RECT  49.932 105.709 49.95 105.781 ;
     RECT  51.336 105.637 51.426 105.781 ;
     RECT  75.204 105.737 75.597 105.809 ;
     RECT  48.564 105.709 48.69 105.823 ;
     RECT  64.944 105.451 64.962 105.823 ;
     RECT  48.315 105.823 48.69 105.899 ;
     RECT  49.932 105.781 50.022 105.899 ;
     RECT  50.904 105.781 51.426 105.899 ;
     RECT  75.24 105.809 75.597 105.935 ;
     RECT  46.764 105.745 46.782 105.971 ;
     RECT  67.215 105.823 67.305 105.973 ;
     RECT  42.12 104.549 43.146 106.093 ;
     RECT  45.615 105.823 45.705 106.093 ;
     RECT  53.715 105.823 53.805 106.093 ;
     RECT  56.415 105.823 56.505 106.093 ;
     RECT  59.115 105.823 59.205 106.093 ;
     RECT  61.815 105.823 61.905 106.093 ;
     RECT  66.492 105.973 67.305 106.093 ;
     RECT  69.915 105.823 70.005 106.093 ;
     RECT  72.615 105.823 72.705 106.093 ;
     RECT  64.515 105.823 64.962 106.169 ;
     RECT  66.492 106.093 67.497 106.301 ;
     RECT  41.292 104.693 41.31 106.861 ;
     RECT  42.12 106.093 43.197 106.861 ;
     RECT  41.292 106.861 43.197 106.925 ;
     RECT  42.12 106.925 43.197 107.275 ;
     RECT  42.12 107.275 43.254 107.671 ;
     RECT  64.515 106.169 64.797 107.752 ;
     RECT  41.292 106.925 41.31 107.761 ;
     RECT  42.12 107.671 43.542 107.761 ;
     RECT  41.292 107.761 43.542 107.789 ;
     RECT  64.515 107.752 64.962 107.789 ;
     RECT  67.215 106.301 67.497 107.833 ;
     RECT  66.492 107.833 67.497 107.885 ;
     RECT  91.515 105.629 91.89 108.175 ;
     RECT  41.868 107.789 43.542 108.509 ;
     RECT  41.868 108.509 43.398 108.557 ;
     RECT  91.116 108.175 91.89 108.557 ;
     RECT  41.868 108.557 43.197 113.995 ;
     RECT  91.515 108.557 91.89 114.421 ;
     RECT  41.76 113.995 43.197 114.523 ;
     RECT  41.436 114.523 43.197 114.575 ;
     RECT  91.515 114.421 92.142 114.619 ;
     RECT  91.515 114.619 92.358 114.893 ;
     RECT  66.06 117.247 66.078 117.293 ;
     RECT  36.252 117.895 36.27 117.931 ;
     RECT  5.115 93.479 5.397 118.021 ;
     RECT  33.192 118.021 33.282 118.057 ;
     RECT  32.115 2.413 32.397 118.075 ;
     RECT  33.156 118.057 33.282 118.075 ;
     RECT  34.815 93.389 35.097 118.093 ;
     RECT  32.115 118.075 33.282 118.121 ;
     RECT  36.18 117.931 36.27 118.123 ;
     RECT  3.492 118.021 3.51 118.129 ;
     RECT  33.264 118.121 33.282 118.157 ;
     RECT  7.815 93.389 8.097 118.165 ;
     RECT  34.815 118.093 35.442 118.165 ;
     RECT  36.18 118.123 36.414 118.165 ;
     RECT  37.515 99.185 38.79 118.165 ;
     RECT  39.528 104.693 40.497 118.165 ;
     RECT  2.415 90.347 2.697 118.201 ;
     RECT  3.492 118.129 3.582 118.201 ;
     RECT  7.2 118.165 8.097 118.201 ;
     RECT  2.415 118.201 3.582 118.219 ;
     RECT  0.108 118.075 0.126 118.229 ;
     RECT  5.115 118.021 5.49 118.291 ;
     RECT  37.515 118.165 40.497 118.315 ;
     RECT  2.16 118.219 3.582 118.319 ;
     RECT  6.552 118.201 8.097 118.319 ;
     RECT  5.115 118.291 5.778 118.399 ;
     RECT  4.68 118.399 5.778 118.459 ;
     RECT  4.536 118.459 5.778 118.471 ;
     RECT  2.304 118.319 2.79 118.499 ;
     RECT  34.815 118.165 36.414 118.561 ;
     RECT  7.815 118.319 8.097 118.597 ;
     RECT  8.964 118.561 8.982 118.597 ;
     RECT  34.815 118.561 36.522 118.597 ;
     RECT  7.815 118.597 8.982 118.697 ;
     RECT  37.44 118.315 40.497 118.705 ;
     RECT  34.815 118.597 36.594 118.741 ;
     RECT  37.332 118.705 40.497 118.741 ;
     RECT  3.852 118.471 5.778 118.831 ;
     RECT  6.552 118.319 7.038 118.831 ;
     RECT  13.215 93.281 13.497 118.831 ;
     RECT  21.315 92.909 21.597 118.831 ;
     RECT  24.015 2.413 24.297 118.843 ;
     RECT  22.608 118.555 22.626 118.859 ;
     RECT  13.104 118.831 13.497 118.877 ;
     RECT  21.204 118.831 21.597 118.877 ;
     RECT  34.815 118.741 40.497 118.931 ;
     RECT  41.868 114.575 43.197 118.939 ;
     RECT  14.832 118.843 14.85 118.973 ;
     RECT  30.78 118.093 30.798 118.973 ;
     RECT  23.904 118.843 24.297 119.101 ;
     RECT  0.144 118.987 0.162 119.117 ;
     RECT  7.815 118.697 8.658 119.129 ;
     RECT  3.852 118.831 7.038 119.173 ;
     RECT  7.815 119.129 8.55 119.173 ;
     RECT  41.832 118.939 43.197 119.173 ;
     RECT  3.852 119.173 8.55 119.227 ;
     RECT  23.364 119.101 24.297 119.273 ;
     RECT  30.852 119.209 30.87 119.309 ;
     RECT  2.304 118.499 2.697 119.407 ;
     RECT  3.456 119.227 8.55 119.407 ;
     RECT  2.304 119.407 8.55 119.551 ;
     RECT  34.815 118.931 38.79 119.713 ;
     RECT  39.528 118.931 40.497 119.713 ;
     RECT  34.815 119.713 40.497 119.749 ;
     RECT  34.776 119.749 40.497 119.789 ;
     RECT  2.268 119.551 8.55 119.837 ;
     RECT  41.76 119.173 43.197 119.947 ;
     RECT  86.115 100.139 86.397 119.983 ;
     RECT  87.48 114.583 87.498 119.983 ;
     RECT  91.515 114.893 91.854 120.011 ;
     RECT  32.115 118.121 32.397 120.091 ;
     RECT  33.12 119.173 33.138 120.091 ;
     RECT  2.415 119.837 8.55 120.209 ;
     RECT  9.288 120.055 9.306 120.209 ;
     RECT  30.78 119.983 30.798 120.209 ;
     RECT  32.115 120.091 33.138 120.209 ;
     RECT  34.812 119.789 40.497 120.209 ;
     RECT  32.115 120.209 33.102 120.281 ;
     RECT  5.076 120.209 8.55 120.325 ;
     RECT  1.152 119.659 1.17 120.389 ;
     RECT  5.076 120.325 9.162 120.479 ;
     RECT  5.076 120.479 9.126 120.551 ;
     RECT  34.815 120.209 40.497 120.595 ;
     RECT  41.724 119.947 43.197 120.595 ;
     RECT  9.072 120.551 9.126 120.623 ;
     RECT  2.415 120.209 4.014 120.991 ;
     RECT  5.076 120.551 8.262 120.991 ;
     RECT  0.108 120.379 0.126 121.243 ;
     RECT  48.315 105.899 48.597 121.261 ;
     RECT  0.108 121.243 0.162 121.289 ;
     RECT  48.315 121.261 48.978 121.441 ;
     RECT  48.315 121.441 49.014 121.595 ;
     RECT  9.108 120.623 9.126 121.639 ;
     RECT  2.415 120.991 8.262 121.711 ;
     RECT  2.415 121.711 8.334 121.739 ;
     RECT  7.815 121.739 8.334 121.801 ;
     RECT  9.072 121.639 9.126 121.801 ;
     RECT  2.415 121.739 6.966 121.963 ;
     RECT  2.304 121.963 6.966 122.009 ;
     RECT  2.415 122.009 6.966 122.045 ;
     RECT  7.815 121.801 9.126 122.071 ;
     RECT  4.356 122.045 6.966 122.099 ;
     RECT  0.108 121.289 0.126 122.251 ;
     RECT  7.815 122.071 9.306 122.251 ;
     RECT  0.108 122.251 0.342 122.429 ;
     RECT  7.815 122.251 9.342 122.521 ;
     RECT  34.815 120.595 43.197 122.521 ;
     RECT  7.74 122.521 9.342 122.611 ;
     RECT  0.108 122.429 0.126 122.669 ;
     RECT  4.356 122.099 5.994 122.717 ;
     RECT  7.74 122.611 9.378 122.909 ;
     RECT  2.415 122.045 3.618 123.053 ;
     RECT  6.84 122.099 6.858 123.061 ;
     RECT  6.804 123.061 6.966 123.101 ;
     RECT  91.515 120.011 91.797 123.115 ;
     RECT  94.215 105.161 94.497 123.331 ;
     RECT  93.744 123.331 94.497 123.389 ;
     RECT  91.515 123.115 92.214 123.449 ;
     RECT  34.776 122.521 43.197 123.493 ;
     RECT  7.815 122.909 8.838 123.593 ;
     RECT  91.515 123.449 91.926 123.629 ;
     RECT  34.776 123.493 43.254 123.691 ;
     RECT  34.56 123.691 43.254 123.773 ;
     RECT  4.356 122.717 4.374 123.791 ;
     RECT  7.815 123.593 8.514 123.899 ;
     RECT  5.115 122.717 5.994 124.169 ;
     RECT  30.78 123.763 30.798 124.169 ;
     RECT  95.904 124.219 95.922 124.375 ;
     RECT  6.948 123.101 6.966 124.439 ;
     RECT  94.215 123.389 94.497 124.507 ;
     RECT  75.315 105.935 75.597 124.573 ;
     RECT  94.104 124.507 94.497 124.603 ;
     RECT  75.24 124.573 75.597 124.609 ;
     RECT  93.672 124.603 94.497 124.651 ;
     RECT  95.76 124.375 95.922 124.651 ;
     RECT  74.124 124.645 74.142 124.681 ;
     RECT  90.648 124.507 90.666 124.685 ;
     RECT  5.115 124.169 5.742 124.709 ;
     RECT  74.124 124.681 74.286 124.799 ;
     RECT  3.6 123.053 3.618 124.979 ;
     RECT  7.815 123.899 8.097 125.035 ;
     RECT  93.672 124.651 95.922 125.117 ;
     RECT  93.672 125.117 95.778 125.179 ;
     RECT  75.024 124.609 75.597 125.185 ;
     RECT  7.815 125.035 8.19 125.221 ;
     RECT  74.88 125.185 75.597 125.221 ;
     RECT  93.276 125.179 95.778 125.261 ;
     RECT  91.515 123.629 91.797 125.311 ;
     RECT  93.276 125.261 95.742 125.311 ;
     RECT  7.815 125.221 8.514 125.339 ;
     RECT  74.88 125.221 75.834 125.419 ;
     RECT  34.776 123.773 43.254 125.609 ;
     RECT  90.612 125.563 90.63 125.707 ;
     RECT  74.016 125.371 74.034 125.725 ;
     RECT  73.728 125.725 74.034 125.753 ;
     RECT  74.88 125.419 75.87 125.761 ;
     RECT  90.612 125.707 90.774 125.761 ;
     RECT  91.515 125.311 95.742 125.761 ;
     RECT  83.415 100.499 83.697 125.947 ;
     RECT  74.88 125.761 75.906 125.959 ;
     RECT  76.644 124.609 76.662 125.959 ;
     RECT  44.676 125.995 44.694 126.121 ;
     RECT  45.615 106.093 45.897 126.121 ;
     RECT  90 125.761 95.742 126.121 ;
     RECT  83.196 125.947 83.697 126.157 ;
     RECT  44.676 126.121 45.897 126.173 ;
     RECT  74.628 125.959 76.662 126.193 ;
     RECT  78.015 96.989 78.297 126.193 ;
     RECT  44.676 126.173 44.694 126.221 ;
     RECT  88.815 101.039 89.097 126.229 ;
     RECT  34.815 125.609 43.254 126.391 ;
     RECT  88.815 126.229 89.19 126.391 ;
     RECT  89.964 126.121 95.742 126.391 ;
     RECT  82.944 126.157 83.697 126.419 ;
     RECT  73.728 125.753 73.746 126.535 ;
     RECT  74.628 126.193 78.297 126.535 ;
     RECT  86.115 119.983 87.498 126.563 ;
     RECT  53.715 106.093 53.997 126.571 ;
     RECT  34.815 126.391 43.326 126.769 ;
     RECT  56.415 106.093 56.697 126.805 ;
     RECT  72.615 106.093 72.897 126.805 ;
     RECT  73.728 126.535 78.297 126.805 ;
     RECT  34.815 126.769 43.578 126.841 ;
     RECT  53.715 126.571 54.378 126.841 ;
     RECT  56.415 126.805 57.042 126.841 ;
     RECT  72.615 126.805 78.297 126.845 ;
     RECT  72.615 126.845 73.638 126.959 ;
     RECT  74.412 126.845 78.297 126.959 ;
     RECT  55.908 126.841 57.042 126.967 ;
     RECT  55.908 126.967 57.546 126.989 ;
     RECT  88.815 126.391 95.742 126.989 ;
     RECT  34.776 126.841 43.578 126.995 ;
     RECT  72.615 126.959 73.494 126.995 ;
     RECT  53.715 126.841 54.738 127.031 ;
     RECT  56.415 126.989 57.546 127.039 ;
     RECT  56.415 127.039 57.798 127.085 ;
     RECT  45.615 126.173 45.897 127.187 ;
     RECT  48.315 121.595 48.597 127.187 ;
     RECT  51.015 105.899 51.297 127.187 ;
     RECT  56.415 127.085 57.546 127.187 ;
     RECT  59.115 106.093 59.397 127.187 ;
     RECT  61.815 106.093 62.097 127.187 ;
     RECT  64.515 107.789 64.797 127.187 ;
     RECT  67.215 107.885 67.497 127.187 ;
     RECT  69.915 106.093 70.197 127.187 ;
     RECT  72.615 126.995 72.897 127.187 ;
     RECT  74.556 126.959 78.297 127.237 ;
     RECT  74.556 127.237 78.678 127.265 ;
     RECT  53.715 127.031 54.378 127.277 ;
     RECT  57.348 127.187 57.546 127.277 ;
     RECT  74.736 127.265 78.678 127.337 ;
     RECT  57.528 127.277 57.546 127.409 ;
     RECT  82.656 127.237 82.674 127.409 ;
     RECT  90.72 126.989 95.742 127.435 ;
     RECT  45.615 127.187 45.705 127.457 ;
     RECT  48.315 127.187 48.405 127.457 ;
     RECT  51.015 127.187 51.105 127.457 ;
     RECT  53.715 127.277 53.805 127.457 ;
     RECT  56.415 127.187 56.505 127.457 ;
     RECT  59.115 127.187 59.205 127.457 ;
     RECT  61.815 127.187 61.905 127.457 ;
     RECT  64.515 127.187 64.605 127.457 ;
     RECT  67.215 127.187 67.305 127.457 ;
     RECT  69.915 127.187 70.005 127.457 ;
     RECT  72.615 127.187 72.705 127.457 ;
     RECT  34.776 126.995 43.362 127.499 ;
     RECT  88.815 126.989 89.982 127.499 ;
     RECT  90.72 127.435 95.778 127.565 ;
     RECT  74.736 127.337 78.297 127.571 ;
     RECT  34.776 127.499 43.146 127.679 ;
     RECT  91.116 127.565 95.778 127.867 ;
     RECT  88.815 127.499 89.946 127.901 ;
     RECT  91.116 127.867 95.85 128.011 ;
     RECT  5.115 124.709 5.397 128.149 ;
     RECT  5.115 128.149 5.598 128.251 ;
     RECT  5.115 128.251 5.958 128.461 ;
     RECT  34.815 127.679 43.146 128.461 ;
     RECT  86.115 126.563 86.397 128.461 ;
     RECT  91.116 128.011 95.922 128.551 ;
     RECT  86.115 128.461 86.67 128.615 ;
     RECT  32.115 120.281 32.397 128.659 ;
     RECT  4.356 128.425 4.374 128.683 ;
     RECT  5.115 128.461 6.282 128.683 ;
     RECT  4.356 128.683 6.282 128.687 ;
     RECT  2.415 123.053 2.697 128.731 ;
     RECT  3.42 128.551 3.438 128.731 ;
     RECT  4.356 128.687 5.958 128.731 ;
     RECT  32.115 128.659 33.102 128.759 ;
     RECT  90.828 128.551 95.922 128.759 ;
     RECT  7.815 125.339 8.097 128.827 ;
     RECT  91.08 128.759 95.922 128.885 ;
     RECT  6.696 128.731 6.786 128.929 ;
     RECT  2.34 128.731 2.697 128.965 ;
     RECT  3.42 128.731 5.958 128.965 ;
     RECT  30.888 128.929 30.906 129.001 ;
     RECT  34.704 128.461 43.146 129.001 ;
     RECT  88.815 127.901 89.91 129.005 ;
     RECT  2.34 128.965 5.958 129.019 ;
     RECT  2.304 129.019 5.958 129.119 ;
     RECT  6.696 128.929 6.858 129.119 ;
     RECT  9.324 128.929 9.342 129.119 ;
     RECT  30.852 129.001 30.906 129.119 ;
     RECT  91.116 128.885 95.922 129.119 ;
     RECT  2.304 129.119 2.862 129.149 ;
     RECT  91.116 129.119 95.814 129.155 ;
     RECT  0.54 128.893 0.558 129.197 ;
     RECT  7.815 128.827 8.37 129.199 ;
     RECT  91.116 129.155 94.986 129.227 ;
     RECT  30.888 129.119 30.906 129.263 ;
     RECT  91.116 129.227 94.497 129.425 ;
     RECT  3.924 129.119 5.958 129.469 ;
     RECT  34.668 129.001 43.146 129.6 ;
     RECT  75.096 127.571 78.297 129.6 ;
     RECT  7.02 129.199 8.37 129.659 ;
     RECT  95.724 129.155 95.814 129.659 ;
     RECT  0.144 129.499 0.162 129.739 ;
     RECT  2.415 129.149 2.862 129.929 ;
     RECT  3.924 129.469 6.246 129.929 ;
     RECT  3.924 129.929 5.994 129.979 ;
     RECT  0.108 129.739 0.162 130.171 ;
     RECT  34.668 129.6 78.297 130.351 ;
     RECT  30.78 130.243 30.798 130.379 ;
     RECT  7.164 129.659 8.37 130.441 ;
     RECT  7.092 130.441 8.37 130.459 ;
     RECT  86.115 128.615 86.397 130.459 ;
     RECT  9.36 130.315 9.378 130.469 ;
     RECT  34.272 130.351 78.297 130.505 ;
     RECT  91.26 129.425 94.497 130.555 ;
     RECT  2.415 129.929 2.697 130.603 ;
     RECT  91.224 130.555 94.497 130.603 ;
     RECT  3.456 129.979 5.994 130.613 ;
     RECT  6.912 130.459 8.37 130.621 ;
     RECT  2.304 130.603 2.697 130.649 ;
     RECT  80.715 65.747 80.997 130.651 ;
     RECT  6.912 130.621 8.586 130.711 ;
     RECT  3.456 130.613 5.922 130.739 ;
     RECT  34.416 130.505 78.297 130.747 ;
     RECT  34.416 130.747 78.318 130.843 ;
     RECT  86.076 130.459 86.397 130.843 ;
     RECT  2.415 130.649 2.697 130.855 ;
     RECT  3.456 130.739 5.742 130.855 ;
     RECT  0.108 130.171 0.198 130.885 ;
     RECT  6.84 130.711 8.622 130.919 ;
     RECT  86.076 130.843 86.454 130.919 ;
     RECT  0.108 130.885 0.558 130.925 ;
     RECT  80.388 130.651 80.997 131.009 ;
     RECT  88.815 129.005 89.802 131.017 ;
     RECT  90.54 130.603 94.497 131.017 ;
     RECT  34.416 130.843 78.426 131.045 ;
     RECT  6.876 130.919 8.622 131.069 ;
     RECT  34.815 131.045 78.426 131.069 ;
     RECT  7.056 131.069 8.622 131.125 ;
     RECT  0.108 130.925 0.162 131.279 ;
     RECT  7.056 131.125 9.306 131.279 ;
     RECT  7.056 131.279 9.234 131.351 ;
     RECT  88.815 131.017 94.497 131.405 ;
     RECT  0.144 131.279 0.162 131.501 ;
     RECT  30.78 131.431 30.798 131.549 ;
     RECT  83.415 126.419 83.697 131.557 ;
     RECT  86.115 130.919 86.454 131.557 ;
     RECT  83.415 131.557 84.366 131.645 ;
     RECT  86.115 131.557 86.67 131.657 ;
     RECT  2.415 130.855 5.742 131.729 ;
     RECT  2.415 131.729 3.006 131.755 ;
     RECT  34.815 131.069 78.297 131.791 ;
     RECT  2.304 131.755 3.006 131.819 ;
     RECT  34.776 131.791 78.297 131.863 ;
     RECT  3.996 131.729 5.742 131.999 ;
     RECT  34.272 131.863 78.297 131.999 ;
     RECT  4.248 131.999 5.742 132.061 ;
     RECT  7.056 131.351 8.586 132.061 ;
     RECT  7.02 132.061 8.586 132.205 ;
     RECT  34.596 131.999 78.297 132.235 ;
     RECT  79.488 128.731 79.506 132.235 ;
     RECT  88.815 131.405 89.097 132.235 ;
     RECT  7.02 132.205 9.162 132.359 ;
     RECT  90.288 131.405 94.497 132.359 ;
     RECT  86.115 131.657 86.397 132.379 ;
     RECT  34.596 132.235 79.506 132.395 ;
     RECT  4.248 132.061 6.174 132.403 ;
     RECT  87.48 126.563 87.498 132.403 ;
     RECT  34.815 132.395 79.506 132.413 ;
     RECT  7.092 132.359 9.162 132.431 ;
     RECT  30.852 132.403 30.87 132.503 ;
     RECT  86.115 132.379 86.418 132.509 ;
     RECT  2.415 131.819 3.006 132.539 ;
     RECT  91.476 132.359 94.497 132.701 ;
     RECT  4.248 132.403 6.21 132.781 ;
     RECT  88.704 132.235 89.097 132.797 ;
     RECT  4.248 132.781 6.246 132.871 ;
     RECT  86.115 132.509 86.397 132.871 ;
     RECT  79.488 132.413 79.506 132.989 ;
     RECT  86.04 132.871 86.397 133.037 ;
     RECT  87.192 132.403 87.498 133.037 ;
     RECT  7.092 132.431 8.097 133.043 ;
     RECT  90.288 132.359 90.666 133.079 ;
     RECT  34.815 132.413 78.678 133.277 ;
     RECT  34.815 133.277 78.297 134.107 ;
     RECT  34.668 134.107 78.297 134.131 ;
     RECT  34.272 134.131 78.297 134.221 ;
     RECT  4.248 132.871 6.282 134.249 ;
     RECT  4.572 134.249 6.282 134.527 ;
     RECT  4.572 134.527 6.318 134.555 ;
     RECT  34.2 134.221 78.297 134.909 ;
     RECT  9.144 132.431 9.162 134.969 ;
     RECT  34.2 134.909 76.662 135.131 ;
     RECT  36.216 135.131 76.662 135.203 ;
     RECT  5.115 134.555 6.318 135.239 ;
     RECT  5.115 135.239 5.778 135.473 ;
     RECT  34.2 135.131 35.097 135.509 ;
     RECT  36.504 135.203 76.662 136.061 ;
     RECT  36.504 136.061 41.31 136.139 ;
     RECT  42.228 136.061 76.662 136.157 ;
     RECT  77.544 134.909 78.297 136.157 ;
     RECT  42.444 136.157 76.662 136.349 ;
     RECT  37.152 136.139 41.31 136.787 ;
     RECT  77.616 136.157 78.297 137.065 ;
     RECT  77.544 137.065 78.297 137.117 ;
     RECT  42.732 136.349 76.662 137.405 ;
     RECT  37.515 136.787 41.31 137.563 ;
     RECT  37.515 137.563 41.886 137.641 ;
     RECT  88.815 132.797 89.097 138.271 ;
     RECT  92.7 132.701 94.497 138.283 ;
     RECT  87.48 133.037 87.498 138.371 ;
     RECT  95.904 138.271 95.922 138.415 ;
     RECT  86.115 133.037 86.397 138.451 ;
     RECT  88.815 138.271 89.298 138.451 ;
     RECT  90.288 133.079 90.306 138.451 ;
     RECT  37.515 137.641 42.174 138.541 ;
     RECT  86.115 138.451 86.67 138.541 ;
     RECT  91.476 132.701 91.797 138.541 ;
     RECT  92.7 138.283 94.626 138.541 ;
     RECT  86.115 138.541 86.742 138.568 ;
     RECT  95.76 138.415 95.922 138.619 ;
     RECT  91.404 138.541 94.626 138.685 ;
     RECT  95.76 138.619 95.994 138.713 ;
     RECT  91.404 138.685 95.022 138.721 ;
     RECT  95.76 138.713 95.814 138.721 ;
     RECT  86.115 138.568 86.994 138.749 ;
     RECT  37.188 138.541 42.174 138.875 ;
     RECT  76.392 137.405 76.662 138.875 ;
     RECT  88.815 138.451 89.478 138.883 ;
     RECT  90.216 138.451 90.306 138.883 ;
     RECT  88.815 138.883 90.306 138.991 ;
     RECT  77.58 137.117 78.297 139.081 ;
     RECT  43.056 137.405 75.192 139.085 ;
     RECT  88.815 138.991 90.378 139.099 ;
     RECT  91.404 138.721 95.814 139.099 ;
     RECT  43.092 139.085 75.192 139.153 ;
     RECT  76.644 138.875 76.662 139.189 ;
     RECT  76.644 139.189 76.698 139.195 ;
     RECT  77.436 139.081 78.297 139.195 ;
     RECT  43.092 139.153 75.51 139.291 ;
     RECT  87.768 138.451 87.786 139.649 ;
     RECT  43.092 139.291 75.834 139.771 ;
     RECT  76.644 139.195 78.297 139.771 ;
     RECT  87.732 139.675 87.75 139.801 ;
     RECT  87.516 139.801 87.75 139.829 ;
     RECT  37.515 138.875 42.174 139.867 ;
     RECT  43.092 139.771 78.297 139.867 ;
     RECT  87.516 139.829 87.534 139.949 ;
     RECT  37.515 139.867 78.297 139.955 ;
     RECT  88.815 139.099 95.814 140.011 ;
     RECT  88.815 140.011 95.922 140.189 ;
     RECT  86.115 138.749 86.397 140.431 ;
     RECT  97.452 139.675 97.47 140.531 ;
     RECT  98.172 140.683 98.19 140.701 ;
     RECT  86.115 140.431 86.67 140.729 ;
     RECT  98.172 140.701 98.262 140.729 ;
     RECT  98.244 140.729 98.262 140.765 ;
     RECT  88.815 140.189 95.778 140.801 ;
     RECT  37.515 139.955 75.618 140.909 ;
     RECT  42.444 140.909 75.618 141.115 ;
     RECT  76.392 139.955 78.297 141.115 ;
     RECT  90.072 140.801 95.778 141.305 ;
     RECT  37.515 140.909 41.598 141.539 ;
     RECT  97.452 141.547 97.47 141.881 ;
     RECT  42.444 141.115 78.297 141.889 ;
     RECT  88.815 140.801 89.097 142.027 ;
     RECT  90.288 141.305 95.778 142.075 ;
     RECT  88.815 142.027 89.442 142.171 ;
     RECT  90.288 142.075 95.994 142.171 ;
     RECT  88.815 142.171 95.994 142.259 ;
     RECT  90.288 142.259 95.994 142.349 ;
     RECT  37.515 141.539 41.454 142.393 ;
     RECT  42.444 141.889 78.93 142.393 ;
     RECT  83.415 131.645 83.697 142.771 ;
     RECT  37.515 142.393 78.93 142.889 ;
     RECT  88.815 142.259 89.442 142.889 ;
     RECT  90.288 142.349 95.922 142.889 ;
     RECT  90.648 142.889 95.922 142.925 ;
     RECT  97.452 142.699 97.47 142.961 ;
     RECT  83.415 142.771 84.186 143.453 ;
     RECT  90.648 142.925 95.814 143.537 ;
     RECT  90.648 143.537 92.538 143.549 ;
     RECT  93.348 143.537 95.814 143.707 ;
     RECT  93.348 143.707 95.922 143.744 ;
     RECT  93.348 143.744 95.778 144.481 ;
     RECT  93.348 144.481 95.814 144.509 ;
     RECT  95.796 144.509 95.814 144.557 ;
     RECT  37.515 142.889 75.762 146.904 ;
     RECT  93.348 144.509 95.022 147.083 ;
     RECT  70.812 146.904 70.83 147.197 ;
     RECT  93.348 147.083 94.497 147.245 ;
     RECT  91.368 143.549 92.538 147.281 ;
     RECT  37.515 146.904 43.146 147.317 ;
     RECT  91.515 147.281 92.538 147.317 ;
     RECT  75.024 146.904 75.762 147.479 ;
     RECT  94.176 147.245 94.497 147.659 ;
     RECT  93.348 147.245 93.366 147.749 ;
     RECT  37.515 147.317 41.886 147.785 ;
     RECT  41.868 147.785 41.886 147.821 ;
     RECT  91.515 147.317 92.502 147.821 ;
     RECT  76.68 142.889 78.93 147.857 ;
     RECT  37.515 147.785 40.95 147.893 ;
     RECT  76.68 147.857 77.238 147.893 ;
     RECT  75.024 147.479 75.51 147.929 ;
     RECT  37.515 147.893 40.77 148.019 ;
     RECT  77.22 147.893 77.238 148.019 ;
     RECT  91.515 147.821 91.998 148.469 ;
     RECT  43.092 147.317 43.146 148.756 ;
     RECT  50.796 148.441 50.814 148.909 ;
     RECT  78.015 147.857 78.93 148.937 ;
     RECT  50.508 148.909 50.814 148.945 ;
     RECT  43.092 148.756 43.182 149.023 ;
     RECT  50.508 148.945 50.886 149.023 ;
     RECT  75.024 147.929 75.33 149.023 ;
     RECT  50.508 149.023 51.105 149.099 ;
     RECT  75.024 149.023 75.405 149.135 ;
     RECT  42.915 149.023 43.182 149.293 ;
     RECT  45.615 149.023 45.705 149.293 ;
     RECT  48.315 149.023 48.405 149.293 ;
     RECT  51.015 149.099 51.105 149.293 ;
     RECT  53.715 149.023 53.805 149.293 ;
     RECT  56.415 149.023 56.505 149.293 ;
     RECT  59.115 149.023 59.205 149.293 ;
     RECT  61.815 149.023 61.905 149.293 ;
     RECT  64.515 149.023 64.605 149.293 ;
     RECT  67.215 149.023 67.305 149.293 ;
     RECT  69.915 149.023 70.005 149.293 ;
     RECT  72.615 149.023 72.705 149.293 ;
     RECT  75.315 149.135 75.405 149.293 ;
     RECT  37.515 148.019 40.497 167.333 ;
     RECT  37.515 167.333 39.366 167.459 ;
     RECT  37.515 167.459 39.186 167.837 ;
     RECT  2.415 132.539 2.697 168.227 ;
     RECT  5.115 135.473 5.397 168.227 ;
     RECT  7.815 133.043 8.097 168.227 ;
     RECT  10.515 89.231 10.797 168.227 ;
     RECT  13.215 118.877 13.497 168.227 ;
     RECT  15.915 89.843 16.197 168.227 ;
     RECT  18.615 92.669 18.897 168.227 ;
     RECT  21.315 118.877 21.597 168.227 ;
     RECT  24.015 119.273 24.297 168.227 ;
     RECT  26.715 2.413 26.997 168.227 ;
     RECT  29.415 92.573 29.697 168.227 ;
     RECT  32.115 128.759 32.397 168.227 ;
     RECT  34.815 135.509 35.097 168.227 ;
     RECT  40.215 167.333 40.497 168.227 ;
     RECT  42.915 149.293 43.197 168.227 ;
     RECT  45.615 149.293 45.897 168.227 ;
     RECT  48.315 149.293 48.597 168.227 ;
     RECT  51.015 149.293 51.297 168.227 ;
     RECT  53.715 149.293 53.997 168.227 ;
     RECT  56.415 149.293 56.697 168.227 ;
     RECT  59.115 149.293 59.397 168.227 ;
     RECT  61.815 149.293 62.097 168.227 ;
     RECT  64.515 149.293 64.797 168.227 ;
     RECT  67.215 149.293 67.497 168.227 ;
     RECT  69.915 149.293 70.197 168.227 ;
     RECT  72.615 149.293 72.897 168.227 ;
     RECT  75.315 149.293 75.597 168.227 ;
     RECT  78.015 148.937 78.297 168.227 ;
     RECT  80.715 131.009 80.997 168.227 ;
     RECT  83.415 143.453 83.697 168.227 ;
     RECT  86.115 140.729 86.397 168.227 ;
     RECT  88.815 142.889 89.097 168.227 ;
     RECT  91.515 148.469 91.797 168.227 ;
     RECT  94.215 147.659 94.497 168.227 ;
     RECT  2.415 168.227 2.505 168.497 ;
     RECT  5.115 168.227 5.205 168.497 ;
     RECT  7.815 168.227 7.905 168.497 ;
     RECT  10.515 168.227 10.605 168.497 ;
     RECT  13.215 168.227 13.305 168.497 ;
     RECT  15.915 168.227 16.005 168.497 ;
     RECT  18.615 168.227 18.705 168.497 ;
     RECT  21.315 168.227 21.405 168.497 ;
     RECT  24.015 168.227 24.105 168.497 ;
     RECT  26.715 168.227 26.805 168.497 ;
     RECT  29.415 168.227 29.505 168.497 ;
     RECT  32.115 168.227 32.205 168.497 ;
     RECT  34.815 168.227 34.905 168.497 ;
     RECT  37.515 167.837 39.006 168.497 ;
     RECT  40.215 168.227 40.305 168.497 ;
     RECT  42.915 168.227 43.005 168.497 ;
     RECT  45.615 168.227 45.705 168.497 ;
     RECT  48.315 168.227 48.405 168.497 ;
     RECT  51.015 168.227 51.105 168.497 ;
     RECT  53.715 168.227 53.805 168.497 ;
     RECT  56.415 168.227 56.505 168.497 ;
     RECT  59.115 168.227 59.205 168.497 ;
     RECT  61.815 168.227 61.905 168.497 ;
     RECT  64.515 168.227 64.605 168.497 ;
     RECT  67.215 168.227 67.305 168.497 ;
     RECT  69.915 168.227 70.005 168.497 ;
     RECT  72.615 168.227 72.705 168.497 ;
     RECT  75.315 168.227 75.405 168.497 ;
     RECT  78.015 168.227 78.105 168.497 ;
     RECT  80.715 168.227 80.805 168.497 ;
     RECT  83.415 168.227 83.505 168.497 ;
     RECT  86.115 168.227 86.205 168.497 ;
     RECT  88.815 168.227 88.905 168.497 ;
     RECT  91.515 168.227 91.605 168.497 ;
     RECT  94.215 168.227 94.305 168.497 ;
     RECT  38.124 168.497 39.006 170.395 ;
     RECT  37.836 170.395 39.006 170.603 ;
     RECT  37.836 170.603 37.908 170.609 ;
     RECT  37.926 170.603 38.016 170.609 ;
     RECT  38.034 170.603 38.124 170.609 ;
     RECT  38.142 170.603 38.232 170.609 ;
     RECT  38.25 170.603 38.34 170.609 ;
     RECT  38.358 170.603 38.448 170.609 ;
     RECT  38.466 170.603 38.556 170.609 ;
     RECT  38.574 170.603 38.664 170.609 ;
     RECT  38.682 170.603 38.772 170.609 ;
     RECT  38.79 170.603 38.88 170.609 ;
     RECT  38.898 170.603 38.988 170.609 ;
     RECT  37.926 170.609 38.016 170.621 ;
     RECT  38.034 170.609 38.124 170.621 ;
     RECT  38.142 170.609 38.232 170.621 ;
     RECT  38.25 170.609 38.34 170.621 ;
     RECT  38.358 170.609 38.448 170.621 ;
     RECT  38.466 170.609 38.556 170.621 ;
     RECT  38.574 170.609 38.664 170.621 ;
     RECT  38.682 170.609 38.772 170.621 ;
     RECT  38.79 170.609 38.88 170.621 ;
     RECT  38.898 170.609 38.988 170.621 ;
    LAYER M4 ;
     RECT  0.084 118.08 0.097 118.104 ;
     RECT  0.06 118.104 0.097 118.224 ;
     RECT  0.084 118.224 0.097 118.248 ;
     RECT  0.06 118.248 0.097 118.368 ;
     RECT  0.084 118.368 0.097 118.392 ;
     RECT  0.06 118.392 0.097 118.512 ;
     RECT  0.084 118.512 0.097 118.536 ;
     RECT  0.06 118.536 0.097 118.656 ;
     RECT  0.084 118.656 0.097 118.68 ;
     RECT  0.06 118.68 0.097 118.8 ;
     RECT  0.084 118.8 0.097 118.824 ;
     RECT  0.06 118.824 0.097 118.944 ;
     RECT  0.084 118.944 0.097 118.968 ;
     RECT  0.06 118.968 0.097 119.088 ;
     RECT  0.084 119.088 0.097 119.112 ;
     RECT  0.06 119.112 0.097 119.232 ;
     RECT  0.084 119.232 0.097 119.256 ;
     RECT  0.06 119.256 0.097 119.376 ;
     RECT  0.084 119.376 0.097 119.4 ;
     RECT  0.06 119.4 0.097 119.52 ;
     RECT  0.084 119.52 0.097 119.544 ;
     RECT  0.06 119.544 0.097 119.664 ;
     RECT  0.084 119.664 0.097 119.688 ;
     RECT  0.06 119.688 0.097 119.808 ;
     RECT  0.084 119.808 0.097 119.832 ;
     RECT  0.06 119.832 0.097 119.952 ;
     RECT  0.084 119.952 0.097 119.976 ;
     RECT  0.06 119.976 0.097 120.096 ;
     RECT  0.084 120.096 0.097 120.12 ;
     RECT  0.06 120.12 0.097 120.24 ;
     RECT  0.084 120.24 0.097 120.264 ;
     RECT  0.06 120.264 0.097 120.384 ;
     RECT  0.084 120.384 0.097 120.408 ;
     RECT  0.06 120.408 0.097 120.528 ;
     RECT  0.084 120.528 0.097 120.552 ;
     RECT  0.06 120.552 0.097 120.672 ;
     RECT  0.084 120.672 0.097 120.696 ;
     RECT  0.06 120.696 0.097 120.816 ;
     RECT  0.084 120.816 0.097 120.84 ;
     RECT  0.06 120.84 0.097 120.96 ;
     RECT  0.084 120.96 0.097 120.984 ;
     RECT  0.06 120.984 0.097 121.104 ;
     RECT  0.084 121.104 0.097 121.128 ;
     RECT  0.06 121.128 0.097 121.248 ;
     RECT  0.084 121.248 0.097 121.272 ;
     RECT  0.06 121.272 0.097 121.392 ;
     RECT  0.084 121.392 0.097 121.416 ;
     RECT  0.06 121.416 0.097 121.536 ;
     RECT  0.084 121.536 0.097 121.56 ;
     RECT  0.06 121.56 0.097 121.68 ;
     RECT  0.084 121.68 0.097 121.704 ;
     RECT  0.06 121.704 0.097 121.824 ;
     RECT  0.084 121.824 0.097 121.848 ;
     RECT  0.06 121.848 0.097 121.968 ;
     RECT  0.084 121.968 0.097 121.992 ;
     RECT  0.06 121.992 0.097 122.112 ;
     RECT  0.084 122.112 0.097 122.136 ;
     RECT  0.06 122.136 0.097 122.256 ;
     RECT  0.084 122.256 0.097 122.28 ;
     RECT  0.06 122.28 0.097 122.4 ;
     RECT  0.084 122.4 0.097 122.424 ;
     RECT  0.06 122.424 0.097 122.544 ;
     RECT  0.084 122.544 0.097 122.568 ;
     RECT  0.084 31.68 0.137 31.704 ;
     RECT  0.06 31.704 0.137 31.824 ;
     RECT  0.084 31.824 0.137 31.848 ;
     RECT  0.06 31.848 0.137 31.968 ;
     RECT  0.084 31.968 0.137 31.992 ;
     RECT  0.06 31.992 0.137 32.112 ;
     RECT  0.084 32.112 0.137 32.136 ;
     RECT  0.06 32.136 0.137 32.256 ;
     RECT  0.084 32.256 0.137 32.28 ;
     RECT  0.06 32.28 0.137 32.4 ;
     RECT  0.084 32.4 0.137 32.424 ;
     RECT  0.06 32.424 0.137 32.544 ;
     RECT  0.084 32.544 0.137 32.568 ;
     RECT  0.06 32.568 0.137 32.688 ;
     RECT  0.084 32.688 0.137 32.712 ;
     RECT  0.06 32.712 0.137 32.832 ;
     RECT  0.084 32.832 0.137 32.856 ;
     RECT  0.06 32.856 0.137 32.976 ;
     RECT  0.084 32.976 0.137 33 ;
     RECT  0.06 33 0.137 33.12 ;
     RECT  0.084 33.12 0.137 33.144 ;
     RECT  0.06 33.144 0.137 33.264 ;
     RECT  0.084 33.264 0.137 33.288 ;
     RECT  0.06 33.288 0.137 33.408 ;
     RECT  0.084 33.408 0.137 33.432 ;
     RECT  0.06 33.432 0.137 33.552 ;
     RECT  0.084 33.552 0.137 33.576 ;
     RECT  0.06 33.576 0.137 33.696 ;
     RECT  0.084 33.696 0.137 33.72 ;
     RECT  0.06 33.72 0.137 33.84 ;
     RECT  0.084 33.84 0.137 33.864 ;
     RECT  0.06 33.864 0.137 33.984 ;
     RECT  0.084 33.984 0.137 34.008 ;
     RECT  0.06 34.008 0.137 34.128 ;
     RECT  0.084 34.128 0.137 34.152 ;
     RECT  0.06 34.152 0.137 34.272 ;
     RECT  0.084 34.272 0.137 34.296 ;
     RECT  0.06 34.296 0.137 34.416 ;
     RECT  0.084 34.416 0.137 34.44 ;
     RECT  0.06 34.44 0.137 34.56 ;
     RECT  0.084 34.56 0.137 34.584 ;
     RECT  0.06 34.584 0.137 34.704 ;
     RECT  0.084 34.704 0.137 34.728 ;
     RECT  0.06 34.728 0.137 34.848 ;
     RECT  0.084 34.848 0.137 34.872 ;
     RECT  0.06 34.872 0.137 34.992 ;
     RECT  0.084 34.992 0.137 35.016 ;
     RECT  0.06 35.016 0.137 35.136 ;
     RECT  0.084 35.136 0.137 35.16 ;
     RECT  0.06 35.16 0.137 35.28 ;
     RECT  0.084 35.28 0.137 35.304 ;
     RECT  0.06 35.304 0.137 35.424 ;
     RECT  0.084 35.424 0.137 35.448 ;
     RECT  0.06 35.448 0.137 35.568 ;
     RECT  0.084 35.568 0.137 35.592 ;
     RECT  0.06 35.592 0.137 35.712 ;
     RECT  0.084 35.712 0.137 35.736 ;
     RECT  0.06 35.736 0.137 35.856 ;
     RECT  0.084 35.856 0.137 35.88 ;
     RECT  0.06 35.88 0.137 36 ;
     RECT  0.084 36 0.137 36.024 ;
     RECT  0.06 36.024 0.137 36.144 ;
     RECT  0.084 36.144 0.137 36.168 ;
     RECT  0.084 74.304 0.137 74.328 ;
     RECT  0.06 74.328 0.137 74.448 ;
     RECT  0.084 74.448 0.137 74.472 ;
     RECT  0.06 74.472 0.137 74.592 ;
     RECT  0.084 74.592 0.137 74.616 ;
     RECT  0.06 74.616 0.137 74.736 ;
     RECT  0.084 74.736 0.137 74.76 ;
     RECT  0.06 74.76 0.137 74.88 ;
     RECT  0.084 74.88 0.137 74.904 ;
     RECT  0.06 74.904 0.137 75.024 ;
     RECT  0.084 75.024 0.137 75.048 ;
     RECT  0.06 75.048 0.137 75.168 ;
     RECT  0.084 75.168 0.137 75.192 ;
     RECT  0.06 75.192 0.137 75.312 ;
     RECT  0.084 75.312 0.137 75.336 ;
     RECT  0.06 75.336 0.137 75.456 ;
     RECT  0.084 75.456 0.137 75.48 ;
     RECT  0.06 75.48 0.137 75.6 ;
     RECT  0.084 75.6 0.137 75.624 ;
     RECT  0.06 75.624 0.137 75.744 ;
     RECT  0.084 75.744 0.137 75.768 ;
     RECT  0.06 75.768 0.137 75.888 ;
     RECT  0.084 75.888 0.137 75.912 ;
     RECT  0.06 75.912 0.137 76.032 ;
     RECT  0.084 76.032 0.137 76.056 ;
     RECT  0.06 76.056 0.137 76.176 ;
     RECT  0.084 76.176 0.137 76.2 ;
     RECT  0.06 76.2 0.137 76.32 ;
     RECT  0.084 76.32 0.137 76.344 ;
     RECT  0.06 76.344 0.137 76.464 ;
     RECT  0.084 76.464 0.137 76.488 ;
     RECT  0.06 76.488 0.137 76.608 ;
     RECT  0.084 76.608 0.137 76.632 ;
     RECT  0.06 76.632 0.137 76.752 ;
     RECT  0.084 76.752 0.137 76.776 ;
     RECT  0.06 76.776 0.137 76.896 ;
     RECT  0.084 76.896 0.137 76.92 ;
     RECT  0.06 76.92 0.137 77.04 ;
     RECT  0.084 77.04 0.137 77.064 ;
     RECT  0.06 77.064 0.137 77.184 ;
     RECT  0.084 77.184 0.137 77.208 ;
     RECT  0.06 77.208 0.137 77.328 ;
     RECT  0.084 77.328 0.137 77.352 ;
     RECT  0.06 77.352 0.137 77.472 ;
     RECT  0.084 77.472 0.137 77.496 ;
     RECT  0.06 77.496 0.137 77.616 ;
     RECT  0.084 77.616 0.137 77.64 ;
     RECT  0.06 77.64 0.137 77.76 ;
     RECT  0.084 77.76 0.137 77.784 ;
     RECT  0.06 77.784 0.137 77.904 ;
     RECT  0.084 77.904 0.137 77.928 ;
     RECT  0.06 77.928 0.137 78.048 ;
     RECT  0.084 78.048 0.137 78.072 ;
     RECT  0.06 78.072 0.137 78.192 ;
     RECT  0.084 78.192 0.137 78.216 ;
     RECT  0.06 78.216 0.137 78.336 ;
     RECT  0.084 78.336 0.137 78.36 ;
     RECT  0.06 78.36 0.137 78.48 ;
     RECT  0.084 78.48 0.137 78.504 ;
     RECT  0.06 78.504 0.137 78.624 ;
     RECT  0.084 78.624 0.137 78.648 ;
     RECT  0.06 78.648 0.137 78.768 ;
     RECT  0.084 78.768 0.137 78.792 ;
     RECT  0.097 118.08 0.137 122.664 ;
     RECT  0.084 40.896 0.569 40.92 ;
     RECT  0.06 40.92 0.569 41.04 ;
     RECT  0.084 41.04 0.569 41.064 ;
     RECT  0.06 41.064 0.569 41.184 ;
     RECT  0.084 41.184 0.569 41.208 ;
     RECT  0.06 41.208 0.569 41.328 ;
     RECT  0.084 41.328 0.569 41.352 ;
     RECT  0.06 41.352 0.569 41.472 ;
     RECT  0.084 41.472 0.569 41.496 ;
     RECT  0.06 41.496 0.569 41.616 ;
     RECT  0.084 41.616 0.569 41.64 ;
     RECT  0.06 41.64 0.569 41.76 ;
     RECT  0.084 41.76 0.569 41.784 ;
     RECT  0.06 41.784 0.569 41.904 ;
     RECT  0.084 41.904 0.569 41.928 ;
     RECT  0.06 41.928 0.569 42.048 ;
     RECT  0.084 42.048 0.569 42.072 ;
     RECT  0.06 42.072 0.569 42.192 ;
     RECT  0.084 42.192 0.569 42.216 ;
     RECT  0.06 42.216 0.569 42.336 ;
     RECT  0.084 42.336 0.569 42.36 ;
     RECT  0.06 42.36 0.569 42.48 ;
     RECT  0.084 42.48 0.569 42.504 ;
     RECT  0.06 42.504 0.569 42.624 ;
     RECT  0.084 42.624 0.569 42.648 ;
     RECT  0.06 42.648 0.569 42.768 ;
     RECT  0.084 42.768 0.569 42.792 ;
     RECT  0.06 42.792 0.569 42.912 ;
     RECT  0.084 42.912 0.569 42.936 ;
     RECT  0.06 42.936 0.569 43.056 ;
     RECT  0.084 43.056 0.569 43.08 ;
     RECT  0.06 43.08 0.569 43.2 ;
     RECT  0.084 43.2 0.569 43.224 ;
     RECT  0.06 43.224 0.569 43.344 ;
     RECT  0.084 43.344 0.569 43.368 ;
     RECT  0.06 43.368 0.569 43.488 ;
     RECT  0.084 43.488 0.569 43.512 ;
     RECT  0.06 43.512 0.569 43.632 ;
     RECT  0.084 43.632 0.569 43.656 ;
     RECT  0.06 43.656 0.569 43.776 ;
     RECT  0.084 43.776 0.569 43.8 ;
     RECT  0.06 43.8 0.569 43.92 ;
     RECT  0.084 43.92 0.569 43.944 ;
     RECT  0.06 43.944 0.569 44.064 ;
     RECT  0.084 44.064 0.569 44.088 ;
     RECT  0.06 44.088 0.569 44.208 ;
     RECT  0.084 44.208 0.569 44.232 ;
     RECT  0.06 44.232 0.569 44.352 ;
     RECT  0.084 44.352 0.569 44.376 ;
     RECT  0.06 44.376 0.569 44.496 ;
     RECT  0.084 44.496 0.569 44.52 ;
     RECT  0.06 44.52 0.569 44.64 ;
     RECT  0.084 44.64 0.569 44.664 ;
     RECT  0.06 44.664 0.569 44.784 ;
     RECT  0.084 44.784 0.569 44.808 ;
     RECT  0.06 44.808 0.569 44.928 ;
     RECT  0.084 44.928 0.569 44.952 ;
     RECT  0.06 44.952 0.569 45.072 ;
     RECT  0.084 45.072 0.569 45.096 ;
     RECT  0.06 45.096 0.569 45.216 ;
     RECT  0.084 45.216 0.569 45.24 ;
     RECT  0.06 45.24 0.569 45.36 ;
     RECT  0.084 45.36 0.569 45.384 ;
     RECT  0.137 31.728 2.252 36.168 ;
     RECT  2.252 31.728 2.408 36.264 ;
     RECT  0.569 41.136 2.408 45.384 ;
     RECT  0.137 74.4 2.408 78.792 ;
     RECT  0.084 84.672 2.408 84.696 ;
     RECT  0.06 84.696 2.408 84.816 ;
     RECT  0.084 84.816 2.408 84.84 ;
     RECT  0.06 84.84 2.408 84.96 ;
     RECT  0.084 84.96 2.408 84.984 ;
     RECT  0.06 84.984 2.408 85.104 ;
     RECT  0.084 85.104 2.408 85.128 ;
     RECT  0.06 85.128 2.408 85.248 ;
     RECT  0.084 85.248 2.408 85.272 ;
     RECT  0.06 85.272 2.408 85.392 ;
     RECT  0.084 85.392 2.408 85.416 ;
     RECT  0.06 85.416 2.408 85.536 ;
     RECT  0.084 85.536 2.408 85.56 ;
     RECT  0.06 85.56 2.408 85.68 ;
     RECT  0.084 85.68 2.408 85.704 ;
     RECT  0.06 85.704 2.408 85.824 ;
     RECT  0.084 85.824 2.408 85.848 ;
     RECT  0.06 85.848 2.408 85.968 ;
     RECT  0.084 85.968 2.408 85.992 ;
     RECT  0.06 85.992 2.408 86.112 ;
     RECT  0.084 86.112 2.408 86.136 ;
     RECT  0.06 86.136 2.408 86.256 ;
     RECT  0.084 86.256 2.408 86.28 ;
     RECT  0.06 86.28 2.408 86.4 ;
     RECT  0.084 86.4 2.408 86.424 ;
     RECT  0.06 86.424 2.408 86.544 ;
     RECT  0.084 86.544 2.408 86.568 ;
     RECT  0.06 86.568 2.408 86.688 ;
     RECT  0.084 86.688 2.408 86.712 ;
     RECT  0.06 86.712 2.408 86.832 ;
     RECT  0.084 86.832 2.408 86.856 ;
     RECT  0.06 86.856 2.408 86.976 ;
     RECT  0.084 86.976 2.408 87 ;
     RECT  0.06 87 2.408 87.12 ;
     RECT  0.084 87.12 2.408 87.144 ;
     RECT  0.06 87.144 2.408 87.264 ;
     RECT  0.084 87.264 2.408 87.288 ;
     RECT  0.06 87.288 2.408 87.408 ;
     RECT  0.084 87.408 2.408 87.432 ;
     RECT  0.06 87.432 2.408 87.552 ;
     RECT  0.084 87.552 2.408 87.576 ;
     RECT  0.06 87.576 2.408 87.696 ;
     RECT  0.084 87.696 2.408 87.72 ;
     RECT  0.06 87.72 2.408 87.84 ;
     RECT  0.084 87.84 2.408 87.864 ;
     RECT  0.06 87.864 2.408 87.984 ;
     RECT  0.084 87.984 2.408 88.008 ;
     RECT  0.06 88.008 2.408 88.128 ;
     RECT  0.084 88.128 2.408 88.152 ;
     RECT  0.06 88.152 2.408 88.272 ;
     RECT  0.084 88.272 2.408 88.296 ;
     RECT  0.06 88.296 2.408 88.416 ;
     RECT  0.084 88.416 2.408 88.44 ;
     RECT  0.06 88.44 2.408 88.56 ;
     RECT  0.084 88.56 2.408 88.584 ;
     RECT  0.06 88.584 2.408 88.704 ;
     RECT  0.084 88.704 2.408 88.728 ;
     RECT  0.06 88.728 2.408 88.848 ;
     RECT  0.084 88.848 2.408 88.872 ;
     RECT  0.06 88.872 2.408 88.992 ;
     RECT  0.084 88.992 2.408 89.016 ;
     RECT  0.06 89.016 2.408 89.136 ;
     RECT  0.084 89.136 2.408 89.16 ;
     RECT  0.137 118.224 2.408 122.664 ;
     RECT  0.084 128.592 2.408 128.616 ;
     RECT  0.06 128.616 2.408 128.736 ;
     RECT  0.084 128.736 2.408 128.76 ;
     RECT  0.06 128.76 2.408 128.88 ;
     RECT  0.084 128.88 2.408 128.904 ;
     RECT  0.06 128.904 2.408 129.024 ;
     RECT  0.084 129.024 2.408 129.048 ;
     RECT  0.06 129.048 2.408 129.168 ;
     RECT  0.084 129.168 2.408 129.192 ;
     RECT  0.06 129.192 2.408 129.312 ;
     RECT  0.084 129.312 2.408 129.336 ;
     RECT  0.06 129.336 2.408 129.456 ;
     RECT  0.084 129.456 2.408 129.48 ;
     RECT  0.06 129.48 2.408 129.6 ;
     RECT  0.084 129.6 2.408 129.624 ;
     RECT  0.06 129.624 2.408 129.744 ;
     RECT  0.084 129.744 2.408 129.768 ;
     RECT  0.06 129.768 2.408 129.888 ;
     RECT  0.084 129.888 2.408 129.912 ;
     RECT  0.06 129.912 2.408 130.032 ;
     RECT  0.084 130.032 2.408 130.056 ;
     RECT  0.06 130.056 2.408 130.176 ;
     RECT  0.084 130.176 2.408 130.2 ;
     RECT  0.06 130.2 2.408 130.32 ;
     RECT  0.084 130.32 2.408 130.344 ;
     RECT  0.06 130.344 2.408 130.464 ;
     RECT  0.084 130.464 2.408 130.488 ;
     RECT  0.06 130.488 2.408 130.608 ;
     RECT  0.084 130.608 2.408 130.632 ;
     RECT  0.06 130.632 2.408 130.752 ;
     RECT  0.084 130.752 2.408 130.776 ;
     RECT  0.06 130.776 2.408 130.896 ;
     RECT  0.084 130.896 2.408 130.92 ;
     RECT  0.06 130.92 2.408 131.04 ;
     RECT  0.084 131.04 2.408 131.064 ;
     RECT  0.06 131.064 2.408 131.184 ;
     RECT  0.084 131.184 2.408 131.208 ;
     RECT  0.06 131.208 2.408 131.328 ;
     RECT  0.084 131.328 2.408 131.352 ;
     RECT  0.06 131.352 2.408 131.472 ;
     RECT  0.084 131.472 2.408 131.496 ;
     RECT  0.06 131.496 2.408 131.616 ;
     RECT  0.084 131.616 2.408 131.64 ;
     RECT  0.06 131.64 2.408 131.76 ;
     RECT  0.084 131.76 2.408 131.784 ;
     RECT  2.408 2.148 2.512 168.492 ;
     RECT  2.512 2.418 2.704 168.222 ;
     RECT  2.704 128.592 3.449 131.832 ;
     RECT  2.704 84.672 3.593 89.16 ;
     RECT  2.704 31.728 3.773 36.12 ;
     RECT  2.704 41.136 3.884 45.432 ;
     RECT  3.884 40.656 3.971 45.432 ;
     RECT  3.449 128.688 4.025 131.832 ;
     RECT  4.025 128.688 4.133 131.64 ;
     RECT  2.704 118.368 4.849 122.664 ;
     RECT  3.773 31.872 5.108 36.12 ;
     RECT  4.237 40.032 5.108 40.056 ;
     RECT  3.971 41.04 5.108 45.432 ;
     RECT  2.704 74.4 5.108 78.792 ;
     RECT  4.381 83.04 5.108 83.064 ;
     RECT  3.593 84.816 5.108 89.16 ;
     RECT  4.981 92.448 5.108 92.472 ;
     RECT  4.693 94.032 5.108 94.056 ;
     RECT  4.849 118.368 5.108 122.712 ;
     RECT  4.133 128.688 5.108 131.352 ;
     RECT  5.108 2.148 5.212 168.492 ;
     RECT  5.212 2.418 5.404 168.222 ;
     RECT  5.404 34.08 5.429 36.024 ;
     RECT  5.404 87.264 5.429 88.44 ;
     RECT  5.404 31.968 5.465 32.568 ;
     RECT  5.404 77.616 5.465 78.696 ;
     RECT  5.404 92.448 5.501 92.568 ;
     RECT  5.404 41.232 5.537 45.24 ;
     RECT  5.404 130.752 5.537 132.12 ;
     RECT  5.465 31.968 5.573 32.328 ;
     RECT  5.404 74.88 5.573 75.96 ;
     RECT  5.404 84.864 5.573 85.512 ;
     RECT  5.404 122.688 5.573 123.096 ;
     RECT  5.537 131.04 5.644 132.12 ;
     RECT  5.537 41.232 5.645 45.048 ;
     RECT  5.573 74.88 5.645 75.192 ;
     RECT  5.404 118.608 5.645 118.968 ;
     RECT  5.404 119.952 5.681 121.128 ;
     RECT  5.429 87.264 5.699 88.104 ;
     RECT  5.645 41.232 5.717 43.896 ;
     RECT  5.465 78.432 5.717 78.696 ;
     RECT  5.644 131.04 5.717 131.352 ;
     RECT  5.429 34.08 5.753 35.208 ;
     RECT  5.573 84.96 5.825 85.512 ;
     RECT  5.717 78.672 5.897 78.696 ;
     RECT  5.404 128.16 5.969 129.384 ;
     RECT  5.969 128.16 5.987 128.328 ;
     RECT  5.717 43.296 6.419 43.896 ;
     RECT  5.404 83.04 6.517 83.064 ;
     RECT  5.699 87.264 6.517 87.96 ;
     RECT  6.517 82.656 6.563 83.064 ;
     RECT  5.645 74.88 6.649 74.904 ;
     RECT  5.645 45.024 6.653 45.048 ;
     RECT  6.563 82.656 6.659 82.68 ;
     RECT  5.573 32.304 6.725 32.328 ;
     RECT  5.645 118.608 6.805 118.92 ;
     RECT  5.681 119.952 6.805 120.264 ;
     RECT  6.552 76.176 6.829 76.2 ;
     RECT  5.717 131.04 6.908 131.064 ;
     RECT  6.649 74.88 6.937 75.096 ;
     RECT  5.717 41.808 7.801 41.832 ;
     RECT  6.419 43.296 7.801 43.32 ;
     RECT  5.753 34.08 7.808 34.92 ;
     RECT  5.404 37.008 7.808 37.032 ;
     RECT  5.404 40.032 7.808 40.056 ;
     RECT  7.801 41.808 7.808 43.32 ;
     RECT  7.369 45.696 7.808 45.72 ;
     RECT  6.373 49.872 7.808 49.896 ;
     RECT  6.937 74.88 7.808 75.144 ;
     RECT  6.829 76.176 7.808 76.296 ;
     RECT  6.937 78.672 7.808 78.696 ;
     RECT  6.865 85.392 7.808 85.416 ;
     RECT  6.517 86.64 7.808 87.96 ;
     RECT  5.501 92.544 7.808 92.568 ;
     RECT  5.404 94.032 7.808 94.056 ;
     RECT  6.805 118.608 7.808 120.792 ;
     RECT  5.573 123.072 7.808 123.096 ;
     RECT  5.987 128.304 7.808 128.328 ;
     RECT  5.969 129.36 7.808 129.384 ;
     RECT  6.908 130.464 7.808 131.064 ;
     RECT  7.808 2.148 7.912 168.492 ;
     RECT  7.912 2.418 8.104 168.222 ;
     RECT  8.104 85.392 8.201 85.416 ;
     RECT  8.104 75.12 8.237 75.144 ;
     RECT  8.104 42.72 8.243 43.368 ;
     RECT  8.104 128.304 8.243 128.856 ;
     RECT  8.104 125.04 8.245 125.256 ;
     RECT  8.104 33.936 8.281 34.824 ;
     RECT  8.104 35.856 8.281 35.88 ;
     RECT  8.243 43.344 8.281 43.368 ;
     RECT  8.281 33.936 8.284 33.96 ;
     RECT  8.104 78.672 8.309 78.696 ;
     RECT  8.104 40.032 8.425 41.064 ;
     RECT  8.104 45.696 8.489 45.72 ;
     RECT  8.104 118.608 8.489 118.968 ;
     RECT  8.104 119.952 8.531 119.976 ;
     RECT  8.104 123.072 8.531 123.096 ;
     RECT  8.245 125.232 8.531 125.256 ;
     RECT  8.243 128.832 8.531 128.856 ;
     RECT  8.425 40.032 10.508 40.152 ;
     RECT  8.104 49.872 10.508 49.896 ;
     RECT  8.104 76.272 10.508 76.296 ;
     RECT  8.104 92.544 10.508 92.568 ;
     RECT  8.104 94.032 10.508 94.056 ;
     RECT  8.489 118.944 10.508 118.968 ;
     RECT  10.508 2.148 10.612 168.492 ;
     RECT  10.612 2.418 10.804 168.222 ;
     RECT  10.804 40.032 12.092 40.152 ;
     RECT  12.092 40.032 12.161 40.2 ;
     RECT  12.161 40.128 12.179 40.2 ;
     RECT  12.179 40.128 13.208 40.152 ;
     RECT  10.804 49.872 13.208 49.896 ;
     RECT  12.133 74.592 13.208 74.616 ;
     RECT  10.804 76.176 13.208 76.2 ;
     RECT  10.804 92.544 13.208 92.568 ;
     RECT  10.804 94.032 13.208 94.056 ;
     RECT  10.804 118.848 13.208 118.872 ;
     RECT  13.208 2.148 13.312 168.492 ;
     RECT  13.312 2.418 13.504 168.222 ;
     RECT  13.504 74.352 13.601 74.616 ;
     RECT  13.504 40.128 14.249 40.296 ;
     RECT  14.249 40.272 14.821 40.296 ;
     RECT  13.504 92.544 14.821 92.568 ;
     RECT  13.504 118.848 14.821 118.872 ;
     RECT  14.821 40.272 14.861 40.392 ;
     RECT  14.821 92.448 14.861 92.568 ;
     RECT  14.821 118.848 14.861 118.968 ;
     RECT  14.861 40.368 15.908 40.392 ;
     RECT  13.504 49.872 15.908 49.896 ;
     RECT  13.601 74.352 15.908 74.376 ;
     RECT  14.861 92.448 15.908 92.472 ;
     RECT  13.504 94.032 15.908 94.056 ;
     RECT  14.861 118.944 15.908 118.968 ;
     RECT  15.908 2.148 16.012 168.492 ;
     RECT  16.012 2.418 16.204 168.222 ;
     RECT  16.204 40.368 18.608 40.392 ;
     RECT  16.204 49.872 18.608 49.896 ;
     RECT  16.204 74.352 18.608 74.376 ;
     RECT  16.204 92.448 18.608 92.472 ;
     RECT  16.204 94.032 18.608 94.056 ;
     RECT  16.204 118.944 18.608 118.968 ;
     RECT  18.608 2.148 18.712 168.492 ;
     RECT  18.712 2.418 18.904 168.222 ;
     RECT  18.904 40.368 21.308 40.392 ;
     RECT  18.904 49.872 21.308 49.896 ;
     RECT  18.904 74.352 21.308 74.376 ;
     RECT  18.904 92.448 21.308 92.472 ;
     RECT  18.904 94.032 21.308 94.056 ;
     RECT  18.904 118.848 21.308 118.872 ;
     RECT  21.308 2.148 21.412 168.492 ;
     RECT  21.412 2.418 21.604 168.222 ;
     RECT  21.604 40.272 21.701 40.392 ;
     RECT  21.604 92.448 22.141 92.904 ;
     RECT  21.604 99.648 22.385 99.768 ;
     RECT  21.604 74.352 22.499 74.376 ;
     RECT  21.604 118.848 22.597 118.872 ;
     RECT  22.385 99.648 22.601 99.672 ;
     RECT  22.597 118.56 22.681 118.872 ;
     RECT  21.701 40.272 22.813 40.296 ;
     RECT  22.813 40.272 22.853 40.392 ;
     RECT  22.141 92.448 22.853 92.568 ;
     RECT  22.853 40.368 24.008 40.392 ;
     RECT  21.604 49.872 24.008 49.896 ;
     RECT  22.853 92.448 24.008 92.472 ;
     RECT  21.604 94.032 24.008 94.056 ;
     RECT  22.681 118.848 24.008 118.872 ;
     RECT  21.604 142.896 24.008 142.92 ;
     RECT  24.008 2.148 24.112 168.492 ;
     RECT  24.112 2.418 24.304 168.222 ;
     RECT  24.304 40.368 26.708 40.392 ;
     RECT  24.304 49.872 26.708 49.896 ;
     RECT  24.304 92.448 26.708 92.472 ;
     RECT  24.304 94.032 26.708 94.056 ;
     RECT  24.304 118.944 26.708 118.968 ;
     RECT  24.304 142.896 26.708 142.92 ;
     RECT  26.708 2.148 26.812 168.492 ;
     RECT  26.812 2.418 27.004 168.222 ;
     RECT  27.004 40.368 29.408 40.392 ;
     RECT  27.004 49.872 29.408 49.896 ;
     RECT  27.004 92.448 29.408 92.472 ;
     RECT  27.004 94.032 29.408 94.056 ;
     RECT  27.004 118.944 29.408 118.968 ;
     RECT  27.004 142.896 29.408 142.92 ;
     RECT  29.408 2.148 29.512 168.492 ;
     RECT  29.512 2.418 29.704 168.222 ;
     RECT  29.704 40.272 29.801 40.392 ;
     RECT  29.704 92.448 29.801 92.568 ;
     RECT  29.801 40.272 30.769 40.296 ;
     RECT  29.801 92.544 30.769 92.568 ;
     RECT  29.704 118.848 30.769 118.872 ;
     RECT  30.769 40.272 30.809 40.392 ;
     RECT  30.769 92.448 30.809 92.568 ;
     RECT  30.769 118.848 30.809 118.968 ;
     RECT  30.809 40.368 32.108 40.392 ;
     RECT  29.704 49.872 32.108 49.896 ;
     RECT  30.809 92.448 32.108 92.472 ;
     RECT  29.704 94.032 32.108 94.056 ;
     RECT  30.809 118.944 32.108 118.968 ;
     RECT  29.704 142.896 32.108 142.92 ;
     RECT  32.108 2.148 32.212 168.492 ;
     RECT  32.212 2.418 32.404 168.222 ;
     RECT  32.404 118.08 33.185 118.968 ;
     RECT  33.185 118.944 34.765 118.968 ;
     RECT  32.404 40.368 34.808 40.392 ;
     RECT  32.404 49.872 34.808 49.896 ;
     RECT  32.404 92.448 34.808 92.472 ;
     RECT  32.404 94.032 34.808 94.056 ;
     RECT  34.765 118.944 34.808 119.784 ;
     RECT  34.549 123.744 34.808 123.768 ;
     RECT  34.765 127.632 34.808 127.656 ;
     RECT  34.657 129.12 34.808 129.144 ;
     RECT  34.333 131.904 34.808 131.928 ;
     RECT  34.657 134.112 34.808 134.136 ;
     RECT  32.404 142.896 34.808 142.92 ;
     RECT  34.808 2.148 34.912 168.492 ;
     RECT  34.912 2.418 35.104 168.222 ;
     RECT  35.104 118.128 35.345 122.136 ;
     RECT  35.104 126.576 35.404 128.136 ;
     RECT  35.345 120.576 35.411 122.136 ;
     RECT  35.104 134.112 35.453 134.568 ;
     RECT  35.104 131.232 35.569 132.84 ;
     RECT  35.104 129.12 35.597 129.912 ;
     RECT  35.404 128.112 35.633 128.136 ;
     RECT  35.597 129.888 35.747 129.912 ;
     RECT  35.453 134.496 35.777 134.568 ;
     RECT  35.411 120.576 36.065 120.6 ;
     RECT  35.345 118.128 36.133 119.256 ;
     RECT  35.411 121.728 36.133 122.136 ;
     RECT  35.777 134.544 36.137 134.568 ;
     RECT  36.133 117.264 36.425 119.256 ;
     RECT  36.133 121.728 36.457 122.376 ;
     RECT  35.104 123.648 36.457 124.824 ;
     RECT  36.457 120.816 36.533 124.824 ;
     RECT  36.425 118.32 36.661 119.256 ;
     RECT  35.404 126.576 36.709 127.08 ;
     RECT  35.569 131.232 36.716 132.216 ;
     RECT  36.709 126.576 36.781 127.656 ;
     RECT  36.781 126.192 36.817 127.656 ;
     RECT  36.277 128.784 36.817 128.808 ;
     RECT  36.817 126.192 36.925 128.808 ;
     RECT  36.925 134.352 37.141 134.376 ;
     RECT  36.493 135.84 37.141 135.864 ;
     RECT  36.925 126.192 37.205 128.856 ;
     RECT  36.716 131.232 37.357 132.792 ;
     RECT  36.661 118.32 37.381 119.544 ;
     RECT  35.104 40.368 37.508 40.392 ;
     RECT  35.104 49.872 37.508 49.896 ;
     RECT  35.104 92.448 37.508 92.472 ;
     RECT  35.104 94.032 37.508 94.056 ;
     RECT  37.381 97.92 37.508 98.664 ;
     RECT  37.381 114.816 37.508 114.84 ;
     RECT  36.425 117.264 37.508 117.288 ;
     RECT  37.381 118.32 37.508 119.736 ;
     RECT  36.533 120.816 37.508 123.192 ;
     RECT  36.533 124.224 37.508 124.824 ;
     RECT  37.205 126.192 37.508 129.432 ;
     RECT  37.357 131.232 37.508 132.936 ;
     RECT  37.141 134.352 37.508 135.864 ;
     RECT  35.104 142.896 37.508 142.92 ;
     RECT  37.508 2.148 37.612 168.492 ;
     RECT  37.612 2.418 37.804 168.222 ;
     RECT  37.804 97.92 37.865 97.944 ;
     RECT  37.804 117.264 37.901 119.736 ;
     RECT  37.825 170.4 37.957 170.424 ;
     RECT  37.804 121.104 37.973 122.232 ;
     RECT  37.804 114.816 38.003 115.128 ;
     RECT  37.804 128.832 38.003 137.352 ;
     RECT  37.957 170.4 38.044 170.52 ;
     RECT  38.003 114.816 38.045 114.84 ;
     RECT  38.003 128.832 38.081 133.416 ;
     RECT  37.804 145.344 38.099 148.488 ;
     RECT  37.804 164.256 38.099 166.104 ;
     RECT  38.044 170.4 38.147 170.424 ;
     RECT  38.099 147.264 38.195 148.488 ;
     RECT  37.804 140.208 38.225 141.288 ;
     RECT  38.081 132.672 38.333 133.416 ;
     RECT  38.225 140.208 38.339 141.192 ;
     RECT  38.099 145.344 38.339 145.896 ;
     RECT  37.804 159.648 38.339 161.16 ;
     RECT  38.339 140.208 38.377 141 ;
     RECT  38.339 145.344 38.377 145.368 ;
     RECT  37.804 150.48 38.377 151.032 ;
     RECT  38.099 165.168 38.387 166.104 ;
     RECT  37.804 167.52 38.413 167.592 ;
     RECT  38.377 140.208 38.435 140.52 ;
     RECT  38.195 147.408 38.435 148.488 ;
     RECT  37.804 52.272 38.483 53.112 ;
     RECT  38.081 128.832 38.483 131.64 ;
     RECT  38.377 151.008 38.483 151.032 ;
     RECT  37.804 155.808 38.513 156.168 ;
     RECT  37.901 117.264 38.549 118.968 ;
     RECT  38.387 165.84 38.621 166.104 ;
     RECT  38.003 134.448 38.657 137.352 ;
     RECT  37.804 142.512 38.675 143.976 ;
     RECT  38.435 148.224 38.675 148.488 ;
     RECT  38.339 159.648 38.685 160.44 ;
     RECT  38.333 133.392 38.765 133.416 ;
     RECT  38.513 156.144 38.771 156.168 ;
     RECT  38.685 160.416 38.771 160.44 ;
     RECT  37.804 92.448 38.797 92.472 ;
     RECT  37.804 93.6 38.797 94.056 ;
     RECT  38.675 143.04 38.801 143.976 ;
     RECT  38.413 167.52 38.801 167.544 ;
     RECT  37.804 95.952 38.819 96.936 ;
     RECT  38.819 96.192 38.845 96.936 ;
     RECT  37.804 138.576 38.905 138.6 ;
     RECT  38.797 123.696 38.909 123.72 ;
     RECT  38.905 138.528 38.941 138.6 ;
     RECT  38.657 134.448 38.981 134.472 ;
     RECT  37.804 91.344 39.049 91.368 ;
     RECT  38.797 92.448 39.049 94.056 ;
     RECT  38.483 131.616 39.049 131.64 ;
     RECT  38.621 165.84 39.059 165.864 ;
     RECT  38.483 128.832 39.077 130.2 ;
     RECT  37.804 49.872 39.121 51.24 ;
     RECT  37.804 126.144 39.121 127.08 ;
     RECT  39.077 128.208 39.121 130.2 ;
     RECT  39.121 126.144 39.161 130.2 ;
     RECT  38.833 48.192 39.337 48.216 ;
     RECT  38.657 136.704 39.349 137.352 ;
     RECT  38.941 138.528 39.349 138.744 ;
     RECT  39.337 48 39.373 48.216 ;
     RECT  38.435 140.496 39.404 140.52 ;
     RECT  39.373 47.904 39.409 48.216 ;
     RECT  39.121 49.872 39.409 51.288 ;
     RECT  39.404 140.496 39.445 140.76 ;
     RECT  39.121 89.52 39.481 89.544 ;
     RECT  37.973 121.104 39.553 121.464 ;
     RECT  38.549 118.944 39.589 118.968 ;
     RECT  38.941 87.792 39.661 87.912 ;
     RECT  39.481 89.376 39.661 89.544 ;
     RECT  39.049 91.344 39.697 94.056 ;
     RECT  39.013 83.76 39.733 83.784 ;
     RECT  39.409 45.024 39.805 45.048 ;
     RECT  39.553 120.864 39.805 121.464 ;
     RECT  39.733 106.896 39.813 106.92 ;
     RECT  39.161 126.144 39.829 127.8 ;
     RECT  39.805 45.024 39.877 45.816 ;
     RECT  39.841 46.848 39.877 46.872 ;
     RECT  39.661 87.792 39.913 89.544 ;
     RECT  39.805 120.864 39.913 121.656 ;
     RECT  39.877 45.024 39.925 46.872 ;
     RECT  39.409 47.904 39.925 51.288 ;
     RECT  39.925 45.024 39.98 51.288 ;
     RECT  39.349 123.216 39.985 123.24 ;
     RECT  38.905 124.704 39.985 124.728 ;
     RECT  39.349 136.704 40.069 139.128 ;
     RECT  37.804 40.368 40.208 40.392 ;
     RECT  39.98 44.976 40.208 51.288 ;
     RECT  38.483 53.088 40.208 53.112 ;
     RECT  39.733 83.76 40.208 84.12 ;
     RECT  39.913 87.792 40.208 90.264 ;
     RECT  39.697 91.344 40.208 94.68 ;
     RECT  38.845 96.192 40.208 96.216 ;
     RECT  39.813 106.896 40.208 107.112 ;
     RECT  38.549 117.264 40.208 117.288 ;
     RECT  39.589 118.56 40.208 118.968 ;
     RECT  39.913 120.864 40.208 121.896 ;
     RECT  39.985 123.024 40.208 124.728 ;
     RECT  39.829 125.904 40.208 127.8 ;
     RECT  39.161 128.832 40.208 130.008 ;
     RECT  39.049 131.616 40.208 132.168 ;
     RECT  40.093 134.256 40.208 134.28 ;
     RECT  40.069 136.176 40.208 139.128 ;
     RECT  39.445 140.496 40.208 141.384 ;
     RECT  38.801 143.04 40.208 143.064 ;
     RECT  38.675 148.224 40.208 148.248 ;
     RECT  40.208 2.148 40.312 168.492 ;
     RECT  40.312 2.418 40.504 168.222 ;
     RECT  40.504 125.232 40.643 126.216 ;
     RECT  40.504 129.36 40.673 129.96 ;
     RECT  40.504 142.512 40.853 143.64 ;
     RECT  40.504 137.952 40.925 140.76 ;
     RECT  40.504 101.232 40.931 101.256 ;
     RECT  40.504 55.248 40.933 55.272 ;
     RECT  40.853 143.616 40.979 143.64 ;
     RECT  40.504 146.976 40.997 147.24 ;
     RECT  40.504 44.448 41.033 51.48 ;
     RECT  40.853 142.512 41.033 142.536 ;
     RECT  40.504 127.776 41.429 127.8 ;
     RECT  40.504 114.528 41.465 114.552 ;
     RECT  40.504 106.896 41.507 107.112 ;
     RECT  40.504 87.936 41.569 93.912 ;
     RECT  41.033 44.736 41.605 51.48 ;
     RECT  40.504 52.704 41.605 53.784 ;
     RECT  41.569 87.648 41.605 93.912 ;
     RECT  40.504 95.04 41.605 96.984 ;
     RECT  40.504 134.208 41.641 136.248 ;
     RECT  41.605 132.096 41.677 132.12 ;
     RECT  40.643 126.048 41.713 126.216 ;
     RECT  41.641 133.92 41.713 136.248 ;
     RECT  40.925 137.952 41.713 140.184 ;
     RECT  40.504 83.76 41.749 84.12 ;
     RECT  41.677 132 41.749 132.12 ;
     RECT  41.749 131.52 41.785 132.12 ;
     RECT  41.713 133.44 41.785 136.248 ;
     RECT  41.749 114 41.833 114.024 ;
     RECT  41.713 137.76 41.857 140.184 ;
     RECT  41.713 126.048 41.893 126.552 ;
     RECT  40.504 120.72 41.897 123.912 ;
     RECT  41.785 131.52 41.989 136.248 ;
     RECT  41.897 120.72 42.037 122.856 ;
     RECT  41.941 127.632 42.041 127.656 ;
     RECT  41.989 131.328 42.073 136.248 ;
     RECT  42.029 124.128 42.085 124.152 ;
     RECT  42.073 130.848 42.109 136.248 ;
     RECT  41.605 87.648 42.145 96.984 ;
     RECT  40.673 129.36 42.229 129.384 ;
     RECT  41.893 126 42.289 126.552 ;
     RECT  42.109 130.56 42.325 136.248 ;
     RECT  42.229 128.736 42.371 129.384 ;
     RECT  42.325 130.512 42.433 136.248 ;
     RECT  40.504 60.576 42.469 60.6 ;
     RECT  41.749 83.568 42.469 84.12 ;
     RECT  42.145 87.36 42.517 96.984 ;
     RECT  42.289 125.424 42.517 126.552 ;
     RECT  41.605 44.736 42.613 53.784 ;
     RECT  42.469 82.656 42.613 84.12 ;
     RECT  40.504 43.104 42.661 43.128 ;
     RECT  42.613 44.16 42.661 53.784 ;
     RECT  42.565 64.704 42.661 64.728 ;
     RECT  42.613 107.28 42.709 107.304 ;
     RECT  42.433 130.512 42.709 136.344 ;
     RECT  42.709 130.368 42.721 136.344 ;
     RECT  41.857 137.568 42.721 140.184 ;
     RECT  42.661 64.608 42.757 64.728 ;
     RECT  42.371 128.832 42.761 129.384 ;
     RECT  42.613 127.584 42.833 127.608 ;
     RECT  42.421 40.56 42.908 40.584 ;
     RECT  42.757 64.608 42.908 64.968 ;
     RECT  42.613 82.656 42.908 84.36 ;
     RECT  42.709 107.28 42.908 108.216 ;
     RECT  40.504 117.264 42.908 117.288 ;
     RECT  42.037 120.288 42.908 122.856 ;
     RECT  42.085 124.128 42.908 124.248 ;
     RECT  42.517 125.376 42.908 126.552 ;
     RECT  42.908 2.148 43.012 41.052 ;
     RECT  42.908 62.628 43.012 84.36 ;
     RECT  42.908 105.828 43.012 127.452 ;
     RECT  42.908 149.028 43.012 168.492 ;
     RECT  42.761 129.36 43.081 129.384 ;
     RECT  42.721 130.368 43.081 140.184 ;
     RECT  43.012 2.418 43.204 40.782 ;
     RECT  43.012 62.898 43.204 84.36 ;
     RECT  43.012 106.098 43.204 127.182 ;
     RECT  43.012 149.298 43.204 168.222 ;
     RECT  43.204 64.608 43.229 64.968 ;
     RECT  43.204 107.28 43.265 108.552 ;
     RECT  43.204 126.144 43.265 126.456 ;
     RECT  42.661 43.104 43.272 53.784 ;
     RECT  42.469 60.576 43.272 61.08 ;
     RECT  42.517 87.168 43.272 96.984 ;
     RECT  40.504 103.824 43.272 103.848 ;
     RECT  43.081 129.36 43.272 140.184 ;
     RECT  40.997 147.072 43.272 147.24 ;
     RECT  43.229 64.608 43.331 64.872 ;
     RECT  43.265 108.192 43.409 108.552 ;
     RECT  43.331 64.608 43.553 64.728 ;
     RECT  43.204 83.568 43.553 84.36 ;
     RECT  43.265 126.144 44.665 126.216 ;
     RECT  43.204 40.56 45.608 40.584 ;
     RECT  43.553 83.76 45.608 84.12 ;
     RECT  43.204 117.264 45.608 117.288 ;
     RECT  43.204 121.104 45.608 121.128 ;
     RECT  44.665 126 45.608 126.216 ;
     RECT  45.608 2.148 45.712 41.052 ;
     RECT  45.608 62.628 45.712 84.252 ;
     RECT  45.608 105.828 45.712 127.452 ;
     RECT  45.608 149.028 45.712 168.492 ;
     RECT  45.712 2.418 45.904 40.872 ;
     RECT  45.712 62.898 45.904 84.12 ;
     RECT  45.712 106.098 45.904 127.182 ;
     RECT  45.712 149.298 45.904 168.222 ;
     RECT  45.904 40.56 46.433 40.872 ;
     RECT  45.904 83.76 46.753 84.12 ;
     RECT  46.433 40.848 48.308 40.872 ;
     RECT  46.753 83.76 48.308 84.168 ;
     RECT  45.904 117.264 48.308 117.288 ;
     RECT  45.904 121.104 48.308 121.128 ;
     RECT  45.904 126 48.308 126.024 ;
     RECT  48.308 2.148 48.412 41.052 ;
     RECT  48.308 62.628 48.412 84.252 ;
     RECT  48.308 105.828 48.412 127.452 ;
     RECT  48.308 149.028 48.412 168.492 ;
     RECT  48.412 2.418 48.604 40.872 ;
     RECT  48.412 62.898 48.604 84.168 ;
     RECT  48.412 106.098 48.604 127.182 ;
     RECT  48.412 149.298 48.604 168.222 ;
     RECT  48.604 121.104 48.947 121.56 ;
     RECT  48.947 121.392 48.989 121.56 ;
     RECT  48.604 126 48.995 126.264 ;
     RECT  48.989 121.392 49.033 121.416 ;
     RECT  48.604 40.848 51.008 40.872 ;
     RECT  48.604 83.76 51.008 84.168 ;
     RECT  48.604 117.264 51.008 117.288 ;
     RECT  48.995 126.24 51.008 126.264 ;
     RECT  51.008 2.148 51.112 41.052 ;
     RECT  51.008 62.628 51.112 84.252 ;
     RECT  51.008 105.828 51.112 127.452 ;
     RECT  51.008 149.028 51.112 168.492 ;
     RECT  51.112 2.418 51.304 40.872 ;
     RECT  51.112 62.898 51.304 84.168 ;
     RECT  51.112 106.098 51.304 127.182 ;
     RECT  51.112 149.298 51.304 168.222 ;
     RECT  51.304 40.848 53.708 40.872 ;
     RECT  51.304 83.76 53.708 84.168 ;
     RECT  51.304 117.264 53.708 117.288 ;
     RECT  51.304 126.24 53.708 126.264 ;
     RECT  53.708 2.148 53.812 41.052 ;
     RECT  53.708 62.628 53.812 84.252 ;
     RECT  53.708 105.828 53.812 127.452 ;
     RECT  53.708 149.028 53.812 168.492 ;
     RECT  53.812 2.418 54.004 40.872 ;
     RECT  53.812 62.898 54.004 84.168 ;
     RECT  53.812 106.098 54.004 127.272 ;
     RECT  53.812 149.298 54.004 168.222 ;
     RECT  54.004 126.24 54.371 127.272 ;
     RECT  54.371 126.576 54.389 127.272 ;
     RECT  54.004 40.848 56.408 40.872 ;
     RECT  54.004 83.76 56.408 84.168 ;
     RECT  54.004 117.264 56.408 117.288 ;
     RECT  54.389 126.96 56.408 127.272 ;
     RECT  56.408 2.148 56.512 41.052 ;
     RECT  56.408 62.628 56.512 84.252 ;
     RECT  56.408 105.828 56.512 127.452 ;
     RECT  56.408 149.028 56.512 168.492 ;
     RECT  56.512 2.418 56.704 40.872 ;
     RECT  56.512 62.898 56.704 84.168 ;
     RECT  56.512 106.098 56.704 127.272 ;
     RECT  56.512 149.298 56.704 168.222 ;
     RECT  56.704 126.96 57.377 127.272 ;
     RECT  56.704 40.56 59.108 40.872 ;
     RECT  56.704 83.76 59.108 84.168 ;
     RECT  56.704 117.264 59.108 117.288 ;
     RECT  57.377 126.96 59.108 127.08 ;
     RECT  59.108 2.148 59.212 41.052 ;
     RECT  59.108 62.628 59.212 84.252 ;
     RECT  59.108 105.828 59.212 127.452 ;
     RECT  59.108 149.028 59.212 168.492 ;
     RECT  59.212 2.418 59.404 40.872 ;
     RECT  59.212 62.898 59.404 84.168 ;
     RECT  59.212 106.098 59.404 127.182 ;
     RECT  59.212 149.298 59.404 168.222 ;
     RECT  59.404 40.56 61.808 40.872 ;
     RECT  59.404 83.76 61.808 84.168 ;
     RECT  59.404 117.264 61.808 117.288 ;
     RECT  59.404 126.96 61.808 127.08 ;
     RECT  61.808 2.148 61.912 41.052 ;
     RECT  61.808 62.628 61.912 84.252 ;
     RECT  61.808 105.828 61.912 127.452 ;
     RECT  61.808 149.028 61.912 168.492 ;
     RECT  61.912 2.418 62.104 40.872 ;
     RECT  61.912 62.898 62.104 84.168 ;
     RECT  61.912 106.098 62.104 127.182 ;
     RECT  61.912 149.298 62.104 168.222 ;
     RECT  62.104 40.56 64.508 40.872 ;
     RECT  62.104 83.76 64.508 84.168 ;
     RECT  62.104 117.264 64.508 117.288 ;
     RECT  62.104 126.96 64.508 127.08 ;
     RECT  64.508 2.148 64.612 41.052 ;
     RECT  64.508 62.628 64.612 84.252 ;
     RECT  64.508 105.828 64.612 127.452 ;
     RECT  64.508 149.028 64.612 168.492 ;
     RECT  64.612 2.418 64.804 41.016 ;
     RECT  64.612 62.898 64.804 84.168 ;
     RECT  64.612 105.828 64.804 127.182 ;
     RECT  64.612 149.298 64.804 168.222 ;
     RECT  64.804 105.828 64.933 106.296 ;
     RECT  64.804 117.072 64.979 117.288 ;
     RECT  64.804 126.96 64.979 127.08 ;
     RECT  64.804 107.76 65.017 107.88 ;
     RECT  64.804 40.56 65.125 41.016 ;
     RECT  64.933 105.456 65.267 106.296 ;
     RECT  64.804 83.664 65.305 84.168 ;
     RECT  64.804 78.096 65.809 78.12 ;
     RECT  65.305 83.76 65.981 84.168 ;
     RECT  65.125 40.56 67.208 40.872 ;
     RECT  64.804 65.712 67.208 65.736 ;
     RECT  66.517 75.456 67.208 75.48 ;
     RECT  66.697 78.048 67.208 78.072 ;
     RECT  65.981 83.76 67.208 84.072 ;
     RECT  65.267 105.984 67.208 106.296 ;
     RECT  65.017 107.856 67.208 107.88 ;
     RECT  64.979 117.264 67.208 117.288 ;
     RECT  64.979 126.96 67.208 126.984 ;
     RECT  67.208 2.148 67.312 41.052 ;
     RECT  67.208 62.628 67.312 84.252 ;
     RECT  67.208 105.828 67.312 127.452 ;
     RECT  67.208 149.028 67.312 168.492 ;
     RECT  67.312 2.418 67.504 40.872 ;
     RECT  67.312 62.898 67.504 84.072 ;
     RECT  67.312 106.098 67.504 127.182 ;
     RECT  67.312 149.298 67.504 168.222 ;
     RECT  67.504 40.56 69.908 40.872 ;
     RECT  67.504 65.712 69.908 65.736 ;
     RECT  67.504 75.456 69.908 75.48 ;
     RECT  67.504 83.808 69.908 84.072 ;
     RECT  67.504 117.264 69.908 117.288 ;
     RECT  67.504 126.96 69.908 126.984 ;
     RECT  69.908 2.148 70.012 41.052 ;
     RECT  69.908 62.628 70.012 84.252 ;
     RECT  69.908 105.828 70.012 127.452 ;
     RECT  69.908 149.028 70.012 168.492 ;
     RECT  70.012 2.418 70.204 40.872 ;
     RECT  70.012 62.898 70.204 84.072 ;
     RECT  70.012 106.098 70.204 127.182 ;
     RECT  70.012 149.298 70.204 168.222 ;
     RECT  43.272 129.36 70.693 147.24 ;
     RECT  70.204 40.56 72.608 40.872 ;
     RECT  70.204 65.712 72.608 65.736 ;
     RECT  70.204 75.456 72.608 75.48 ;
     RECT  70.204 83.808 72.608 84.072 ;
     RECT  70.204 117.264 72.608 117.288 ;
     RECT  70.204 126.96 72.608 126.984 ;
     RECT  72.608 2.148 72.712 41.052 ;
     RECT  72.608 62.628 72.712 84.252 ;
     RECT  72.608 105.828 72.712 127.452 ;
     RECT  72.608 149.028 72.712 168.492 ;
     RECT  72.712 2.418 72.904 40.872 ;
     RECT  72.712 62.898 72.904 84.168 ;
     RECT  72.712 106.098 72.904 127.182 ;
     RECT  72.712 149.298 72.904 168.222 ;
     RECT  72.904 126.816 73.505 126.984 ;
     RECT  73.505 126.816 73.901 126.84 ;
     RECT  74.005 125.376 74.101 125.4 ;
     RECT  74.101 124.656 74.188 125.4 ;
     RECT  43.272 43.104 74.653 61.08 ;
     RECT  72.904 40.56 75.013 40.872 ;
     RECT  74.653 43.104 75.12 61.176 ;
     RECT  43.272 86.4 75.12 103.848 ;
     RECT  70.693 129.36 75.12 147.288 ;
     RECT  72.904 83.808 75.121 84.168 ;
     RECT  75.12 43.104 75.157 53.784 ;
     RECT  75.12 60.576 75.157 61.176 ;
     RECT  75.157 127.68 75.193 127.704 ;
     RECT  75.013 40.56 75.203 41.64 ;
     RECT  75.157 60.576 75.244 61.56 ;
     RECT  75.121 83.808 75.265 84.504 ;
     RECT  75.157 43.056 75.305 53.784 ;
     RECT  75.12 103.824 75.305 103.848 ;
     RECT  75.12 129.36 75.305 129.384 ;
     RECT  75.12 147.072 75.305 147.288 ;
     RECT  75.203 40.56 75.308 41.052 ;
     RECT  72.904 65.712 75.308 65.736 ;
     RECT  72.904 75.456 75.308 75.48 ;
     RECT  75.121 82.416 75.308 82.44 ;
     RECT  75.265 83.568 75.308 84.504 ;
     RECT  72.904 117.264 75.308 117.288 ;
     RECT  74.188 125.376 75.308 125.4 ;
     RECT  75.193 127.68 75.308 127.8 ;
     RECT  75.305 43.056 75.341 53.688 ;
     RECT  75.12 130.368 75.341 140.184 ;
     RECT  75.341 130.368 75.377 140.088 ;
     RECT  75.308 2.148 75.412 41.052 ;
     RECT  75.308 62.628 75.412 84.504 ;
     RECT  75.308 105.828 75.412 127.8 ;
     RECT  75.308 149.028 75.412 168.492 ;
     RECT  75.412 62.898 75.413 84.504 ;
     RECT  75.341 43.056 75.485 53.592 ;
     RECT  75.12 87.168 75.485 96.984 ;
     RECT  75.305 147.12 75.557 147.288 ;
     RECT  75.485 43.056 75.593 53.496 ;
     RECT  75.377 130.368 75.593 139.992 ;
     RECT  75.412 2.418 75.604 40.872 ;
     RECT  75.413 62.898 75.604 84.168 ;
     RECT  75.412 106.098 75.604 127.8 ;
     RECT  75.412 149.298 75.604 168.222 ;
     RECT  75.485 87.168 75.629 96.792 ;
     RECT  75.244 60.576 75.731 61.176 ;
     RECT  75.604 127.248 75.731 127.8 ;
     RECT  75.557 147.12 75.731 147.192 ;
     RECT  75.731 147.168 75.827 147.192 ;
     RECT  75.629 87.168 75.881 96.696 ;
     RECT  75.881 87.168 75.917 90.84 ;
     RECT  75.593 130.368 76.133 139.896 ;
     RECT  75.881 91.872 76.385 96.696 ;
     RECT  75.604 124.608 76.403 126.168 ;
     RECT  76.133 134.784 76.421 139.896 ;
     RECT  75.604 73.296 76.643 73.32 ;
     RECT  75.604 82.416 76.643 84.168 ;
     RECT  76.385 91.968 76.673 96.696 ;
     RECT  76.133 130.368 76.673 133.752 ;
     RECT  76.885 72.96 76.969 72.984 ;
     RECT  76.673 130.464 77.516 133.752 ;
     RECT  76.421 134.88 77.516 139.896 ;
     RECT  77.516 130.464 77.557 139.896 ;
     RECT  75.604 40.56 78.008 40.872 ;
     RECT  75.593 43.104 78.008 53.496 ;
     RECT  75.12 55.2 78.008 55.224 ;
     RECT  75.731 61.152 78.008 61.176 ;
     RECT  75.604 65.712 78.008 65.736 ;
     RECT  76.885 70.656 78.008 70.68 ;
     RECT  75.604 75.456 78.008 75.48 ;
     RECT  76.643 82.416 78.008 84.12 ;
     RECT  76.885 85.104 78.008 85.128 ;
     RECT  75.917 87.264 78.008 90.84 ;
     RECT  76.673 91.968 78.008 96.504 ;
     RECT  75.12 101.088 78.008 101.112 ;
     RECT  75.604 117.264 78.008 117.288 ;
     RECT  76.403 124.608 78.008 124.632 ;
     RECT  76.403 126.144 78.008 126.168 ;
     RECT  75.731 127.248 78.008 127.272 ;
     RECT  77.557 130.464 78.008 139.944 ;
     RECT  75.12 142.128 78.008 142.152 ;
     RECT  78.008 2.148 78.112 168.492 ;
     RECT  78.112 2.418 78.304 168.222 ;
     RECT  78.304 67.824 78.419 68.232 ;
     RECT  78.419 67.824 78.617 67.848 ;
     RECT  78.304 82.416 78.659 85.128 ;
     RECT  78.304 61.056 78.689 61.176 ;
     RECT  78.304 70.128 78.689 70.152 ;
     RECT  78.304 65.712 79.013 65.832 ;
     RECT  78.304 44.064 79.333 47.64 ;
     RECT  78.304 40.56 79.523 40.872 ;
     RECT  79.523 40.56 80.708 40.584 ;
     RECT  79.333 44.064 80.708 47.88 ;
     RECT  78.304 55.2 80.708 55.224 ;
     RECT  78.689 61.152 80.708 61.176 ;
     RECT  79.013 65.712 80.708 65.736 ;
     RECT  78.659 82.416 80.708 84.12 ;
     RECT  78.659 85.104 80.708 85.128 ;
     RECT  78.304 87.264 80.708 90.888 ;
     RECT  78.304 101.088 80.708 101.112 ;
     RECT  78.304 117.264 80.708 117.288 ;
     RECT  78.304 124.608 80.708 124.632 ;
     RECT  78.304 126.144 80.708 126.168 ;
     RECT  78.304 127.248 80.708 127.272 ;
     RECT  78.304 130.464 80.708 133.272 ;
     RECT  78.304 138.624 80.708 138.648 ;
     RECT  78.304 139.92 80.708 139.944 ;
     RECT  78.304 142.128 80.708 142.152 ;
     RECT  80.708 2.148 80.812 168.492 ;
     RECT  80.812 2.418 81.004 168.222 ;
     RECT  81.004 126.144 83.185 126.168 ;
     RECT  81.004 40.56 83.408 40.584 ;
     RECT  81.004 44.064 83.408 47.88 ;
     RECT  81.004 55.2 83.408 55.224 ;
     RECT  81.004 61.152 83.408 61.176 ;
     RECT  81.004 65.712 83.408 65.736 ;
     RECT  83.269 77.952 83.408 77.976 ;
     RECT  81.004 82.416 83.408 84.12 ;
     RECT  81.004 85.104 83.408 85.752 ;
     RECT  81.004 87.264 83.408 90.888 ;
     RECT  81.004 101.088 83.408 101.112 ;
     RECT  81.004 117.264 83.408 117.288 ;
     RECT  81.004 124.608 83.408 124.632 ;
     RECT  83.185 125.952 83.408 126.168 ;
     RECT  81.004 127.248 83.408 127.272 ;
     RECT  81.004 130.464 83.408 133.272 ;
     RECT  81.004 138.624 83.408 138.648 ;
     RECT  81.004 139.92 83.408 139.944 ;
     RECT  81.004 142.128 83.408 142.152 ;
     RECT  83.408 2.148 83.512 168.492 ;
     RECT  83.512 2.418 83.704 168.222 ;
     RECT  83.704 82.08 84.901 84.072 ;
     RECT  84.901 81.12 84.947 84.072 ;
     RECT  84.947 82.944 85.165 84.072 ;
     RECT  83.704 40.56 86.108 40.584 ;
     RECT  83.704 44.064 86.108 47.88 ;
     RECT  83.704 55.2 86.108 55.224 ;
     RECT  83.704 56.496 86.108 56.52 ;
     RECT  83.704 61.152 86.108 61.176 ;
     RECT  83.704 65.712 86.108 65.736 ;
     RECT  83.704 77.952 86.108 77.976 ;
     RECT  84.947 81.12 86.108 81.144 ;
     RECT  85.165 82.944 86.108 84.12 ;
     RECT  83.704 85.104 86.108 85.752 ;
     RECT  83.704 87.264 86.108 90.888 ;
     RECT  83.704 101.088 86.108 101.112 ;
     RECT  83.704 117.264 86.108 117.288 ;
     RECT  83.704 124.608 86.108 124.632 ;
     RECT  83.704 125.952 86.108 125.976 ;
     RECT  83.704 127.536 86.108 127.56 ;
     RECT  83.704 130.464 86.108 133.272 ;
     RECT  83.704 138.624 86.108 138.648 ;
     RECT  83.704 139.92 86.108 139.944 ;
     RECT  83.704 142.128 86.108 142.152 ;
     RECT  83.704 143.424 86.108 143.448 ;
     RECT  86.108 2.148 86.212 168.492 ;
     RECT  86.212 2.418 86.404 168.222 ;
     RECT  86.404 83.04 86.501 85.752 ;
     RECT  86.404 124.512 86.501 124.632 ;
     RECT  86.404 61.056 86.681 61.176 ;
     RECT  86.404 77.952 86.681 78.072 ;
     RECT  86.404 125.856 86.681 125.976 ;
     RECT  86.404 138.576 87.005 138.744 ;
     RECT  86.404 117.264 87.203 117.288 ;
     RECT  86.404 130.56 87.221 133.032 ;
     RECT  86.404 44.064 87.509 47.88 ;
     RECT  86.404 139.92 87.545 139.944 ;
     RECT  87.005 138.576 87.757 138.648 ;
     RECT  86.501 83.04 88.364 85.656 ;
     RECT  86.404 41.712 88.369 41.736 ;
     RECT  88.364 83.04 88.405 86.04 ;
     RECT  86.404 87.264 88.405 90.648 ;
     RECT  86.404 40.56 88.808 40.584 ;
     RECT  88.369 41.712 88.808 42.024 ;
     RECT  87.509 44.352 88.808 47.88 ;
     RECT  86.404 55.2 88.808 55.224 ;
     RECT  86.404 56.496 88.808 56.52 ;
     RECT  86.681 61.152 88.808 61.176 ;
     RECT  86.404 65.712 88.808 65.736 ;
     RECT  86.681 77.952 88.808 77.976 ;
     RECT  86.404 81.12 88.808 81.144 ;
     RECT  88.405 83.04 88.808 90.648 ;
     RECT  86.404 101.088 88.808 101.112 ;
     RECT  86.404 114.864 88.808 114.888 ;
     RECT  86.501 124.512 88.808 124.536 ;
     RECT  86.681 125.952 88.808 125.976 ;
     RECT  86.404 127.536 88.808 127.56 ;
     RECT  87.221 130.56 88.808 132.936 ;
     RECT  87.757 138.48 88.808 138.648 ;
     RECT  87.721 139.68 88.808 139.704 ;
     RECT  86.404 142.128 88.808 142.152 ;
     RECT  86.404 143.424 88.808 143.448 ;
     RECT  88.808 2.148 88.912 168.492 ;
     RECT  88.912 2.418 89.104 168.222 ;
     RECT  89.104 40.56 89.219 40.584 ;
     RECT  89.104 130.56 89.315 132.936 ;
     RECT  89.104 41.712 89.411 47.88 ;
     RECT  89.104 52.704 89.411 57.192 ;
     RECT  89.411 41.712 89.507 47.448 ;
     RECT  89.507 41.712 89.533 43.368 ;
     RECT  89.104 77.952 89.795 77.976 ;
     RECT  89.104 81.12 90.085 81.528 ;
     RECT  89.411 53.52 90.101 57.192 ;
     RECT  89.104 39.216 90.131 39.288 ;
     RECT  89.104 138.48 90.236 140.472 ;
     RECT  89.104 142.032 90.236 142.2 ;
     RECT  89.104 83.04 90.241 90.648 ;
     RECT  90.101 53.52 90.281 55.224 ;
     RECT  89.507 44.448 90.353 47.448 ;
     RECT  90.236 138.48 90.493 142.2 ;
     RECT  89.104 143.424 90.493 143.448 ;
     RECT  89.104 72.144 90.529 72.696 ;
     RECT  90.529 98.976 90.565 99 ;
     RECT  89.104 100.224 90.565 101.112 ;
     RECT  89.104 128.976 90.565 129 ;
     RECT  90.101 56.784 90.601 57.192 ;
     RECT  89.104 125.952 90.601 126.456 ;
     RECT  89.104 127.536 90.601 127.896 ;
     RECT  90.085 81.12 90.637 81.912 ;
     RECT  90.241 82.944 90.637 90.648 ;
     RECT  89.104 124.512 90.637 124.536 ;
     RECT  90.601 125.568 90.637 127.896 ;
     RECT  90.493 138.48 90.637 143.448 ;
     RECT  90.637 124.512 91.069 127.896 ;
     RECT  90.565 128.976 91.069 129.048 ;
     RECT  91.103 108.192 91.105 108.216 ;
     RECT  90.085 40.416 91.141 40.44 ;
     RECT  91.069 124.512 91.141 129.048 ;
     RECT  90.281 53.568 91.177 55.224 ;
     RECT  90.601 56.784 91.177 57.336 ;
     RECT  91.141 105.36 91.177 105.384 ;
     RECT  90.529 71.952 91.189 72.696 ;
     RECT  89.533 43.344 91.285 43.368 ;
     RECT  91.177 53.568 91.285 57.336 ;
     RECT  90.131 39.264 91.321 39.288 ;
     RECT  91.141 96.432 91.321 96.456 ;
     RECT  90.565 98.976 91.321 101.112 ;
     RECT  91.321 98.112 91.333 101.112 ;
     RECT  91.285 43.152 91.381 43.368 ;
     RECT  90.353 44.736 91.381 47.448 ;
     RECT  89.315 130.56 91.381 132.696 ;
     RECT  91.321 38.688 91.508 39.288 ;
     RECT  91.141 40.416 91.508 40.584 ;
     RECT  89.533 41.712 91.508 42.024 ;
     RECT  91.381 43.152 91.508 47.448 ;
     RECT  91.285 53.568 91.508 57.432 ;
     RECT  89.104 61.152 91.508 61.176 ;
     RECT  89.104 65.712 91.508 65.736 ;
     RECT  91.189 71.952 91.508 72.792 ;
     RECT  90.637 81.12 91.508 90.648 ;
     RECT  91.321 96.288 91.508 96.456 ;
     RECT  91.333 98.112 91.508 101.64 ;
     RECT  91.177 105.36 91.508 105.48 ;
     RECT  91.105 108.192 91.508 108.552 ;
     RECT  89.104 114.864 91.508 114.888 ;
     RECT  91.141 124.512 91.508 129.24 ;
     RECT  91.381 130.464 91.508 132.696 ;
     RECT  90.637 138.48 91.508 143.544 ;
     RECT  91.508 2.148 91.612 168.492 ;
     RECT  91.612 2.418 91.804 168.222 ;
     RECT  91.804 45.744 91.865 47.448 ;
     RECT  91.804 43.68 92.045 44.76 ;
     RECT  91.865 45.744 92.045 47.4 ;
     RECT  91.804 89.472 92.045 90.648 ;
     RECT  91.804 132.672 92.045 132.696 ;
     RECT  91.804 71.808 92.051 72.792 ;
     RECT  91.804 81.024 92.051 88.392 ;
     RECT  92.045 45.744 92.081 46.296 ;
     RECT  91.804 108.192 92.147 108.216 ;
     RECT  91.804 114.528 92.153 114.888 ;
     RECT  91.804 123.12 92.225 123.624 ;
     RECT  92.051 81.024 92.291 88.2 ;
     RECT  92.045 47.376 92.333 47.4 ;
     RECT  92.045 43.68 92.341 44.472 ;
     RECT  92.291 81.024 92.369 86.376 ;
     RECT  92.153 114.864 92.369 114.888 ;
     RECT  91.804 129.984 92.369 131.16 ;
     RECT  92.225 123.6 92.435 123.624 ;
     RECT  91.804 96.288 92.621 101.64 ;
     RECT  92.051 72.144 92.627 72.792 ;
     RECT  92.081 46.272 92.729 46.296 ;
     RECT  91.804 105.312 92.771 105.48 ;
     RECT  91.804 38.688 92.821 42.216 ;
     RECT  92.341 43.68 92.821 44.184 ;
     RECT  92.369 129.984 92.867 130.824 ;
     RECT  91.804 53.76 92.869 57.432 ;
     RECT  92.369 81.024 92.869 86.328 ;
     RECT  92.867 130.8 92.873 130.824 ;
     RECT  92.869 53.376 92.897 57.432 ;
     RECT  91.804 50.16 92.905 50.184 ;
     RECT  92.897 52.992 92.924 57.432 ;
     RECT  92.924 52.368 93.011 57.432 ;
     RECT  92.905 50.16 93.053 50.712 ;
     RECT  92.291 87.936 93.053 88.2 ;
     RECT  93.053 50.688 93.155 50.712 ;
     RECT  93.053 88.176 93.233 88.2 ;
     RECT  91.804 124.656 93.445 129 ;
     RECT  92.621 96.288 93.589 101.112 ;
     RECT  93.445 124.656 93.661 129.528 ;
     RECT  92.869 80.784 93.685 86.328 ;
     RECT  92.965 47.808 93.841 47.88 ;
     RECT  92.821 38.688 93.973 44.184 ;
     RECT  93.692 78.048 94.021 78.072 ;
     RECT  93.589 96.192 94.021 101.112 ;
     RECT  93.661 124.608 94.021 129.528 ;
     RECT  91.804 138.624 94.021 143.784 ;
     RECT  94.021 138.624 94.069 144.264 ;
     RECT  93.973 38.4 94.208 44.184 ;
     RECT  93.841 47.808 94.208 48.312 ;
     RECT  93.011 52.464 94.208 57.432 ;
     RECT  91.804 61.152 94.208 61.176 ;
     RECT  91.804 65.712 94.208 65.736 ;
     RECT  92.627 72.144 94.208 72.168 ;
     RECT  94.021 78.048 94.208 78.12 ;
     RECT  93.685 80.784 94.208 86.856 ;
     RECT  92.045 89.472 94.208 90.216 ;
     RECT  94.021 95.904 94.208 101.112 ;
     RECT  93.733 123.36 94.208 123.384 ;
     RECT  94.021 124.512 94.208 129.528 ;
     RECT  94.069 138.624 94.208 144.552 ;
     RECT  94.208 2.148 94.312 168.492 ;
     RECT  94.312 2.418 94.504 168.222 ;
     RECT  94.504 95.616 94.709 101.112 ;
     RECT  94.504 37.536 95.141 44.184 ;
     RECT  95.141 37.536 95.825 44.088 ;
     RECT  94.504 124.224 95.825 129.528 ;
     RECT  94.504 138.288 95.825 144.552 ;
     RECT  95.825 37.536 95.933 44.04 ;
     RECT  94.504 51.648 95.933 57.864 ;
     RECT  94.504 80.256 95.933 87 ;
     RECT  94.709 95.616 95.933 100.968 ;
     RECT  95.825 124.224 95.933 129.432 ;
     RECT  95.825 138.288 95.933 144.264 ;
     RECT  95.933 38.544 95.939 44.04 ;
     RECT  95.933 80.64 95.939 86.76 ;
     RECT  95.933 138.624 96.005 144.264 ;
     RECT  95.933 52.56 96.227 57.72 ;
     RECT  95.933 125.136 96.227 129.432 ;
     RECT  95.939 38.736 96.275 44.04 ;
     RECT  96.227 52.56 96.275 57.624 ;
     RECT  95.939 81.36 96.275 86.76 ;
     RECT  96.005 138.96 96.275 144.264 ;
     RECT  96.275 38.736 96.323 43.944 ;
     RECT  96.275 81.36 96.323 86.664 ;
     RECT  95.933 96.624 96.323 100.92 ;
     RECT  96.227 129.408 96.323 129.432 ;
     RECT  96.275 138.96 96.323 143.688 ;
     RECT  96.275 52.56 96.437 57.528 ;
     RECT  96.323 96.624 97.405 100.824 ;
     RECT  97.405 96.48 97.441 100.824 ;
     RECT  96.323 38.736 98.196 38.76 ;
     RECT  96.323 38.76 98.22 38.88 ;
     RECT  96.323 38.88 98.196 38.904 ;
     RECT  96.323 38.904 98.22 39.024 ;
     RECT  96.323 39.024 98.196 39.048 ;
     RECT  96.323 39.048 98.22 39.168 ;
     RECT  96.323 39.168 98.196 39.192 ;
     RECT  96.323 39.192 98.22 39.312 ;
     RECT  96.323 39.312 98.196 39.336 ;
     RECT  96.323 39.336 98.22 39.456 ;
     RECT  96.323 39.456 98.196 39.48 ;
     RECT  96.323 39.48 98.22 39.6 ;
     RECT  96.323 39.6 98.196 39.624 ;
     RECT  96.323 39.624 98.22 39.744 ;
     RECT  96.323 39.744 98.196 39.768 ;
     RECT  96.323 39.768 98.22 39.888 ;
     RECT  96.323 39.888 98.196 39.912 ;
     RECT  96.323 39.912 98.22 40.032 ;
     RECT  96.323 40.032 98.196 40.056 ;
     RECT  96.323 40.056 98.22 40.176 ;
     RECT  96.323 40.176 98.196 40.2 ;
     RECT  96.323 40.2 98.22 40.32 ;
     RECT  96.323 40.32 98.196 40.344 ;
     RECT  96.323 40.344 98.22 40.464 ;
     RECT  96.323 40.464 98.196 40.488 ;
     RECT  96.323 40.488 98.22 40.608 ;
     RECT  96.323 40.608 98.196 40.632 ;
     RECT  96.323 40.632 98.22 40.752 ;
     RECT  96.323 40.752 98.196 40.776 ;
     RECT  96.323 40.776 98.22 40.896 ;
     RECT  96.323 40.896 98.196 40.92 ;
     RECT  96.323 40.92 98.22 41.04 ;
     RECT  96.323 41.04 98.196 41.064 ;
     RECT  96.323 41.064 98.22 41.184 ;
     RECT  96.323 41.184 98.196 41.208 ;
     RECT  96.323 41.208 98.22 41.328 ;
     RECT  96.323 41.328 98.196 41.352 ;
     RECT  96.323 41.352 98.22 41.472 ;
     RECT  96.323 41.472 98.196 41.496 ;
     RECT  96.323 41.496 98.22 41.616 ;
     RECT  96.323 41.616 98.196 41.64 ;
     RECT  96.323 41.64 98.22 41.76 ;
     RECT  96.323 41.76 98.196 41.784 ;
     RECT  96.323 41.784 98.22 41.904 ;
     RECT  96.323 41.904 98.196 41.928 ;
     RECT  96.323 41.928 98.22 42.048 ;
     RECT  96.323 42.048 98.196 42.072 ;
     RECT  96.323 42.072 98.22 42.192 ;
     RECT  96.323 42.192 98.196 42.216 ;
     RECT  96.323 42.216 98.22 42.336 ;
     RECT  96.323 42.336 98.196 42.36 ;
     RECT  96.323 42.36 98.22 42.48 ;
     RECT  96.323 42.48 98.196 42.504 ;
     RECT  96.323 42.504 98.22 42.624 ;
     RECT  96.323 42.624 98.196 42.648 ;
     RECT  96.323 42.648 98.22 42.768 ;
     RECT  96.323 42.768 98.196 42.792 ;
     RECT  96.323 42.792 98.22 42.912 ;
     RECT  96.323 42.912 98.196 42.936 ;
     RECT  96.323 42.936 98.22 43.056 ;
     RECT  96.323 43.056 98.196 43.08 ;
     RECT  96.323 43.08 98.22 43.2 ;
     RECT  96.323 43.2 98.196 43.224 ;
     RECT  96.437 52.56 98.196 52.584 ;
     RECT  96.437 52.584 98.22 52.704 ;
     RECT  96.437 52.704 98.196 52.728 ;
     RECT  96.437 52.728 98.22 52.848 ;
     RECT  96.437 52.848 98.196 52.872 ;
     RECT  96.437 52.872 98.22 52.992 ;
     RECT  96.437 52.992 98.196 53.016 ;
     RECT  96.437 53.016 98.22 53.136 ;
     RECT  96.437 53.136 98.196 53.16 ;
     RECT  96.437 53.16 98.22 53.28 ;
     RECT  96.437 53.28 98.196 53.304 ;
     RECT  96.437 53.304 98.22 53.424 ;
     RECT  96.437 53.424 98.196 53.448 ;
     RECT  96.437 53.448 98.22 53.568 ;
     RECT  96.437 53.568 98.196 53.592 ;
     RECT  96.437 53.592 98.22 53.712 ;
     RECT  96.437 53.712 98.196 53.736 ;
     RECT  96.437 53.736 98.22 53.856 ;
     RECT  96.437 53.856 98.196 53.88 ;
     RECT  96.437 53.88 98.22 54 ;
     RECT  96.437 54 98.196 54.024 ;
     RECT  96.437 54.024 98.22 54.144 ;
     RECT  96.437 54.144 98.196 54.168 ;
     RECT  96.437 54.168 98.22 54.288 ;
     RECT  96.437 54.288 98.196 54.312 ;
     RECT  96.437 54.312 98.22 54.432 ;
     RECT  96.437 54.432 98.196 54.456 ;
     RECT  96.437 54.456 98.22 54.576 ;
     RECT  96.437 54.576 98.196 54.6 ;
     RECT  96.437 54.6 98.22 54.72 ;
     RECT  96.437 54.72 98.196 54.744 ;
     RECT  96.437 54.744 98.22 54.864 ;
     RECT  96.437 54.864 98.196 54.888 ;
     RECT  96.437 54.888 98.22 55.008 ;
     RECT  96.437 55.008 98.196 55.032 ;
     RECT  96.437 55.032 98.22 55.152 ;
     RECT  96.437 55.152 98.196 55.176 ;
     RECT  96.437 55.176 98.22 55.296 ;
     RECT  96.437 55.296 98.196 55.32 ;
     RECT  96.437 55.32 98.22 55.44 ;
     RECT  96.437 55.44 98.196 55.464 ;
     RECT  96.437 55.464 98.22 55.584 ;
     RECT  96.437 55.584 98.196 55.608 ;
     RECT  96.437 55.608 98.22 55.728 ;
     RECT  96.437 55.728 98.196 55.752 ;
     RECT  96.437 55.752 98.22 55.872 ;
     RECT  96.437 55.872 98.196 55.896 ;
     RECT  96.437 55.896 98.22 56.016 ;
     RECT  96.437 56.016 98.196 56.04 ;
     RECT  96.437 56.04 98.22 56.16 ;
     RECT  96.437 56.16 98.196 56.184 ;
     RECT  96.437 56.184 98.22 56.304 ;
     RECT  96.437 56.304 98.196 56.328 ;
     RECT  96.437 56.328 98.22 56.448 ;
     RECT  96.437 56.448 98.196 56.472 ;
     RECT  96.437 56.472 98.22 56.592 ;
     RECT  96.437 56.592 98.196 56.616 ;
     RECT  96.437 56.616 98.22 56.736 ;
     RECT  96.437 56.736 98.196 56.76 ;
     RECT  96.437 56.76 98.22 56.88 ;
     RECT  96.437 56.88 98.196 56.904 ;
     RECT  96.437 56.904 98.22 57.024 ;
     RECT  96.437 57.024 98.196 57.048 ;
     RECT  96.323 81.36 98.196 81.384 ;
     RECT  96.323 81.384 98.22 81.504 ;
     RECT  96.323 81.504 98.196 81.528 ;
     RECT  96.323 81.528 98.22 81.648 ;
     RECT  96.323 81.648 98.196 81.672 ;
     RECT  96.323 81.672 98.22 81.792 ;
     RECT  96.323 81.792 98.196 81.816 ;
     RECT  96.323 81.816 98.22 81.936 ;
     RECT  96.323 81.936 98.196 81.96 ;
     RECT  96.323 81.96 98.22 82.08 ;
     RECT  96.323 82.08 98.196 82.104 ;
     RECT  96.323 82.104 98.22 82.224 ;
     RECT  96.323 82.224 98.196 82.248 ;
     RECT  96.323 82.248 98.22 82.368 ;
     RECT  96.323 82.368 98.196 82.392 ;
     RECT  96.323 82.392 98.22 82.512 ;
     RECT  96.323 82.512 98.196 82.536 ;
     RECT  96.323 82.536 98.22 82.656 ;
     RECT  96.323 82.656 98.196 82.68 ;
     RECT  96.323 82.68 98.22 82.8 ;
     RECT  96.323 82.8 98.196 82.824 ;
     RECT  96.323 82.824 98.22 82.944 ;
     RECT  96.323 82.944 98.196 82.968 ;
     RECT  96.323 82.968 98.22 83.088 ;
     RECT  96.323 83.088 98.196 83.112 ;
     RECT  96.323 83.112 98.22 83.232 ;
     RECT  96.323 83.232 98.196 83.256 ;
     RECT  96.323 83.256 98.22 83.376 ;
     RECT  96.323 83.376 98.196 83.4 ;
     RECT  96.323 83.4 98.22 83.52 ;
     RECT  96.323 83.52 98.196 83.544 ;
     RECT  96.323 83.544 98.22 83.664 ;
     RECT  96.323 83.664 98.196 83.688 ;
     RECT  96.323 83.688 98.22 83.808 ;
     RECT  96.323 83.808 98.196 83.832 ;
     RECT  96.323 83.832 98.22 83.952 ;
     RECT  96.323 83.952 98.196 83.976 ;
     RECT  96.323 83.976 98.22 84.096 ;
     RECT  96.323 84.096 98.196 84.12 ;
     RECT  96.323 84.12 98.22 84.24 ;
     RECT  96.323 84.24 98.196 84.264 ;
     RECT  96.323 84.264 98.22 84.384 ;
     RECT  96.323 84.384 98.196 84.408 ;
     RECT  96.323 84.408 98.22 84.528 ;
     RECT  96.323 84.528 98.196 84.552 ;
     RECT  96.323 84.552 98.22 84.672 ;
     RECT  96.323 84.672 98.196 84.696 ;
     RECT  96.323 84.696 98.22 84.816 ;
     RECT  96.323 84.816 98.196 84.84 ;
     RECT  96.323 84.84 98.22 84.96 ;
     RECT  96.323 84.96 98.196 84.984 ;
     RECT  96.323 84.984 98.22 85.104 ;
     RECT  96.323 85.104 98.196 85.128 ;
     RECT  96.323 85.128 98.22 85.248 ;
     RECT  96.323 85.248 98.196 85.272 ;
     RECT  96.323 85.272 98.22 85.392 ;
     RECT  96.323 85.392 98.196 85.416 ;
     RECT  96.323 85.416 98.22 85.536 ;
     RECT  96.323 85.536 98.196 85.56 ;
     RECT  96.323 85.56 98.22 85.68 ;
     RECT  96.323 85.68 98.196 85.704 ;
     RECT  96.323 85.704 98.22 85.824 ;
     RECT  96.323 85.824 98.196 85.848 ;
     RECT  97.441 96.336 98.196 96.36 ;
     RECT  97.441 96.36 98.22 96.48 ;
     RECT  97.441 96.48 98.196 96.504 ;
     RECT  97.441 96.504 98.22 96.624 ;
     RECT  97.441 96.624 98.196 96.648 ;
     RECT  97.441 96.648 98.22 96.768 ;
     RECT  97.441 96.768 98.196 96.792 ;
     RECT  97.441 96.792 98.22 96.912 ;
     RECT  97.441 96.912 98.196 96.936 ;
     RECT  97.441 96.936 98.22 97.056 ;
     RECT  97.441 97.056 98.196 97.08 ;
     RECT  97.441 97.08 98.22 97.2 ;
     RECT  97.441 97.2 98.196 97.224 ;
     RECT  97.441 97.224 98.22 97.344 ;
     RECT  97.441 97.344 98.196 97.368 ;
     RECT  97.441 97.368 98.22 97.488 ;
     RECT  97.441 97.488 98.196 97.512 ;
     RECT  97.441 97.512 98.22 97.632 ;
     RECT  97.441 97.632 98.196 97.656 ;
     RECT  97.441 97.656 98.22 97.776 ;
     RECT  97.441 97.776 98.196 97.8 ;
     RECT  97.441 97.8 98.22 97.92 ;
     RECT  97.441 97.92 98.196 97.944 ;
     RECT  97.441 97.944 98.22 98.064 ;
     RECT  97.441 98.064 98.196 98.088 ;
     RECT  97.441 98.088 98.22 98.208 ;
     RECT  97.441 98.208 98.196 98.232 ;
     RECT  97.441 98.232 98.22 98.352 ;
     RECT  97.441 98.352 98.196 98.376 ;
     RECT  97.441 98.376 98.22 98.496 ;
     RECT  97.441 98.496 98.196 98.52 ;
     RECT  97.441 98.52 98.22 98.64 ;
     RECT  97.441 98.64 98.196 98.664 ;
     RECT  97.441 98.664 98.22 98.784 ;
     RECT  97.441 98.784 98.196 98.808 ;
     RECT  97.441 98.808 98.22 98.928 ;
     RECT  97.441 98.928 98.196 98.952 ;
     RECT  97.441 98.952 98.22 99.072 ;
     RECT  97.441 99.072 98.196 99.096 ;
     RECT  97.441 99.096 98.22 99.216 ;
     RECT  97.441 99.216 98.196 99.24 ;
     RECT  97.441 99.24 98.22 99.36 ;
     RECT  97.441 99.36 98.196 99.384 ;
     RECT  97.441 99.384 98.22 99.504 ;
     RECT  97.441 99.504 98.196 99.528 ;
     RECT  97.441 99.528 98.22 99.648 ;
     RECT  97.441 99.648 98.196 99.672 ;
     RECT  97.441 99.672 98.22 99.792 ;
     RECT  97.441 99.792 98.196 99.816 ;
     RECT  97.441 99.816 98.22 99.936 ;
     RECT  97.441 99.936 98.196 99.96 ;
     RECT  97.441 99.96 98.22 100.08 ;
     RECT  97.441 100.08 98.196 100.104 ;
     RECT  97.441 100.104 98.22 100.224 ;
     RECT  97.441 100.224 98.196 100.248 ;
     RECT  97.441 100.248 98.22 100.368 ;
     RECT  97.441 100.368 98.196 100.392 ;
     RECT  97.441 100.392 98.22 100.512 ;
     RECT  97.441 100.512 98.196 100.536 ;
     RECT  97.441 100.536 98.22 100.656 ;
     RECT  97.441 100.656 98.196 100.68 ;
     RECT  97.441 100.68 98.22 100.8 ;
     RECT  97.441 100.8 98.196 100.824 ;
     RECT  96.227 125.136 98.196 125.16 ;
     RECT  96.227 125.16 98.22 125.28 ;
     RECT  96.227 125.28 98.196 125.304 ;
     RECT  96.227 125.304 98.22 125.424 ;
     RECT  96.227 125.424 98.196 125.448 ;
     RECT  96.227 125.448 98.22 125.568 ;
     RECT  96.227 125.568 98.196 125.592 ;
     RECT  96.227 125.592 98.22 125.712 ;
     RECT  96.227 125.712 98.196 125.736 ;
     RECT  96.227 125.736 98.22 125.856 ;
     RECT  96.227 125.856 98.196 125.88 ;
     RECT  96.227 125.88 98.22 126 ;
     RECT  96.227 126 98.196 126.024 ;
     RECT  96.227 126.024 98.22 126.144 ;
     RECT  96.227 126.144 98.196 126.168 ;
     RECT  96.227 126.168 98.22 126.288 ;
     RECT  96.227 126.288 98.196 126.312 ;
     RECT  96.227 126.312 98.22 126.432 ;
     RECT  96.227 126.432 98.196 126.456 ;
     RECT  96.227 126.456 98.22 126.576 ;
     RECT  96.227 126.576 98.196 126.6 ;
     RECT  96.227 126.6 98.22 126.72 ;
     RECT  96.227 126.72 98.196 126.744 ;
     RECT  96.227 126.744 98.22 126.864 ;
     RECT  96.227 126.864 98.196 126.888 ;
     RECT  96.227 126.888 98.22 127.008 ;
     RECT  96.227 127.008 98.196 127.032 ;
     RECT  96.227 127.032 98.22 127.152 ;
     RECT  96.227 127.152 98.196 127.176 ;
     RECT  96.227 127.176 98.22 127.296 ;
     RECT  96.227 127.296 98.196 127.32 ;
     RECT  96.227 127.32 98.22 127.44 ;
     RECT  96.227 127.44 98.196 127.464 ;
     RECT  96.227 127.464 98.22 127.584 ;
     RECT  96.227 127.584 98.196 127.608 ;
     RECT  96.227 127.608 98.22 127.728 ;
     RECT  96.227 127.728 98.196 127.752 ;
     RECT  96.227 127.752 98.22 127.872 ;
     RECT  96.227 127.872 98.196 127.896 ;
     RECT  96.227 127.896 98.22 128.016 ;
     RECT  96.227 128.016 98.196 128.04 ;
     RECT  96.227 128.04 98.22 128.16 ;
     RECT  96.227 128.16 98.196 128.184 ;
     RECT  96.227 128.184 98.22 128.304 ;
     RECT  96.227 128.304 98.196 128.328 ;
     RECT  96.323 138.96 98.196 138.984 ;
     RECT  96.323 138.984 98.22 139.104 ;
     RECT  96.323 139.104 98.196 139.128 ;
     RECT  96.323 139.128 98.22 139.248 ;
     RECT  96.323 139.248 98.196 139.272 ;
     RECT  96.323 139.272 98.22 139.392 ;
     RECT  96.323 139.392 98.196 139.416 ;
     RECT  96.323 139.416 98.22 139.536 ;
     RECT  96.323 139.536 98.196 139.56 ;
     RECT  96.323 139.56 98.22 139.68 ;
     RECT  96.323 139.68 98.196 139.704 ;
     RECT  96.323 139.704 98.22 139.824 ;
     RECT  96.323 139.824 98.196 139.848 ;
     RECT  96.323 139.848 98.22 139.968 ;
     RECT  96.323 139.968 98.196 139.992 ;
     RECT  96.323 139.992 98.22 140.112 ;
     RECT  96.323 140.112 98.196 140.136 ;
     RECT  96.323 140.136 98.22 140.256 ;
     RECT  96.323 140.256 98.196 140.28 ;
     RECT  96.323 140.28 98.22 140.4 ;
     RECT  96.323 140.4 98.196 140.424 ;
     RECT  96.323 140.424 98.22 140.544 ;
     RECT  96.323 140.544 98.196 140.568 ;
     RECT  96.323 140.568 98.22 140.688 ;
     RECT  96.323 140.688 98.196 140.712 ;
     RECT  96.323 140.712 98.22 140.832 ;
     RECT  96.323 140.832 98.196 140.856 ;
     RECT  96.323 140.856 98.22 140.976 ;
     RECT  96.323 140.976 98.196 141 ;
     RECT  96.323 141 98.22 141.12 ;
     RECT  96.323 141.12 98.196 141.144 ;
     RECT  96.323 141.144 98.22 141.264 ;
     RECT  96.323 141.264 98.196 141.288 ;
     RECT  96.323 141.288 98.22 141.408 ;
     RECT  96.323 141.408 98.196 141.432 ;
     RECT  96.323 141.432 98.22 141.552 ;
     RECT  96.323 141.552 98.196 141.576 ;
     RECT  96.323 141.576 98.22 141.696 ;
     RECT  96.323 141.696 98.196 141.72 ;
     RECT  96.323 141.72 98.22 141.84 ;
     RECT  96.323 141.84 98.196 141.864 ;
     RECT  96.323 141.864 98.22 141.984 ;
     RECT  96.323 141.984 98.196 142.008 ;
     RECT  96.323 142.008 98.22 142.128 ;
     RECT  96.323 142.128 98.196 142.152 ;
     RECT  96.323 142.152 98.22 142.272 ;
     RECT  96.323 142.272 98.196 142.296 ;
     RECT  96.323 142.296 98.22 142.416 ;
     RECT  96.323 142.416 98.196 142.44 ;
     RECT  96.323 142.44 98.22 142.56 ;
     RECT  96.323 142.56 98.196 142.584 ;
     RECT  96.323 142.584 98.22 142.704 ;
     RECT  96.323 142.704 98.196 142.728 ;
     RECT  96.323 142.728 98.22 142.848 ;
     RECT  96.323 142.848 98.196 142.872 ;
     RECT  96.323 142.872 98.22 142.992 ;
     RECT  96.323 142.992 98.196 143.016 ;
     RECT  96.323 143.016 98.22 143.136 ;
     RECT  96.323 143.136 98.196 143.16 ;
     RECT  96.323 143.16 98.22 143.28 ;
     RECT  96.323 143.28 98.196 143.304 ;
     RECT  96.323 143.304 98.22 143.424 ;
     RECT  96.323 143.424 98.196 143.448 ;
     RECT  98.22 99.696 98.273 99.72 ;
     RECT  98.22 140.736 98.273 140.76 ;
    LAYER M5 ;
     RECT  2.4 2.137 2.52 2.151 ;
     RECT  5.1 2.137 5.22 2.151 ;
     RECT  7.8 2.137 7.92 2.151 ;
     RECT  10.5 2.137 10.62 2.151 ;
     RECT  13.2 2.137 13.32 2.151 ;
     RECT  15.9 2.137 16.02 2.151 ;
     RECT  18.6 2.137 18.72 2.151 ;
     RECT  21.3 2.137 21.42 2.151 ;
     RECT  24 2.137 24.12 2.151 ;
     RECT  26.7 2.137 26.82 2.151 ;
     RECT  29.4 2.137 29.52 2.151 ;
     RECT  32.1 2.137 32.22 2.151 ;
     RECT  34.8 2.137 34.92 2.151 ;
     RECT  37.5 2.137 37.62 2.151 ;
     RECT  40.2 2.137 40.32 2.151 ;
     RECT  42.9 2.137 43.02 2.151 ;
     RECT  45.6 2.137 45.72 2.151 ;
     RECT  48.3 2.137 48.42 2.151 ;
     RECT  51 2.137 51.12 2.151 ;
     RECT  53.7 2.137 53.82 2.151 ;
     RECT  56.4 2.137 56.52 2.151 ;
     RECT  59.1 2.137 59.22 2.151 ;
     RECT  61.8 2.137 61.92 2.151 ;
     RECT  64.5 2.137 64.62 2.151 ;
     RECT  67.2 2.137 67.32 2.151 ;
     RECT  69.9 2.137 70.02 2.151 ;
     RECT  72.6 2.137 72.72 2.151 ;
     RECT  75.3 2.137 75.42 2.151 ;
     RECT  78 2.137 78.12 2.151 ;
     RECT  80.7 2.137 80.82 2.151 ;
     RECT  83.4 2.137 83.52 2.151 ;
     RECT  86.1 2.137 86.22 2.151 ;
     RECT  88.8 2.137 88.92 2.151 ;
     RECT  91.5 2.137 91.62 2.151 ;
     RECT  94.2 2.137 94.32 2.151 ;
     RECT  5.1 2.151 5.412 31.861 ;
     RECT  4.272 31.861 5.412 33.539 ;
     RECT  7.8 2.151 8.112 33.925 ;
     RECT  2.4 2.151 2.712 34.165 ;
     RECT  7.8 33.925 8.232 34.835 ;
     RECT  2.4 34.165 3.432 34.979 ;
     RECT  7.8 34.835 8.112 35.845 ;
     RECT  2.4 34.979 2.712 36.085 ;
     RECT  2.304 36.085 2.712 36.275 ;
     RECT  5.1 33.539 5.412 36.997 ;
     RECT  7.8 35.845 8.232 36.997 ;
     RECT  94.2 2.151 94.512 37.525 ;
     RECT  94.2 37.525 95.16 37.573 ;
     RECT  94.2 37.573 95.784 38.005 ;
     RECT  94.2 38.005 95.832 38.149 ;
     RECT  94.2 38.149 95.88 38.389 ;
     RECT  93.984 38.389 95.88 38.533 ;
     RECT  92.88 38.725 92.904 39.059 ;
     RECT  93.984 38.533 95.928 39.443 ;
     RECT  94.032 39.443 95.928 39.491 ;
     RECT  94.032 39.491 95.688 39.779 ;
     RECT  94.08 39.779 95.688 39.923 ;
     RECT  5.1 36.997 8.232 40.067 ;
     RECT  6.96 40.067 8.232 40.117 ;
     RECT  94.2 39.923 95.688 40.211 ;
     RECT  95.664 40.211 95.688 40.355 ;
     RECT  40.2 2.151 40.512 40.357 ;
     RECT  90.096 39.205 90.12 40.451 ;
     RECT  42.9 2.151 43.212 40.549 ;
     RECT  88.8 2.151 89.112 40.549 ;
     RECT  3.936 35.605 3.96 40.691 ;
     RECT  64.5 2.151 64.812 40.981 ;
     RECT  94.2 40.211 94.512 40.981 ;
     RECT  93.024 39.637 93.048 41.027 ;
     RECT  6.96 40.117 8.376 41.075 ;
     RECT  75.3 2.151 75.612 41.605 ;
     RECT  95.712 40.885 95.736 41.749 ;
     RECT  6.96 41.075 8.112 41.843 ;
     RECT  95.712 41.749 96.312 42.037 ;
     RECT  94.08 40.981 94.512 42.133 ;
     RECT  94.08 42.133 94.632 42.613 ;
     RECT  7.8 41.843 8.112 42.709 ;
     RECT  88.8 40.549 89.208 42.709 ;
     RECT  93.504 42.613 94.632 42.709 ;
     RECT  95.616 42.037 96.312 42.899 ;
     RECT  75.168 41.605 75.612 43.091 ;
     RECT  39.984 40.357 40.512 43.093 ;
     RECT  91.5 2.151 91.812 43.141 ;
     RECT  92.832 42.709 94.632 43.141 ;
     RECT  3.984 42.133 4.008 43.187 ;
     RECT  5.1 40.067 5.412 43.285 ;
     RECT  7.8 42.709 8.232 43.379 ;
     RECT  5.1 43.285 6.312 43.861 ;
     RECT  88.8 42.709 89.496 43.907 ;
     RECT  92.832 43.141 95.16 43.955 ;
     RECT  96.24 42.899 96.312 43.955 ;
     RECT  96.24 43.955 96.264 44.051 ;
     RECT  39.984 43.093 40.776 44.437 ;
     RECT  91.296 43.141 91.812 44.437 ;
     RECT  5.1 43.861 6.408 45.059 ;
     RECT  91.296 44.437 92.328 46.259 ;
     RECT  79.488 40.837 79.512 46.501 ;
     RECT  78 2.151 78.312 46.837 ;
     RECT  79.488 46.501 79.56 46.837 ;
     RECT  78 46.837 79.56 46.979 ;
     RECT  79.488 46.979 79.56 47.363 ;
     RECT  79.536 47.363 79.56 47.555 ;
     RECT  39.984 44.437 40.92 47.749 ;
     RECT  88.8 43.907 89.256 47.845 ;
     RECT  91.5 46.259 92.328 47.845 ;
     RECT  93.6 43.955 94.512 47.845 ;
     RECT  91.5 47.845 94.512 47.891 ;
     RECT  39.936 47.749 40.92 49.619 ;
     RECT  6.384 45.059 6.408 49.907 ;
     RECT  40.2 49.619 40.92 50.195 ;
     RECT  91.5 47.891 93 50.195 ;
     RECT  42.432 40.549 43.212 50.579 ;
     RECT  92.976 50.195 93 50.677 ;
     RECT  94.032 47.891 94.512 50.677 ;
     RECT  40.2 50.195 40.776 50.771 ;
     RECT  37.5 2.151 37.812 51.205 ;
     RECT  95.76 51.781 95.784 52.021 ;
     RECT  95.76 52.021 95.832 52.309 ;
     RECT  92.976 50.677 94.512 52.981 ;
     RECT  95.52 52.309 95.832 53.027 ;
     RECT  37.5 51.205 38.472 53.123 ;
     RECT  92.928 52.981 94.512 53.365 ;
     RECT  88.8 47.845 89.4 53.555 ;
     RECT  92.88 53.365 94.512 53.557 ;
     RECT  95.52 53.027 95.784 53.557 ;
     RECT  92.88 53.557 95.784 53.891 ;
     RECT  92.88 53.891 95.736 54.275 ;
     RECT  88.8 53.555 89.208 54.899 ;
     RECT  75.3 43.091 75.612 55.189 ;
     RECT  40.2 50.771 40.512 55.237 ;
     RECT  92.928 54.275 95.736 55.573 ;
     RECT  92.928 55.573 96.312 56.483 ;
     RECT  92.928 56.483 95.16 56.531 ;
     RECT  88.8 54.899 89.112 56.677 ;
     RECT  91.5 50.195 91.812 56.677 ;
     RECT  93.744 56.531 95.16 56.819 ;
     RECT  96.192 56.483 96.312 57.059 ;
     RECT  91.296 56.677 91.812 57.205 ;
     RECT  91.296 57.205 92.04 57.443 ;
     RECT  94.032 56.819 95.16 57.635 ;
     RECT  96.192 57.059 96.264 57.635 ;
     RECT  96.192 57.635 96.216 57.731 ;
     RECT  40.2 55.237 40.92 60.611 ;
     RECT  75.3 55.189 75.72 60.611 ;
     RECT  75.3 60.611 75.612 60.613 ;
     RECT  75.168 60.613 75.612 61.571 ;
     RECT  42.672 50.579 43.212 64.693 ;
     RECT  42.576 64.693 43.212 64.837 ;
     RECT  64.5 40.981 65.112 65.701 ;
     RECT  78 46.979 78.312 65.797 ;
     RECT  78 65.797 78.6 67.859 ;
     RECT  78 67.859 78.408 70.163 ;
     RECT  94.032 57.635 94.512 72.133 ;
     RECT  91.5 57.443 92.04 72.661 ;
     RECT  91.2 72.661 92.04 72.757 ;
     RECT  91.2 72.757 92.616 72.803 ;
     RECT  76.896 70.645 76.92 72.995 ;
     RECT  21.3 2.151 21.612 74.341 ;
     RECT  12.144 40.165 12.168 74.581 ;
     RECT  13.2 2.151 13.512 74.581 ;
     RECT  0.144 74.389 0.168 74.627 ;
     RECT  12.144 74.581 13.512 74.627 ;
     RECT  64.5 65.701 65.784 75.445 ;
     RECT  67.2 2.151 67.512 75.445 ;
     RECT  12.24 74.627 13.512 76.211 ;
     RECT  3.984 75.925 4.008 77.269 ;
     RECT  5.1 45.059 5.412 77.269 ;
     RECT  3.984 77.269 5.412 77.555 ;
     RECT  83.4 2.151 83.712 77.941 ;
     RECT  4.512 77.555 5.412 78.131 ;
     RECT  64.5 75.445 67.512 78.131 ;
     RECT  93.744 72.133 94.512 80.245 ;
     RECT  93.744 80.245 95.16 80.341 ;
     RECT  93.744 80.341 95.832 80.629 ;
     RECT  91.5 72.803 92.616 80.773 ;
     RECT  93.744 80.629 95.928 80.773 ;
     RECT  88.8 56.677 89.784 81.493 ;
     RECT  88.8 81.493 90.12 81.539 ;
     RECT  91.5 80.773 95.928 81.683 ;
     RECT  84.912 81.109 84.936 82.115 ;
     RECT  6.624 76.165 6.648 82.645 ;
     RECT  42.576 64.837 43.32 82.645 ;
     RECT  91.5 81.683 95.784 82.645 ;
     RECT  6.528 82.645 6.648 82.691 ;
     RECT  91.5 82.645 96.312 82.691 ;
     RECT  91.5 82.691 94.512 83.173 ;
     RECT  90.096 81.539 90.12 83.267 ;
     RECT  95.712 82.691 96.312 83.315 ;
     RECT  78 70.163 78.312 83.509 ;
     RECT  42.48 82.645 43.32 83.557 ;
     RECT  64.5 78.131 65.112 83.653 ;
     RECT  76.608 73.285 76.632 83.749 ;
     RECT  91.344 83.173 94.512 83.749 ;
     RECT  66.528 78.131 67.512 83.795 ;
     RECT  83.28 77.941 83.712 83.843 ;
     RECT  72.6 2.151 72.912 83.941 ;
     RECT  53.7 2.151 54.012 84.037 ;
     RECT  66.72 83.795 67.512 84.083 ;
     RECT  72.6 83.941 73.032 84.083 ;
     RECT  39.024 83.749 39.048 84.085 ;
     RECT  40.2 60.611 40.512 84.085 ;
     RECT  90.432 83.749 94.512 84.131 ;
     RECT  53.7 84.037 54.744 84.179 ;
     RECT  76.608 83.749 76.92 84.179 ;
     RECT  90.672 84.131 94.512 84.325 ;
     RECT  41.76 83.557 43.32 84.371 ;
     RECT  95.712 83.315 95.736 84.373 ;
     RECT  78 83.509 78.648 84.419 ;
     RECT  90.672 84.325 94.68 84.467 ;
     RECT  91.152 84.467 94.68 84.563 ;
     RECT  4.752 78.131 5.412 84.899 ;
     RECT  93.312 84.563 94.68 84.995 ;
     RECT  76.896 84.179 76.92 85.139 ;
     RECT  91.152 84.563 92.328 85.187 ;
     RECT  93.504 84.995 94.68 85.285 ;
     RECT  95.664 84.373 95.736 85.285 ;
     RECT  91.152 85.187 92.28 85.477 ;
     RECT  93.504 85.285 95.736 85.523 ;
     RECT  88.8 81.539 89.112 85.669 ;
     RECT  88.8 85.669 89.688 86.005 ;
     RECT  93.504 85.523 95.16 86.005 ;
     RECT  2.4 36.275 2.712 86.101 ;
     RECT  93.312 86.005 95.16 86.147 ;
     RECT  88.416 86.005 89.688 86.195 ;
     RECT  88.416 86.195 89.112 86.339 ;
     RECT  6.528 82.691 6.552 86.675 ;
     RECT  96.24 85.525 96.312 86.675 ;
     RECT  93.312 86.147 95.112 86.723 ;
     RECT  96.24 86.675 96.264 86.771 ;
     RECT  90.864 85.477 92.28 87.251 ;
     RECT  5.1 84.899 5.412 87.541 ;
     RECT  75.3 61.571 75.612 87.541 ;
     RECT  75.3 87.541 75.72 87.683 ;
     RECT  2.4 86.101 3.48 87.827 ;
     RECT  4.992 87.541 5.412 87.925 ;
     RECT  2.4 87.827 2.712 87.973 ;
     RECT  2.304 87.973 2.712 88.115 ;
     RECT  4.992 87.925 5.688 88.115 ;
     RECT  4.992 88.115 5.412 88.309 ;
     RECT  90.864 87.251 92.04 88.309 ;
     RECT  90.576 88.309 92.04 88.403 ;
     RECT  93.312 86.723 94.512 89.987 ;
     RECT  90.576 88.403 91.812 90.083 ;
     RECT  90.864 90.083 91.812 90.181 ;
     RECT  21.3 74.341 22.488 92.533 ;
     RECT  4.704 88.309 5.412 94.067 ;
     RECT  94.032 89.987 94.512 95.605 ;
     RECT  94.032 95.605 95.16 95.701 ;
     RECT  39.024 84.085 40.512 95.941 ;
     RECT  94.032 95.701 95.784 96.037 ;
     RECT  90.864 90.181 92.616 96.419 ;
     RECT  94.032 96.037 95.832 96.803 ;
     RECT  38.784 95.941 40.512 96.947 ;
     RECT  90.864 96.419 92.328 97.525 ;
     RECT  37.5 53.123 37.812 97.909 ;
     RECT  94.032 96.803 95.688 98.099 ;
     RECT  95.664 98.099 95.688 98.197 ;
     RECT  95.664 98.197 96.312 98.675 ;
     RECT  96.288 98.675 96.312 98.723 ;
     RECT  90.864 97.525 92.376 99.203 ;
     RECT  94.2 98.099 94.512 99.493 ;
     RECT  91.5 99.203 92.376 99.685 ;
     RECT  91.5 99.685 92.424 100.213 ;
     RECT  94.2 99.493 95.16 100.213 ;
     RECT  91.5 100.213 95.16 100.261 ;
     RECT  90.576 100.261 95.16 100.355 ;
     RECT  90.576 100.355 95.016 100.931 ;
     RECT  96.288 99.781 96.312 100.931 ;
     RECT  91.344 100.931 95.016 100.979 ;
     RECT  91.344 100.979 94.512 101.075 ;
     RECT  39.024 96.947 40.512 101.221 ;
     RECT  41.76 84.371 43.212 101.221 ;
     RECT  91.344 101.075 92.76 101.651 ;
     RECT  39.024 101.221 43.212 103.859 ;
     RECT  91.392 101.651 92.76 105.349 ;
     RECT  64.5 83.653 65.256 105.491 ;
     RECT  91.152 105.349 92.76 105.491 ;
     RECT  39.024 103.859 40.512 106.885 ;
     RECT  41.76 103.859 43.212 106.885 ;
     RECT  91.152 105.491 91.812 108.181 ;
     RECT  91.152 108.181 92.136 108.227 ;
     RECT  39.024 106.885 43.212 108.517 ;
     RECT  39.024 108.517 43.32 114.035 ;
     RECT  86.1 2.151 86.412 114.853 ;
     RECT  37.392 97.909 37.812 115.093 ;
     RECT  86.1 114.853 87.192 117.299 ;
     RECT  21.3 92.533 22.632 118.595 ;
     RECT  7.8 43.379 8.112 118.933 ;
     RECT  7.8 118.933 8.52 119.509 ;
     RECT  36.144 117.253 36.168 119.509 ;
     RECT  37.392 115.093 37.992 119.509 ;
     RECT  6.816 119.509 8.52 119.987 ;
     RECT  39.024 114.035 41.496 120.709 ;
     RECT  42.72 114.035 43.32 120.709 ;
     RECT  39.024 120.709 43.32 120.755 ;
     RECT  34.8 2.151 35.112 120.757 ;
     RECT  36.144 119.509 37.992 120.757 ;
     RECT  42.24 120.755 43.32 120.851 ;
     RECT  48.3 2.151 48.612 121.093 ;
     RECT  34.8 120.757 37.992 121.331 ;
     RECT  48.3 121.093 48.936 121.381 ;
     RECT  3.792 120.661 3.816 121.475 ;
     RECT  42.72 120.851 43.32 121.957 ;
     RECT  2.4 88.115 2.712 122.485 ;
     RECT  0.144 122.389 0.168 122.531 ;
     RECT  37.5 121.331 37.992 122.773 ;
     RECT  39.024 120.755 41.016 122.821 ;
     RECT  42.144 121.957 43.32 122.821 ;
     RECT  5.1 94.067 5.412 123.061 ;
     RECT  6.816 119.987 8.232 123.061 ;
     RECT  5.1 123.061 8.52 123.107 ;
     RECT  94.2 101.075 94.512 123.349 ;
     RECT  91.392 108.227 92.136 123.589 ;
     RECT  39.024 122.821 43.32 123.923 ;
     RECT  94.032 123.349 94.512 124.213 ;
     RECT  94.032 124.213 95.16 124.405 ;
     RECT  75.3 87.683 75.612 124.597 ;
     RECT  37.2 122.773 37.992 124.835 ;
     RECT  94.032 124.405 95.88 125.077 ;
     RECT  93.456 125.077 95.88 125.221 ;
     RECT  74.112 124.645 74.136 125.411 ;
     RECT  75.3 124.597 76.392 125.459 ;
     RECT  91.392 123.589 92.424 125.557 ;
     RECT  42.048 123.923 43.32 125.989 ;
     RECT  48.3 121.381 48.984 126.035 ;
     RECT  90.912 125.557 92.424 126.131 ;
     RECT  37.5 124.835 37.992 126.133 ;
     RECT  39.024 123.923 41.016 126.133 ;
     RECT  53.7 84.179 54.012 126.229 ;
     RECT  48.3 126.035 48.84 126.275 ;
     RECT  91.104 126.131 92.424 126.469 ;
     RECT  93.456 125.221 95.928 126.469 ;
     RECT  34.8 121.331 36.168 126.611 ;
     RECT  53.7 126.229 54.36 126.611 ;
     RECT  91.104 126.469 95.928 127.043 ;
     RECT  64.5 105.491 64.968 127.091 ;
     RECT  95.52 127.043 95.928 127.285 ;
     RECT  37.5 126.133 41.016 127.621 ;
     RECT  42 125.989 43.32 127.621 ;
     RECT  75.3 125.459 75.612 127.765 ;
     RECT  91.104 127.043 94.512 127.859 ;
     RECT  37.5 127.621 43.32 128.197 ;
     RECT  92.832 127.859 94.512 128.197 ;
     RECT  95.52 127.285 96.312 128.197 ;
     RECT  5.1 123.107 5.976 128.291 ;
     RECT  92.832 128.197 96.312 128.291 ;
     RECT  7.8 123.107 8.52 128.867 ;
     RECT  96.192 128.291 96.312 128.867 ;
     RECT  92.832 128.291 94.824 128.915 ;
     RECT  2.4 122.485 3.48 128.965 ;
     RECT  91.104 127.859 91.812 129.013 ;
     RECT  2.304 128.965 3.48 129.155 ;
     RECT  7.8 128.867 8.112 129.349 ;
     RECT  37.248 128.197 43.32 129.443 ;
     RECT  96.288 128.867 96.312 129.443 ;
     RECT  37.5 129.443 43.32 129.491 ;
     RECT  92.832 128.915 94.512 129.539 ;
     RECT  34.8 126.611 35.736 129.923 ;
     RECT  2.4 129.155 3.48 130.019 ;
     RECT  92.832 129.539 92.856 130.019 ;
     RECT  6.96 129.349 8.112 130.499 ;
     RECT  90.576 129.013 91.812 130.643 ;
     RECT  5.1 128.291 5.412 131.077 ;
     RECT  91.152 130.643 91.812 131.123 ;
     RECT  91.392 131.123 91.812 131.699 ;
     RECT  5.1 131.077 5.592 132.131 ;
     RECT  78 84.419 78.312 132.373 ;
     RECT  88.8 86.339 89.112 132.373 ;
     RECT  37.5 129.491 43.212 132.419 ;
     RECT  42.576 132.419 43.212 132.515 ;
     RECT  78 132.373 78.696 132.515 ;
     RECT  88.608 132.373 89.112 132.515 ;
     RECT  37.5 132.419 41.016 132.757 ;
     RECT  34.8 129.923 35.544 132.851 ;
     RECT  88.8 132.515 89.112 132.901 ;
     RECT  78 132.515 78.312 134.149 ;
     RECT  34.8 132.851 35.112 134.437 ;
     RECT  75.3 127.765 75.72 134.531 ;
     RECT  34.8 134.437 35.4 134.579 ;
     RECT  36.768 132.757 41.016 135.875 ;
     RECT  91.5 131.699 91.812 138.469 ;
     RECT  88.8 132.901 89.304 138.515 ;
     RECT  86.1 117.299 86.856 138.611 ;
     RECT  75.3 134.531 75.612 138.757 ;
     RECT  94.2 129.539 94.512 138.901 ;
     RECT  90.864 138.469 91.812 138.997 ;
     RECT  95.76 138.421 95.784 139.283 ;
     RECT  90.384 138.997 91.812 139.523 ;
     RECT  93.312 138.901 94.512 139.573 ;
     RECT  88.8 138.515 89.112 139.669 ;
     RECT  77.568 134.149 78.312 139.955 ;
     RECT  93.312 139.573 95.544 140.579 ;
     RECT  90.864 139.523 91.812 140.917 ;
     RECT  93.312 140.579 94.512 140.917 ;
     RECT  95.52 140.579 95.544 141.109 ;
     RECT  88.8 139.669 89.496 141.253 ;
     RECT  90.864 140.917 94.512 141.253 ;
     RECT  95.52 141.109 96.312 141.299 ;
     RECT  88.8 141.253 94.512 141.539 ;
     RECT  88.8 141.539 90.312 141.587 ;
     RECT  88.8 141.587 89.496 142.067 ;
     RECT  75.3 138.757 75.72 142.117 ;
     RECT  95.664 141.299 96.312 142.261 ;
     RECT  37.5 135.875 41.016 142.547 ;
     RECT  95.616 142.261 96.312 142.549 ;
     RECT  21.3 118.595 22.344 142.931 ;
     RECT  91.392 141.539 94.512 143.267 ;
     RECT  91.5 143.267 94.512 143.411 ;
     RECT  37.5 142.547 40.92 143.605 ;
     RECT  95.568 142.549 96.312 143.699 ;
     RECT  93.312 143.411 94.512 143.747 ;
     RECT  96.192 143.699 96.264 143.747 ;
     RECT  91.5 143.411 92.232 143.795 ;
     RECT  94.032 143.747 94.512 144.275 ;
     RECT  96.24 143.747 96.264 144.275 ;
     RECT  94.08 144.275 94.512 144.563 ;
     RECT  37.5 143.605 40.968 147.107 ;
     RECT  69.9 2.151 70.212 147.157 ;
     RECT  37.5 147.107 40.872 147.203 ;
     RECT  75.3 142.117 75.816 147.203 ;
     RECT  37.5 147.203 40.776 147.251 ;
     RECT  69.9 147.157 70.728 147.299 ;
     RECT  37.5 147.251 40.512 148.259 ;
     RECT  37.5 148.259 39.048 165.875 ;
     RECT  37.5 165.875 38.376 167.603 ;
     RECT  2.4 130.019 2.712 168.489 ;
     RECT  5.1 132.131 5.412 168.489 ;
     RECT  7.8 130.499 8.112 168.489 ;
     RECT  10.5 2.151 10.812 168.489 ;
     RECT  13.2 76.211 13.512 168.489 ;
     RECT  15.9 2.151 16.212 168.489 ;
     RECT  18.6 2.151 18.912 168.489 ;
     RECT  21.3 142.931 21.612 168.489 ;
     RECT  24 2.151 24.312 168.489 ;
     RECT  26.7 2.151 27.012 168.489 ;
     RECT  29.4 2.151 29.712 168.489 ;
     RECT  32.1 2.151 32.412 168.489 ;
     RECT  34.8 134.579 35.112 168.489 ;
     RECT  40.2 148.259 40.512 168.489 ;
     RECT  42.9 132.515 43.212 168.489 ;
     RECT  45.6 2.151 45.912 168.489 ;
     RECT  48.3 126.275 48.612 168.489 ;
     RECT  51 2.151 51.312 168.489 ;
     RECT  53.7 126.611 54.012 168.489 ;
     RECT  56.4 2.151 56.712 168.489 ;
     RECT  59.1 2.151 59.412 168.489 ;
     RECT  61.8 2.151 62.112 168.489 ;
     RECT  64.5 127.091 64.812 168.489 ;
     RECT  67.2 84.083 67.512 168.489 ;
     RECT  69.9 147.299 70.212 168.489 ;
     RECT  72.6 84.083 72.912 168.489 ;
     RECT  75.3 147.203 75.612 168.489 ;
     RECT  78 139.955 78.312 168.489 ;
     RECT  80.7 2.151 81.012 168.489 ;
     RECT  83.4 83.843 83.712 168.489 ;
     RECT  86.1 138.611 86.412 168.489 ;
     RECT  88.8 142.067 89.112 168.489 ;
     RECT  91.5 143.795 91.812 168.489 ;
     RECT  94.2 144.563 94.512 168.489 ;
     RECT  2.4 168.489 2.52 168.503 ;
     RECT  5.1 168.489 5.22 168.503 ;
     RECT  7.8 168.489 7.92 168.503 ;
     RECT  10.5 168.489 10.62 168.503 ;
     RECT  13.2 168.489 13.32 168.503 ;
     RECT  15.9 168.489 16.02 168.503 ;
     RECT  18.6 168.489 18.72 168.503 ;
     RECT  21.3 168.489 21.42 168.503 ;
     RECT  24 168.489 24.12 168.503 ;
     RECT  26.7 168.489 26.82 168.503 ;
     RECT  29.4 168.489 29.52 168.503 ;
     RECT  32.1 168.489 32.22 168.503 ;
     RECT  34.8 168.489 34.92 168.503 ;
     RECT  37.5 167.603 38.136 168.503 ;
     RECT  40.2 168.489 40.32 168.503 ;
     RECT  42.9 168.489 43.02 168.503 ;
     RECT  45.6 168.489 45.72 168.503 ;
     RECT  48.3 168.489 48.42 168.503 ;
     RECT  51 168.489 51.12 168.503 ;
     RECT  53.7 168.489 53.82 168.503 ;
     RECT  56.4 168.489 56.52 168.503 ;
     RECT  59.1 168.489 59.22 168.503 ;
     RECT  61.8 168.489 61.92 168.503 ;
     RECT  64.5 168.489 64.62 168.503 ;
     RECT  67.2 168.489 67.32 168.503 ;
     RECT  69.9 168.489 70.02 168.503 ;
     RECT  72.6 168.489 72.72 168.503 ;
     RECT  75.3 168.489 75.42 168.503 ;
     RECT  78 168.489 78.12 168.503 ;
     RECT  80.7 168.489 80.82 168.503 ;
     RECT  83.4 168.489 83.52 168.503 ;
     RECT  86.1 168.489 86.22 168.503 ;
     RECT  88.8 168.489 88.92 168.503 ;
     RECT  91.5 168.489 91.62 168.503 ;
     RECT  94.2 168.489 94.32 168.503 ;
     RECT  37.968 168.503 38.136 170.435 ;
     RECT  37.968 170.435 37.992 170.531 ;
     RECT  8.112 34.835 8.232 35.845 ;
     RECT  2.712 34.979 3.432 35.605 ;
     RECT  2.712 35.605 3.936 40.691 ;
     RECT  3.96 35.605 5.1 40.691 ;
     RECT  91.812 38.725 92.88 39.059 ;
     RECT  92.904 38.725 93.984 39.059 ;
     RECT  91.812 39.059 93.984 39.443 ;
     RECT  89.112 39.205 90.096 40.451 ;
     RECT  90.12 39.205 91.5 40.451 ;
     RECT  91.812 39.443 94.032 39.637 ;
     RECT  95.688 39.491 95.736 40.355 ;
     RECT  91.812 39.637 93.024 41.027 ;
     RECT  93.048 39.637 94.032 39.779 ;
     RECT  93.048 39.779 94.08 39.923 ;
     RECT  93.048 39.923 94.2 40.981 ;
     RECT  10.812 40.165 12.144 74.627 ;
     RECT  12.168 40.165 13.2 74.581 ;
     RECT  94.512 40.211 95.664 40.355 ;
     RECT  94.512 40.355 95.736 40.885 ;
     RECT  89.112 40.451 89.208 40.549 ;
     RECT  2.712 40.691 5.1 42.133 ;
     RECT  78.312 40.837 79.488 46.837 ;
     RECT  79.512 40.837 80.7 46.501 ;
     RECT  94.512 40.885 95.712 42.037 ;
     RECT  93.048 40.981 94.08 41.027 ;
     RECT  6.96 41.843 7.8 43.285 ;
     RECT  94.512 42.037 95.616 42.133 ;
     RECT  2.712 42.133 3.984 43.187 ;
     RECT  4.008 42.133 5.1 43.187 ;
     RECT  94.632 42.133 95.616 42.899 ;
     RECT  91.812 42.709 92.832 43.955 ;
     RECT  94.632 42.899 96.24 43.141 ;
     RECT  95.16 43.141 96.24 43.955 ;
     RECT  6.312 43.285 7.8 43.861 ;
     RECT  6.408 43.861 7.8 49.907 ;
     RECT  91.812 43.955 93.6 44.437 ;
     RECT  40.92 44.437 42.432 50.195 ;
     RECT  92.328 44.437 93.6 47.845 ;
     RECT  5.412 45.059 6.384 49.907 ;
     RECT  79.56 46.501 80.7 47.555 ;
     RECT  78.312 46.979 79.488 47.363 ;
     RECT  78.312 47.363 79.536 47.555 ;
     RECT  93 47.891 94.032 50.677 ;
     RECT  91.812 50.195 92.976 52.981 ;
     RECT  94.512 51.781 95.76 52.309 ;
     RECT  94.512 52.309 95.52 53.557 ;
     RECT  91.812 52.981 92.928 53.365 ;
     RECT  91.812 53.365 92.88 54.275 ;
     RECT  91.812 54.275 92.928 56.531 ;
     RECT  95.16 56.483 96.192 57.635 ;
     RECT  91.812 56.531 92.04 57.205 ;
     RECT  89.784 56.677 91.296 57.443 ;
     RECT  65.784 65.701 67.2 75.445 ;
     RECT  75.612 70.645 76.896 72.995 ;
     RECT  76.92 70.645 78 72.995 ;
     RECT  89.784 72.661 91.2 72.803 ;
     RECT  92.616 72.757 93.744 80.773 ;
     RECT  75.612 72.995 78 73.285 ;
     RECT  75.612 73.285 76.608 84.179 ;
     RECT  76.632 73.285 78 83.749 ;
     RECT  22.488 74.341 24 92.533 ;
     RECT  10.812 74.627 12.24 76.211 ;
     RECT  2.712 75.925 3.984 77.555 ;
     RECT  4.008 75.925 5.1 77.269 ;
     RECT  5.412 76.165 6.624 82.645 ;
     RECT  6.648 76.165 7.8 82.691 ;
     RECT  65.112 78.131 66.528 83.653 ;
     RECT  83.712 81.109 84.912 82.115 ;
     RECT  84.936 81.109 86.1 82.115 ;
     RECT  90.12 81.493 91.5 83.173 ;
     RECT  89.112 81.539 90.096 83.267 ;
     RECT  95.784 81.683 95.928 82.645 ;
     RECT  5.412 82.645 6.528 86.675 ;
     RECT  6.552 82.691 7.8 86.675 ;
     RECT  94.512 82.691 95.712 84.325 ;
     RECT  90.12 83.173 91.344 83.267 ;
     RECT  89.112 83.267 91.344 83.749 ;
     RECT  40.512 83.557 41.76 101.221 ;
     RECT  65.256 83.653 66.528 83.795 ;
     RECT  37.812 83.749 39.024 95.941 ;
     RECT  39.048 83.749 40.2 84.085 ;
     RECT  76.92 83.749 78 85.139 ;
     RECT  89.112 83.749 90.432 84.131 ;
     RECT  65.256 83.795 66.72 84.083 ;
     RECT  75.612 84.179 76.896 85.139 ;
     RECT  94.68 84.325 95.712 84.373 ;
     RECT  94.68 84.373 95.664 85.285 ;
     RECT  90.672 84.467 91.152 85.477 ;
     RECT  92.328 84.563 93.312 84.995 ;
     RECT  92.328 84.995 93.504 85.187 ;
     RECT  92.28 85.187 93.504 86.005 ;
     RECT  90.672 85.477 90.864 85.669 ;
     RECT  95.16 85.523 95.736 85.525 ;
     RECT  95.16 85.525 96.24 86.147 ;
     RECT  89.688 85.669 90.864 86.195 ;
     RECT  92.28 86.005 93.312 87.251 ;
     RECT  95.112 86.147 96.24 86.723 ;
     RECT  5.412 86.675 5.688 87.925 ;
     RECT  92.04 87.251 93.312 88.403 ;
     RECT  3.48 87.541 4.992 87.827 ;
     RECT  4.704 87.827 4.992 88.309 ;
     RECT  89.112 88.309 90.576 90.083 ;
     RECT  91.812 88.403 93.312 89.987 ;
     RECT  91.812 89.987 94.032 90.181 ;
     RECT  92.616 90.181 94.032 96.419 ;
     RECT  22.632 92.533 24 118.595 ;
     RECT  37.812 95.941 38.784 96.947 ;
     RECT  92.328 96.419 92.376 97.525 ;
     RECT  95.688 96.803 95.832 98.197 ;
     RECT  37.812 96.947 39.024 115.093 ;
     RECT  94.512 98.099 95.664 98.675 ;
     RECT  94.512 98.675 96.288 98.723 ;
     RECT  94.512 98.723 96.312 99.493 ;
     RECT  90.864 99.203 91.5 100.261 ;
     RECT  95.16 99.493 96.312 99.781 ;
     RECT  95.16 99.781 96.288 100.355 ;
     RECT  89.112 100.261 90.576 100.931 ;
     RECT  95.016 100.355 96.288 100.931 ;
     RECT  92.76 101.075 94.2 105.491 ;
     RECT  40.512 103.859 41.76 106.885 ;
     RECT  41.496 114.035 42.72 120.709 ;
     RECT  37.992 115.093 39.024 126.133 ;
     RECT  35.112 117.253 36.144 120.757 ;
     RECT  36.168 117.253 37.392 119.509 ;
     RECT  5.412 119.509 6.816 123.061 ;
     RECT  2.712 120.661 3.792 121.475 ;
     RECT  3.816 120.661 5.1 121.475 ;
     RECT  41.016 120.755 42.24 120.851 ;
     RECT  41.016 120.851 42.72 121.957 ;
     RECT  36.168 121.331 37.5 122.773 ;
     RECT  2.712 121.475 3.48 122.485 ;
     RECT  41.016 121.957 42.144 122.821 ;
     RECT  36.168 122.773 37.2 124.835 ;
     RECT  41.016 123.923 42.048 125.989 ;
     RECT  72.912 124.645 74.112 125.411 ;
     RECT  74.136 124.645 75.3 125.411 ;
     RECT  36.168 124.835 37.5 126.611 ;
     RECT  92.424 125.077 93.456 126.469 ;
     RECT  41.016 125.989 42 127.621 ;
     RECT  94.512 127.043 95.52 128.197 ;
     RECT  91.812 127.859 92.832 130.019 ;
     RECT  35.736 128.197 37.248 129.443 ;
     RECT  94.824 128.291 96.192 128.867 ;
     RECT  94.824 128.867 96.288 128.915 ;
     RECT  89.112 129.013 90.576 130.643 ;
     RECT  92.856 129.539 94.2 130.019 ;
     RECT  35.544 132.757 36.768 132.851 ;
     RECT  35.4 134.437 36.768 134.579 ;
     RECT  94.512 138.421 95.76 139.283 ;
     RECT  89.112 138.515 89.304 138.997 ;
     RECT  91.812 138.901 93.312 140.917 ;
     RECT  89.112 138.997 90.384 139.523 ;
     RECT  94.512 139.283 95.544 139.573 ;
     RECT  89.112 139.523 90.864 139.669 ;
     RECT  89.496 139.669 90.864 141.253 ;
     RECT  94.512 140.579 95.52 141.299 ;
     RECT  94.512 141.299 95.664 142.261 ;
     RECT  90.312 141.539 91.392 141.587 ;
     RECT  94.512 142.261 95.616 142.549 ;
     RECT  40.92 142.547 40.968 143.605 ;
     RECT  94.512 142.549 95.568 143.699 ;
     RECT  92.232 143.411 93.312 143.747 ;
     RECT  39.048 148.259 40.2 165.875 ;
  END
END qfd_landh0d8s_183_EW_98x171
END LIBRARY
